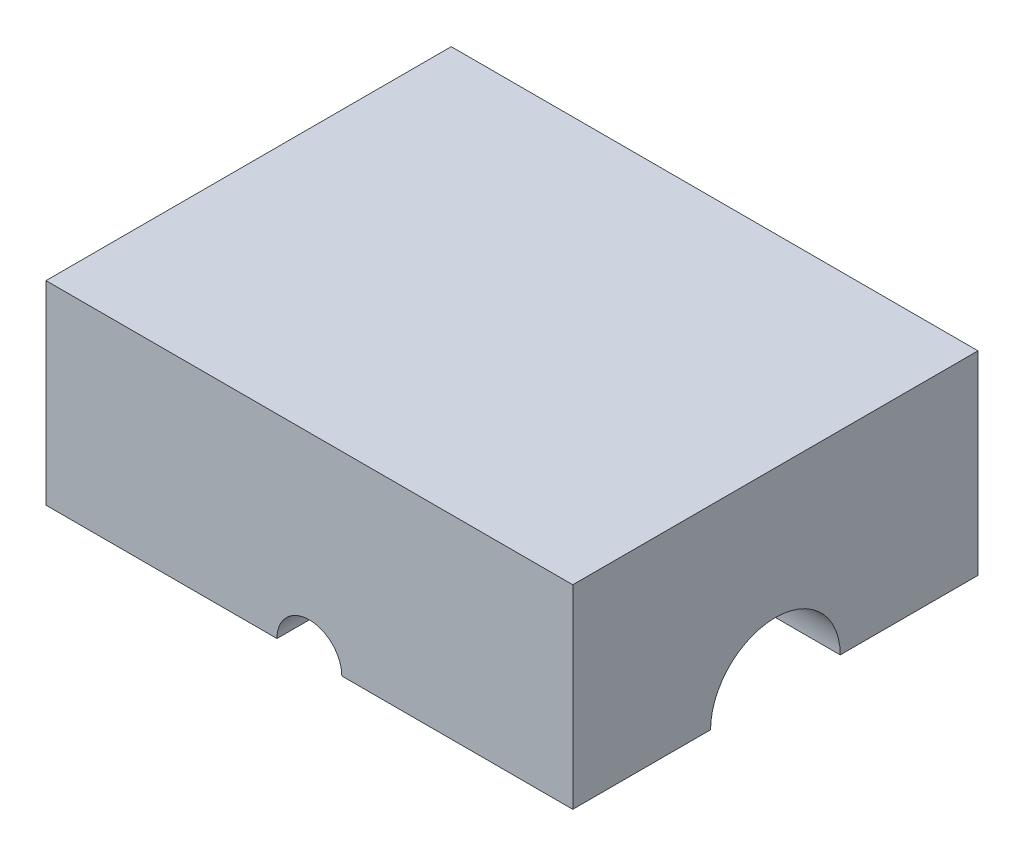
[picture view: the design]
ISO-10303-21;
HEADER;
FILE_DESCRIPTION(('STEP AP214'),'2;1');
FILE_NAME('part.step','',(''),(''),'','','');
FILE_SCHEMA(('AUTOMOTIVE_DESIGN { 1 0 10303 214 1 1 1 1 }'));
ENDSEC;
DATA;
#1=APPLICATION_CONTEXT('core data for automotive mechanical design processes');
#2=APPLICATION_PROTOCOL_DEFINITION('international standard','automotive_design',2000,#1);
#3=PRODUCT_CONTEXT('',#1,'mechanical');
#4=PRODUCT('Part','Part','',(#3));
#5=PRODUCT_RELATED_PRODUCT_CATEGORY('part','',(#4));
#6=PRODUCT_DEFINITION_FORMATION('','',#4);
#7=PRODUCT_DEFINITION_CONTEXT('part definition',#1,'design');
#8=PRODUCT_DEFINITION('design','',#6,#7);
#9=PRODUCT_DEFINITION_SHAPE('','',#8);
#10=(LENGTH_UNIT() NAMED_UNIT(*) SI_UNIT(.MILLI.,.METRE.));
#11=(NAMED_UNIT(*) PLANE_ANGLE_UNIT() SI_UNIT($,.RADIAN.));
#12=(NAMED_UNIT(*) SI_UNIT($,.STERADIAN.) SOLID_ANGLE_UNIT());
#13=UNCERTAINTY_MEASURE_WITH_UNIT(LENGTH_MEASURE(1.E-05),#10,'distance_accuracy_value','');
#14=(GEOMETRIC_REPRESENTATION_CONTEXT(3) GLOBAL_UNCERTAINTY_ASSIGNED_CONTEXT((#13)) GLOBAL_UNIT_ASSIGNED_CONTEXT((#10,
#11,#12)) REPRESENTATION_CONTEXT('',''));
#15=CARTESIAN_POINT('',(0.,0.,0.));
#16=DIRECTION('',(0.,0.,1.));
#17=DIRECTION('',(1.,0.,0.));
#18=AXIS2_PLACEMENT_3D('',#15,#16,#17);
#19=CARTESIAN_POINT('',(206.375,0.,-158.75));
#20=DIRECTION('',(0.,-1.,0.));
#21=DIRECTION('',(0.,0.,-1.));
#22=AXIS2_PLACEMENT_3D('',#19,#20,#21);
#23=PLANE('',#22);
#24=DIRECTION('',(1.,0.,0.));
#25=VECTOR('',#24,1.);
#26=CARTESIAN_POINT('',(-206.375,0.,-50.8));
#27=LINE('',#26,#25);
#28=CARTESIAN_POINT('',(101.6,0.,-50.8));
#29=VERTEX_POINT('',#28);
#30=CARTESIAN_POINT('',(206.375,0.,-50.8));
#31=VERTEX_POINT('',#30);
#32=EDGE_CURVE('E291',#29,#31,#27,.T.);
#33=ORIENTED_EDGE('',*,*,#32,.F.);
#34=CARTESIAN_POINT('',(101.6,0.,-76.2));
#35=DIRECTION('',(0.,-1.,0.));
#36=DIRECTION('',(0.,0.,-1.));
#37=AXIS2_PLACEMENT_3D('',#34,#35,#36);
#38=CIRCLE('',#37,25.4);
#39=CARTESIAN_POINT('',(76.2,0.,-76.2));
#40=VERTEX_POINT('',#39);
#41=EDGE_CURVE('E283',#29,#40,#38,.T.);
#42=ORIENTED_EDGE('',*,*,#41,.T.);
#43=DIRECTION('',(0.,0.,1.));
#44=VECTOR('',#43,1.);
#45=CARTESIAN_POINT('',(76.2,0.,212.191735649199));
#46=LINE('',#45,#44);
#47=CARTESIAN_POINT('',(76.2,0.,-95.2500000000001));
#48=VERTEX_POINT('',#47);
#49=EDGE_CURVE('E208',#48,#40,#46,.T.);
#50=ORIENTED_EDGE('',*,*,#49,.F.);
#51=DIRECTION('',(1.,0.,0.));
#52=VECTOR('',#51,1.);
#53=CARTESIAN_POINT('',(206.375,0.,-95.2500000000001));
#54=LINE('',#53,#52);
#55=CARTESIAN_POINT('',(25.4,0.,-95.2500000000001));
#56=VERTEX_POINT('',#55);
#57=EDGE_CURVE('E197',#56,#48,#54,.T.);
#58=ORIENTED_EDGE('',*,*,#57,.F.);
#59=DIRECTION('',(0.,0.,1.));
#60=VECTOR('',#59,1.);
#61=CARTESIAN_POINT('',(25.4,0.,212.191735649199));
#62=LINE('',#61,#60);
#63=CARTESIAN_POINT('',(25.4,0.,-158.75));
#64=VERTEX_POINT('',#63);
#65=EDGE_CURVE('E206',#64,#56,#62,.T.);
#66=ORIENTED_EDGE('',*,*,#65,.F.);
#67=DIRECTION('',(-1.,0.,0.));
#68=VECTOR('',#67,1.);
#69=CARTESIAN_POINT('',(-206.375,0.,-158.75));
#70=LINE('',#69,#68);
#71=CARTESIAN_POINT('',(206.375,0.,-158.75));
#72=VERTEX_POINT('',#71);
#73=EDGE_CURVE('E174',#72,#64,#70,.T.);
#74=ORIENTED_EDGE('',*,*,#73,.F.);
#75=DIRECTION('',(0.,0.,-1.));
#76=VECTOR('',#75,1.);
#77=CARTESIAN_POINT('',(206.375,0.,158.75));
#78=LINE('',#77,#76);
#79=EDGE_CURVE('E326',#31,#72,#78,.T.);
#80=ORIENTED_EDGE('',*,*,#79,.F.);
#81=EDGE_LOOP('',(#33,#42,#50,#58,#66,#74,#80));
#82=FACE_BOUND('',#81,.T.);
#83=ADVANCED_FACE('F33',(#82),#23,.T.);
#84=DIRECTION('',(0.,0.,1.));
#85=VECTOR('',#84,1.);
#86=CARTESIAN_POINT('',(-76.2,0.,212.191735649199));
#87=LINE('',#86,#85);
#88=CARTESIAN_POINT('',(-76.2,0.,-76.2));
#89=VERTEX_POINT('',#88);
#90=CARTESIAN_POINT('',(-76.2,0.,-95.2500000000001));
#91=VERTEX_POINT('',#90);
#92=EDGE_CURVE('E196',#89,#91,#87,.F.);
#93=ORIENTED_EDGE('',*,*,#92,.F.);
#94=CARTESIAN_POINT('',(-101.6,0.,-76.2));
#95=DIRECTION('',(0.,-1.,0.));
#96=DIRECTION('',(0.,0.,-1.));
#97=AXIS2_PLACEMENT_3D('',#94,#95,#96);
#98=CIRCLE('',#97,25.4);
#99=CARTESIAN_POINT('',(-101.6,0.,-50.8));
#100=VERTEX_POINT('',#99);
#101=EDGE_CURVE('E60',#89,#100,#98,.T.);
#102=ORIENTED_EDGE('',*,*,#101,.T.);
#103=DIRECTION('',(1.,0.,0.));
#104=VECTOR('',#103,1.);
#105=CARTESIAN_POINT('',(-206.375,0.,-50.8));
#106=LINE('',#105,#104);
#107=CARTESIAN_POINT('',(-206.375,0.,-50.8));
#108=VERTEX_POINT('',#107);
#109=EDGE_CURVE('E150',#108,#100,#106,.T.);
#110=ORIENTED_EDGE('',*,*,#109,.F.);
#111=DIRECTION('',(0.,0.,1.));
#112=VECTOR('',#111,1.);
#113=CARTESIAN_POINT('',(-206.375,0.,158.75));
#114=LINE('',#113,#112);
#115=CARTESIAN_POINT('',(-206.375,0.,-158.75));
#116=VERTEX_POINT('',#115);
#117=EDGE_CURVE('E161',#116,#108,#114,.T.);
#118=ORIENTED_EDGE('',*,*,#117,.F.);
#119=CARTESIAN_POINT('',(-25.4,0.,-158.75));
#120=VERTEX_POINT('',#119);
#121=EDGE_CURVE('E334',#120,#116,#70,.T.);
#122=ORIENTED_EDGE('',*,*,#121,.F.);
#123=DIRECTION('',(0.,0.,1.));
#124=VECTOR('',#123,1.);
#125=CARTESIAN_POINT('',(-25.4,0.,212.191735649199));
#126=LINE('',#125,#124);
#127=CARTESIAN_POINT('',(-25.4,0.,-95.25));
#128=VERTEX_POINT('',#127);
#129=EDGE_CURVE('E191',#128,#120,#126,.F.);
#130=ORIENTED_EDGE('',*,*,#129,.F.);
#131=EDGE_CURVE('E193',#91,#128,#54,.T.);
#132=ORIENTED_EDGE('',*,*,#131,.F.);
#133=EDGE_LOOP('',(#93,#102,#110,#118,#122,#130,#132));
#134=FACE_BOUND('',#133,.T.);
#135=ADVANCED_FACE('F159',(#134),#23,.T.);
#136=CARTESIAN_POINT('',(76.2,0.,76.2));
#137=VERTEX_POINT('',#136);
#138=CARTESIAN_POINT('',(76.2,0.,95.25));
#139=VERTEX_POINT('',#138);
#140=EDGE_CURVE('E211',#137,#139,#46,.T.);
#141=ORIENTED_EDGE('',*,*,#140,.F.);
#142=CARTESIAN_POINT('',(101.6,0.,76.2));
#143=DIRECTION('',(0.,-1.,0.));
#144=DIRECTION('',(0.,0.,-1.));
#145=AXIS2_PLACEMENT_3D('',#142,#143,#144);
#146=CIRCLE('',#145,25.4);
#147=CARTESIAN_POINT('',(101.6,0.,50.8));
#148=VERTEX_POINT('',#147);
#149=EDGE_CURVE('E284',#137,#148,#146,.T.);
#150=ORIENTED_EDGE('',*,*,#149,.T.);
#151=DIRECTION('',(1.,0.,0.));
#152=VECTOR('',#151,1.);
#153=CARTESIAN_POINT('',(-206.375,0.,50.8));
#154=LINE('',#153,#152);
#155=CARTESIAN_POINT('',(206.375,0.,50.8));
#156=VERTEX_POINT('',#155);
#157=EDGE_CURVE('E155',#156,#148,#154,.F.);
#158=ORIENTED_EDGE('',*,*,#157,.F.);
#159=CARTESIAN_POINT('',(206.375,0.,158.75));
#160=VERTEX_POINT('',#159);
#161=EDGE_CURVE('E333',#160,#156,#78,.T.);
#162=ORIENTED_EDGE('',*,*,#161,.F.);
#163=DIRECTION('',(1.,0.,0.));
#164=VECTOR('',#163,1.);
#165=CARTESIAN_POINT('',(-206.375,0.,158.75));
#166=LINE('',#165,#164);
#167=CARTESIAN_POINT('',(25.4,0.,158.75));
#168=VERTEX_POINT('',#167);
#169=EDGE_CURVE('E169',#168,#160,#166,.T.);
#170=ORIENTED_EDGE('',*,*,#169,.F.);
#171=DIRECTION('',(0.,0.,1.));
#172=VECTOR('',#171,1.);
#173=CARTESIAN_POINT('',(25.4,0.,212.191735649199));
#174=LINE('',#173,#172);
#175=CARTESIAN_POINT('',(25.4,0.,95.25));
#176=VERTEX_POINT('',#175);
#177=EDGE_CURVE('E212',#176,#168,#174,.T.);
#178=ORIENTED_EDGE('',*,*,#177,.F.);
#179=DIRECTION('',(-1.,0.,0.));
#180=VECTOR('',#179,1.);
#181=CARTESIAN_POINT('',(206.375,0.,95.25));
#182=LINE('',#181,#180);
#183=EDGE_CURVE('E204',#139,#176,#182,.T.);
#184=ORIENTED_EDGE('',*,*,#183,.F.);
#185=EDGE_LOOP('',(#141,#150,#158,#162,#170,#178,#184));
#186=FACE_BOUND('',#185,.T.);
#187=ADVANCED_FACE('F303',(#186),#23,.T.);
#188=CARTESIAN_POINT('',(206.375,152.4,158.75));
#189=DIRECTION('',(-1.,0.,0.));
#190=DIRECTION('',(0.,0.,1.));
#191=AXIS2_PLACEMENT_3D('',#188,#189,#190);
#192=PLANE('',#191);
#193=ORIENTED_EDGE('',*,*,#161,.T.);
#194=CARTESIAN_POINT('',(206.375,0.,0.));
#195=DIRECTION('',(1.,0.,0.));
#196=DIRECTION('',(0.,0.,-1.));
#197=AXIS2_PLACEMENT_3D('',#194,#195,#196);
#198=CIRCLE('',#197,50.8);
#199=EDGE_CURVE('E156',#31,#156,#198,.T.);
#200=ORIENTED_EDGE('',*,*,#199,.F.);
#201=ORIENTED_EDGE('',*,*,#79,.T.);
#202=DIRECTION('',(0.,-1.,0.));
#203=VECTOR('',#202,1.);
#204=CARTESIAN_POINT('',(206.375,152.4,-158.75));
#205=LINE('',#204,#203);
#206=CARTESIAN_POINT('',(206.375,152.4,-158.75));
#207=VERTEX_POINT('',#206);
#208=EDGE_CURVE('E188',#207,#72,#205,.T.);
#209=ORIENTED_EDGE('',*,*,#208,.F.);
#210=DIRECTION('',(0.,0.,-1.));
#211=VECTOR('',#210,1.);
#212=CARTESIAN_POINT('',(206.375,152.4,158.75));
#213=LINE('',#212,#211);
#214=CARTESIAN_POINT('',(206.375,152.4,158.75));
#215=VERTEX_POINT('',#214);
#216=EDGE_CURVE('E179',#215,#207,#213,.T.);
#217=ORIENTED_EDGE('',*,*,#216,.F.);
#218=DIRECTION('',(0.,-1.,0.));
#219=VECTOR('',#218,1.);
#220=CARTESIAN_POINT('',(206.375,152.4,158.75));
#221=LINE('',#220,#219);
#222=EDGE_CURVE('E180',#215,#160,#221,.T.);
#223=ORIENTED_EDGE('',*,*,#222,.T.);
#224=EDGE_LOOP('',(#193,#200,#201,#209,#217,#223));
#225=FACE_BOUND('',#224,.T.);
#226=ADVANCED_FACE('F235',(#225),#192,.F.);
#227=CARTESIAN_POINT('',(-206.375,152.4,-158.75));
#228=DIRECTION('',(0.,0.,1.));
#229=DIRECTION('',(1.,0.,0.));
#230=AXIS2_PLACEMENT_3D('',#227,#228,#229);
#231=PLANE('',#230);
#232=ORIENTED_EDGE('',*,*,#73,.T.);
#233=CARTESIAN_POINT('',(0.,0.,-158.75));
#234=DIRECTION('',(0.,0.,1.));
#235=DIRECTION('',(1.,0.,0.));
#236=AXIS2_PLACEMENT_3D('',#233,#234,#235);
#237=CIRCLE('',#236,25.4);
#238=EDGE_CURVE('E162',#64,#120,#237,.T.);
#239=ORIENTED_EDGE('',*,*,#238,.T.);
#240=ORIENTED_EDGE('',*,*,#121,.T.);
#241=DIRECTION('',(0.,-1.,0.));
#242=VECTOR('',#241,1.);
#243=CARTESIAN_POINT('',(-206.375,152.4,-158.75));
#244=LINE('',#243,#242);
#245=CARTESIAN_POINT('',(-206.375,152.4,-158.75));
#246=VERTEX_POINT('',#245);
#247=EDGE_CURVE('E168',#246,#116,#244,.T.);
#248=ORIENTED_EDGE('',*,*,#247,.F.);
#249=DIRECTION('',(-1.,0.,0.));
#250=VECTOR('',#249,1.);
#251=CARTESIAN_POINT('',(-206.375,152.4,-158.75));
#252=LINE('',#251,#250);
#253=EDGE_CURVE('E329',#207,#246,#252,.T.);
#254=ORIENTED_EDGE('',*,*,#253,.F.);
#255=ORIENTED_EDGE('',*,*,#208,.T.);
#256=EDGE_LOOP('',(#232,#239,#240,#248,#254,#255));
#257=FACE_BOUND('',#256,.T.);
#258=ADVANCED_FACE('F342',(#257),#231,.F.);
#259=CARTESIAN_POINT('',(-206.375,152.4,158.75));
#260=DIRECTION('',(1.,0.,0.));
#261=DIRECTION('',(0.,0.,-1.));
#262=AXIS2_PLACEMENT_3D('',#259,#260,#261);
#263=PLANE('',#262);
#264=ORIENTED_EDGE('',*,*,#117,.T.);
#265=CARTESIAN_POINT('',(-206.375,0.,0.));
#266=DIRECTION('',(1.,0.,0.));
#267=DIRECTION('',(0.,0.,-1.));
#268=AXIS2_PLACEMENT_3D('',#265,#266,#267);
#269=CIRCLE('',#268,50.8);
#270=CARTESIAN_POINT('',(-206.375,0.,50.8));
#271=VERTEX_POINT('',#270);
#272=EDGE_CURVE('E148',#108,#271,#269,.T.);
#273=ORIENTED_EDGE('',*,*,#272,.T.);
#274=CARTESIAN_POINT('',(-206.375,0.,158.75));
#275=VERTEX_POINT('',#274);
#276=EDGE_CURVE('E170',#271,#275,#114,.T.);
#277=ORIENTED_EDGE('',*,*,#276,.T.);
#278=DIRECTION('',(0.,-1.,0.));
#279=VECTOR('',#278,1.);
#280=CARTESIAN_POINT('',(-206.375,152.4,158.75));
#281=LINE('',#280,#279);
#282=CARTESIAN_POINT('',(-206.375,152.4,158.75));
#283=VERTEX_POINT('',#282);
#284=EDGE_CURVE('E183',#283,#275,#281,.T.);
#285=ORIENTED_EDGE('',*,*,#284,.F.);
#286=DIRECTION('',(0.,0.,1.));
#287=VECTOR('',#286,1.);
#288=CARTESIAN_POINT('',(-206.375,152.4,158.75));
#289=LINE('',#288,#287);
#290=EDGE_CURVE('E331',#246,#283,#289,.T.);
#291=ORIENTED_EDGE('',*,*,#290,.F.);
#292=ORIENTED_EDGE('',*,*,#247,.T.);
#293=EDGE_LOOP('',(#264,#273,#277,#285,#291,#292));
#294=FACE_BOUND('',#293,.T.);
#295=ADVANCED_FACE('F165',(#294),#263,.F.);
#296=CARTESIAN_POINT('',(-206.375,152.4,158.75));
#297=DIRECTION('',(0.,0.,-1.));
#298=DIRECTION('',(-1.,0.,0.));
#299=AXIS2_PLACEMENT_3D('',#296,#297,#298);
#300=PLANE('',#299);
#301=CARTESIAN_POINT('',(-25.4,0.,158.75));
#302=VERTEX_POINT('',#301);
#303=EDGE_CURVE('E172',#275,#302,#166,.T.);
#304=ORIENTED_EDGE('',*,*,#303,.T.);
#305=CARTESIAN_POINT('',(0.,0.,158.75));
#306=DIRECTION('',(0.,0.,1.));
#307=DIRECTION('',(1.,0.,0.));
#308=AXIS2_PLACEMENT_3D('',#305,#306,#307);
#309=CIRCLE('',#308,25.4);
#310=EDGE_CURVE('E324',#168,#302,#309,.T.);
#311=ORIENTED_EDGE('',*,*,#310,.F.);
#312=ORIENTED_EDGE('',*,*,#169,.T.);
#313=ORIENTED_EDGE('',*,*,#222,.F.);
#314=DIRECTION('',(1.,0.,0.));
#315=VECTOR('',#314,1.);
#316=CARTESIAN_POINT('',(-206.375,152.4,158.75));
#317=LINE('',#316,#315);
#318=EDGE_CURVE('E184',#283,#215,#317,.T.);
#319=ORIENTED_EDGE('',*,*,#318,.F.);
#320=ORIENTED_EDGE('',*,*,#284,.T.);
#321=EDGE_LOOP('',(#304,#311,#312,#313,#319,#320));
#322=FACE_BOUND('',#321,.T.);
#323=ADVANCED_FACE('F351',(#322),#300,.F.);
#324=CARTESIAN_POINT('',(206.375,152.4,-158.75));
#325=DIRECTION('',(0.,-1.,0.));
#326=DIRECTION('',(0.,0.,-1.));
#327=AXIS2_PLACEMENT_3D('',#324,#325,#326);
#328=PLANE('',#327);
#329=ORIENTED_EDGE('',*,*,#216,.T.);
#330=ORIENTED_EDGE('',*,*,#253,.T.);
#331=ORIENTED_EDGE('',*,*,#290,.T.);
#332=ORIENTED_EDGE('',*,*,#318,.T.);
#333=EDGE_LOOP('',(#329,#330,#331,#332));
#334=FACE_BOUND('',#333,.T.);
#335=ADVANCED_FACE('F344',(#334),#328,.F.);
#336=DIRECTION('',(1.,0.,0.));
#337=VECTOR('',#336,1.);
#338=CARTESIAN_POINT('',(-206.375,0.,50.8));
#339=LINE('',#338,#337);
#340=CARTESIAN_POINT('',(-101.6,0.,50.8));
#341=VERTEX_POINT('',#340);
#342=EDGE_CURVE('E151',#341,#271,#339,.F.);
#343=ORIENTED_EDGE('',*,*,#342,.F.);
#344=CARTESIAN_POINT('',(-101.6,0.,76.2));
#345=DIRECTION('',(0.,-1.,0.));
#346=DIRECTION('',(0.,0.,-1.));
#347=AXIS2_PLACEMENT_3D('',#344,#345,#346);
#348=CIRCLE('',#347,25.4);
#349=CARTESIAN_POINT('',(-76.2,0.,76.2));
#350=VERTEX_POINT('',#349);
#351=EDGE_CURVE('E11',#341,#350,#348,.T.);
#352=ORIENTED_EDGE('',*,*,#351,.T.);
#353=CARTESIAN_POINT('',(-76.2,0.,95.25));
#354=VERTEX_POINT('',#353);
#355=EDGE_CURVE('E198',#354,#350,#87,.F.);
#356=ORIENTED_EDGE('',*,*,#355,.F.);
#357=CARTESIAN_POINT('',(-25.4,0.,95.25));
#358=VERTEX_POINT('',#357);
#359=EDGE_CURVE('E201',#358,#354,#182,.T.);
#360=ORIENTED_EDGE('',*,*,#359,.F.);
#361=DIRECTION('',(0.,0.,1.));
#362=VECTOR('',#361,1.);
#363=CARTESIAN_POINT('',(-25.4,0.,212.191735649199));
#364=LINE('',#363,#362);
#365=EDGE_CURVE('E203',#302,#358,#364,.F.);
#366=ORIENTED_EDGE('',*,*,#365,.F.);
#367=ORIENTED_EDGE('',*,*,#303,.F.);
#368=ORIENTED_EDGE('',*,*,#276,.F.);
#369=EDGE_LOOP('',(#343,#352,#356,#360,#366,#367,#368));
#370=FACE_BOUND('',#369,.T.);
#371=ADVANCED_FACE('F359',(#370),#23,.T.);
#372=CARTESIAN_POINT('',(0.,0.,212.191735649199));
#373=DIRECTION('',(0.,0.,1.));
#374=DIRECTION('',(1.,0.,0.));
#375=AXIS2_PLACEMENT_3D('',#372,#373,#374);
#376=CYLINDRICAL_SURFACE('',#375,25.4);
#377=ORIENTED_EDGE('',*,*,#177,.T.);
#378=ORIENTED_EDGE('',*,*,#310,.T.);
#379=ORIENTED_EDGE('',*,*,#365,.T.);
#380=CARTESIAN_POINT('',(0.,0.,95.25));
#381=DIRECTION('',(0.,0.,1.));
#382=DIRECTION('',(1.,0.,0.));
#383=AXIS2_PLACEMENT_3D('',#380,#381,#382);
#384=CIRCLE('',#383,25.4);
#385=EDGE_CURVE('E321',#176,#358,#384,.T.);
#386=ORIENTED_EDGE('',*,*,#385,.F.);
#387=EDGE_LOOP('',(#377,#378,#379,#386));
#388=FACE_BOUND('',#387,.T.);
#389=ADVANCED_FACE('F355',(#388),#376,.F.);
#390=CARTESIAN_POINT('',(25.4,0.,95.25));
#391=DIRECTION('',(0.,0.,1.));
#392=DIRECTION('',(1.,0.,0.));
#393=AXIS2_PLACEMENT_3D('',#390,#391,#392);
#394=PLANE('',#393);
#395=ORIENTED_EDGE('',*,*,#183,.T.);
#396=ORIENTED_EDGE('',*,*,#385,.T.);
#397=ORIENTED_EDGE('',*,*,#359,.T.);
#398=CARTESIAN_POINT('',(0.,0.,95.25));
#399=DIRECTION('',(0.,0.,1.));
#400=DIRECTION('',(1.,0.,0.));
#401=AXIS2_PLACEMENT_3D('',#398,#399,#400);
#402=CIRCLE('',#401,76.2);
#403=EDGE_CURVE('E318',#139,#354,#402,.T.);
#404=ORIENTED_EDGE('',*,*,#403,.F.);
#405=EDGE_LOOP('',(#395,#396,#397,#404));
#406=FACE_BOUND('',#405,.T.);
#407=ADVANCED_FACE('F363',(#406),#394,.F.);
#408=CARTESIAN_POINT('',(0.,0.,212.191735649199));
#409=DIRECTION('',(0.,0.,1.));
#410=DIRECTION('',(1.,0.,0.));
#411=AXIS2_PLACEMENT_3D('',#408,#409,#410);
#412=CYLINDRICAL_SURFACE('',#411,76.2);
#413=ORIENTED_EDGE('',*,*,#49,.T.);
#414=CARTESIAN_POINT('',(93.6307408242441,-26.2961287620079,-43.464394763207));
#415=CARTESIAN_POINT('',(74.1399881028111,-20.285317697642,-47.1009589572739));
#416=CARTESIAN_POINT('',(70.2230556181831,-29.5831448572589,-65.1965921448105));
#417=CARTESIAN_POINT('',(93.9618757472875,-25.7721086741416,-43.7814237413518));
#418=CARTESIAN_POINT('',(74.2726745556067,-19.7514888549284,-47.3246044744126));
#419=CARTESIAN_POINT('',(70.4714068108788,-28.9936222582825,-65.6721356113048));
#420=CARTESIAN_POINT('',(94.2858711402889,-25.2409363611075,-44.0898431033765));
#421=CARTESIAN_POINT('',(74.3972791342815,-19.2212058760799,-47.5349200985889));
#422=CARTESIAN_POINT('',(70.7144033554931,-28.3960534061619,-66.1347646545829));
#423=CARTESIAN_POINT('',(94.9182882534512,-24.1645337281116,-44.6888678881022));
#424=CARTESIAN_POINT('',(74.6316958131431,-18.1655703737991,-47.9315837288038));
#425=CARTESIAN_POINT('',(71.1887161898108,-27.1851004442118,-67.0333018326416));
#426=CARTESIAN_POINT('',(95.2267083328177,-23.6193019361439,-44.9794714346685));
#427=CARTESIAN_POINT('',(74.7413855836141,-17.6403546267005,-48.1177318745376));
#428=CARTESIAN_POINT('',(71.4200312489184,-26.5717146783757,-67.46920715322));
#429=CARTESIAN_POINT('',(96.1269434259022,-21.9623505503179,-45.8239275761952));
#430=CARTESIAN_POINT('',(75.0497239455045,-16.0692325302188,-48.6433074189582));
#431=CARTESIAN_POINT('',(72.0952075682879,-24.7076443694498,-68.7358913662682));
#432=CARTESIAN_POINT('',(96.6933075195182,-20.8300441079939,-46.350019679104));
#433=CARTESIAN_POINT('',(75.2247819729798,-15.0396446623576,-48.9450593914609));
#434=CARTESIAN_POINT('',(72.5199806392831,-23.4337996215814,-69.525029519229));
#435=CARTESIAN_POINT('',(97.7492264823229,-18.5108649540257,-47.3241651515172));
#436=CARTESIAN_POINT('',(75.522644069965,-13.0160027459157,-49.4667083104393));
#437=CARTESIAN_POINT('',(73.3119198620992,-20.8247230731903,-70.9862477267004));
#438=CARTESIAN_POINT('',(98.2384451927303,-17.3237810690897,-47.7718778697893));
#439=CARTESIAN_POINT('',(75.6443632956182,-12.0240755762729,-49.6848638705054));
#440=CARTESIAN_POINT('',(73.6788338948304,-19.4892537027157,-71.6578168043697));
#441=CARTESIAN_POINT('',(99.1267512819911,-14.9060823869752,-48.5805787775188));
#442=CARTESIAN_POINT('',(75.8431772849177,-10.088454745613,-50.0503528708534));
#443=CARTESIAN_POINT('',(74.345063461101,-16.7693426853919,-72.8708681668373));
#444=CARTESIAN_POINT('',(99.5258635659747,-13.6754797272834,-48.9415909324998));
#445=CARTESIAN_POINT('',(75.9196275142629,-9.1470376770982,-50.1966175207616));
#446=CARTESIAN_POINT('',(74.6443976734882,-15.3849146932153,-73.412386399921));
#447=CARTESIAN_POINT('',(100.226882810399,-11.1714331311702,-49.5733367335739));
#448=CARTESIAN_POINT('',(76.0393037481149,-7.30766902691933,-50.4339673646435));
#449=CARTESIAN_POINT('',(75.1701621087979,-12.5678622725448,-74.3600050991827));
#450=CARTESIAN_POINT('',(100.528221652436,-9.89778467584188,-49.8435430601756));
#451=CARTESIAN_POINT('',(76.0819012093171,-6.41258077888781,-50.5239618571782));
#452=CARTESIAN_POINT('',(75.396166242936,-11.1350077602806,-74.7653145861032));
#453=CARTESIAN_POINT('',(101.023001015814,-7.3242250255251,-50.2861847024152));
#454=CARTESIAN_POINT('',(76.1446504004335,-4.66354973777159,-50.6623263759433));
#455=CARTESIAN_POINT('',(75.7672507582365,-8.23975315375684,-75.4292770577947));
#456=CARTESIAN_POINT('',(101.216432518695,-6.02431164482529,-50.4586118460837));
#457=CARTESIAN_POINT('',(76.1645743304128,-3.81220123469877,-50.710244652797));
#458=CARTESIAN_POINT('',(75.9123243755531,-6.77735060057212,-75.6879177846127));
#459=CARTESIAN_POINT('',(101.489830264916,-3.41346290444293,-50.7020940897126));
#460=CARTESIAN_POINT('',(76.191020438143,-2.13652781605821,-50.7758098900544));
#461=CARTESIAN_POINT('',(76.1173726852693,-3.84014576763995,-76.0531411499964));
#462=CARTESIAN_POINT('',(101.57011671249,-2.10256925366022,-50.7734352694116));
#463=CARTESIAN_POINT('',(76.1974947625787,-1.31464606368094,-50.7933403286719));
#464=CARTESIAN_POINT('',(76.1775875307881,-2.36539041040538,-76.1601529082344));
#465=CARTESIAN_POINT('',(101.616044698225,0.521597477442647,-50.8142634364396));
#466=CARTESIAN_POINT('',(76.2013505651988,0.32678202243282,-50.8035840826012));
#467=CARTESIAN_POINT('',(76.2120335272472,0.586797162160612,-76.2213951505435));
#468=CARTESIAN_POINT('',(101.581700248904,1.83487024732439,-50.7837628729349));
#469=CARTESIAN_POINT('',(76.1987218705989,1.14385522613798,-50.7962700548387));
#470=CARTESIAN_POINT('',(76.1862751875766,2.06422902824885,-76.1756443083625));
#471=CARTESIAN_POINT('',(101.409846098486,4.3014438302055,-50.6308713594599));
#472=CARTESIAN_POINT('',(76.1833360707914,2.70420347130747,-50.7566798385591));
#473=CARTESIAN_POINT('',(76.0573845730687,4.83912430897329,-75.9463070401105));
#474=CARTESIAN_POINT('',(101.284611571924,5.45582824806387,-50.5194128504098));
#475=CARTESIAN_POINT('',(76.1718127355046,3.44317417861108,-50.7274576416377));
#476=CARTESIAN_POINT('',(75.9634586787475,6.13780677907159,-75.7791192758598));
#477=CARTESIAN_POINT('',(100.94776140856,7.74867130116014,-50.2188678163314));
#478=CARTESIAN_POINT('',(76.1350188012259,4.95090038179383,-50.64111868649));
#479=CARTESIAN_POINT('',(75.7108210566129,8.71725521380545,-75.3283017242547));
#480=CARTESIAN_POINT('',(100.736153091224,8.88713127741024,-50.0297878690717));
#481=CARTESIAN_POINT('',(76.1098487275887,5.71788808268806,-50.5842185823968));
#482=CARTESIAN_POINT('',(75.5521148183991,9.99802268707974,-75.0446818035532));
#483=CARTESIAN_POINT('',(100.230612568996,11.141726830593,-49.57646115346));
#484=CARTESIAN_POINT('',(76.0383498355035,7.29146514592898,-50.4329882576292));
#485=CARTESIAN_POINT('',(75.1729594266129,12.5344426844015,-74.3646917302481));
#486=CARTESIAN_POINT('',(99.9366065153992,12.257841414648,-49.312146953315));
#487=CARTESIAN_POINT('',(75.9922056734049,8.09631019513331,-50.3390087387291));
#488=CARTESIAN_POINT('',(74.9524548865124,13.7900715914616,-73.968220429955));
#489=CARTESIAN_POINT('',(99.27199204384,14.4602278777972,-48.7118540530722));
#490=CARTESIAN_POINT('',(75.8704172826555,9.74852173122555,-50.1026706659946));
#491=CARTESIAN_POINT('',(74.4539940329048,16.2677563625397,-73.0677810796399));
#492=CARTESIAN_POINT('',(98.9013800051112,15.5464983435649,-48.3758719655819));
#493=CARTESIAN_POINT('',(75.7951116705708,10.5941607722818,-49.9608981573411));
#494=CARTESIAN_POINT('',(74.1760350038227,17.4898106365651,-72.5638079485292));
#495=CARTESIAN_POINT('',(98.0804842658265,17.7093230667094,-47.6273107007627));
#496=CARTESIAN_POINT('',(75.604971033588,12.3465589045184,-49.6142094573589));
#497=CARTESIAN_POINT('',(73.5603631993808,19.9229884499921,-71.4409660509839));
#498=CARTESIAN_POINT('',(97.6285042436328,18.7850207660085,-47.2130889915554));
#499=CARTESIAN_POINT('',(75.4897217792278,13.2528285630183,-49.4086648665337));
#500=CARTESIAN_POINT('',(73.2213781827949,21.1331483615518,-70.8196334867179));
#501=CARTESIAN_POINT('',(96.6590675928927,20.8946937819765,-46.3180836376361));
#502=CARTESIAN_POINT('',(75.2135119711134,15.1009904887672,-48.9257680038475));
#503=CARTESIAN_POINT('',(72.4943006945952,23.5065305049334,-69.4771254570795));
#504=CARTESIAN_POINT('',(96.14161071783,21.9286689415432,-45.8372997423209));
#505=CARTESIAN_POINT('',(75.0531991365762,16.0414648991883,-48.6494606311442));
#506=CARTESIAN_POINT('',(72.1062080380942,24.6697525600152,-68.7559496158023));
#507=CARTESIAN_POINT('',(95.0496654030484,23.9510575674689,-44.8137382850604));
#508=CARTESIAN_POINT('',(74.682837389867,17.9474497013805,-48.0177328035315));
#509=CARTESIAN_POINT('',(71.2872490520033,26.9449397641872,-67.2206074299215));
#510=CARTESIAN_POINT('',(94.4751918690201,24.9394828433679,-44.2709769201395));
#511=CARTESIAN_POINT('',(74.473526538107,18.9118893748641,-47.6635036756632));
#512=CARTESIAN_POINT('',(70.8563939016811,28.0569181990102,-66.4064653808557));
#513=CARTESIAN_POINT('',(93.2774553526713,26.8686394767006,-43.1274124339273));
#514=CARTESIAN_POINT('',(74.0036948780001,20.8541720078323,-46.8710123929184));
#515=CARTESIAN_POINT('',(69.9580915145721,30.2272194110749,-64.6911186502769));
#516=CARTESIAN_POINT('',(92.6541860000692,27.8093645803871,-42.5266017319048));
#517=CARTESIAN_POINT('',(73.743905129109,21.8313481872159,-46.4339554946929));
#518=CARTESIAN_POINT('',(69.4906395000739,31.2855351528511,-63.7899025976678));
#519=CARTESIAN_POINT('',(91.6371752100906,29.2572139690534,-41.533982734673));
#520=CARTESIAN_POINT('',(73.2925742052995,23.3805888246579,-45.6728469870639));
#521=CARTESIAN_POINT('',(68.7278814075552,32.9143657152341,-62.3009741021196));
#522=CARTESIAN_POINT('',(91.2566655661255,29.7808839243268,-41.1600634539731));
#523=CARTESIAN_POINT('',(73.1188977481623,23.9484677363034,-45.3796196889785));
#524=CARTESIAN_POINT('',(68.4424991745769,33.5034944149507,-61.7400951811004));
#525=CARTESIAN_POINT('',(90.4838775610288,30.8110663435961,-40.3946762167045));
#526=CARTESIAN_POINT('',(72.7554497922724,25.0818573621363,-44.7641395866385));
#527=CARTESIAN_POINT('',(67.8629081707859,34.6624496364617,-60.5920143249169));
#528=CARTESIAN_POINT('',(90.0916015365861,31.3175821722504,-40.0032117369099));
#529=CARTESIAN_POINT('',(72.5658056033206,25.6473549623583,-44.4421152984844));
#530=CARTESIAN_POINT('',(67.5687011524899,35.2322799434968,-60.0048176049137));
#531=CARTESIAN_POINT('',(88.8994162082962,32.81135122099,-38.8031833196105));
#532=CARTESIAN_POINT('',(71.9757956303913,27.3312759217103,-43.4357994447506));
#533=CARTESIAN_POINT('',(66.6745621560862,36.9127701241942,-58.2047749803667));
#534=CARTESIAN_POINT('',(88.0841631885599,33.7728068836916,-37.9689975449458));
#535=CARTESIAN_POINT('',(71.5508246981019,28.44923397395,-42.7053683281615));
#536=CARTESIAN_POINT('',(66.0631223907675,37.9944077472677,-56.9534963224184));
#537=CARTESIAN_POINT('',(86.4253599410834,35.6267331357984,-36.2352061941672));
#538=CARTESIAN_POINT('',(70.6468172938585,30.651467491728,-41.1274961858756));
#539=CARTESIAN_POINT('',(64.8190199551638,40.0800747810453,-54.3528092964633));
#540=CARTESIAN_POINT('',(85.5817602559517,36.5190731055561,-35.3354826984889));
#541=CARTESIAN_POINT('',(70.1682942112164,31.7364544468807,-40.2812198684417));
#542=CARTESIAN_POINT('',(64.1863201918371,41.0839572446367,-53.003224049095));
#543=CARTESIAN_POINT('',(83.8818174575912,38.2318788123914,-33.4748013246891));
#544=CARTESIAN_POINT('',(69.1693028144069,33.8554007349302,-38.4756188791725));
#545=CARTESIAN_POINT('',(62.911363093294,43.0108636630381,-50.2122019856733));
#546=CARTESIAN_POINT('',(83.0254737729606,39.0523413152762,-32.5138406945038));
#547=CARTESIAN_POINT('',(68.6491497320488,34.8905138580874,-37.5173486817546));
#548=CARTESIAN_POINT('',(62.2691053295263,43.9338839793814,-48.7707610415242));
#549=CARTESIAN_POINT('',(81.6603649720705,40.3038367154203,-30.9323280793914));
#550=CARTESIAN_POINT('',(67.7942821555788,36.4954618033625,-35.896111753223));
#551=CARTESIAN_POINT('',(61.2452737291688,45.3418163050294,-46.3984921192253));
#552=CARTESIAN_POINT('',(81.1506351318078,40.7585342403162,-30.3306999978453));
#553=CARTESIAN_POINT('',(67.4706093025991,37.0826786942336,-35.2724288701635));
#554=CARTESIAN_POINT('',(60.8629763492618,45.8533510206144,-45.4960499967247));
#555=CARTESIAN_POINT('',(80.1357162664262,41.641446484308,-29.1066887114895));
#556=CARTESIAN_POINT('',(66.8167387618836,38.2315319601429,-33.9871048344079));
#557=CARTESIAN_POINT('',(60.1017871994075,46.8466272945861,-43.6600330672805));
#558=CARTESIAN_POINT('',(79.630526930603,42.0696630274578,-28.484306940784));
#559=CARTESIAN_POINT('',(66.4864994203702,38.7935044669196,-33.3255601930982));
#560=CARTESIAN_POINT('',(59.722895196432,47.3283709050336,-42.7264604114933));
#561=CARTESIAN_POINT('',(78.6282379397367,42.8993596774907,-27.2187017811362));
#562=CARTESIAN_POINT('',(65.8229457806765,39.8895557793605,-31.9649705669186));
#563=CARTESIAN_POINT('',(58.9711784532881,48.2617796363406,-40.8280526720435));
#564=CARTESIAN_POINT('',(78.1311418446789,43.300828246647,-26.5754695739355));
#565=CARTESIAN_POINT('',(65.4895475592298,40.4239793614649,-31.2659485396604));
#566=CARTESIAN_POINT('',(58.5983563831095,48.713431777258,-39.8632043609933));
#567=CARTESIAN_POINT('',(77.1494115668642,44.0762339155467,-25.268614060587));
#568=CARTESIAN_POINT('',(64.8237939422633,41.4621088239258,-29.8315232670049));
#569=CARTESIAN_POINT('',(57.8620586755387,49.5857631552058,-37.9029210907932));
#570=CARTESIAN_POINT('',(76.6647760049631,44.4501740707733,-24.6049930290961));
#571=CARTESIAN_POINT('',(64.4913196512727,41.966186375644,-29.0961111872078));
#572=CARTESIAN_POINT('',(57.4985820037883,50.006445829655,-36.9074895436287));
#573=CARTESIAN_POINT('',(75.712963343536,45.1694283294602,-23.2582169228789));
#574=CARTESIAN_POINT('',(63.8320550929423,42.9405651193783,-27.5905497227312));
#575=CARTESIAN_POINT('',(56.7847225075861,50.8156068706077,-34.8873253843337));
#576=CARTESIAN_POINT('',(75.245764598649,45.5147786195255,-22.5750880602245));
#577=CARTESIAN_POINT('',(63.505107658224,43.4112800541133,-26.8203826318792));
#578=CARTESIAN_POINT('',(56.4343234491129,51.2041259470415,-33.8626320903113));
#579=CARTESIAN_POINT('',(74.3331075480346,46.1764932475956,-21.1887173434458));
#580=CARTESIAN_POINT('',(62.8611537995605,44.3170251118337,-25.2455069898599));
#581=CARTESIAN_POINT('',(55.749830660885,51.9485549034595,-31.7830760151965));
#582=CARTESIAN_POINT('',(73.8876500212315,46.4928565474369,-20.4854747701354));
#583=CARTESIAN_POINT('',(62.5439633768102,44.7524314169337,-24.4406667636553));
#584=CARTESIAN_POINT('',(55.4157375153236,52.3044636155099,-30.7282121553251));
#585=CARTESIAN_POINT('',(72.592184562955,47.3966405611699,-18.3464575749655));
#586=CARTESIAN_POINT('',(61.6172755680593,45.9976088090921,-21.9825015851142));
#587=CARTESIAN_POINT('',(54.444138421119,53.3212206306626,-27.5196863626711));
#588=CARTESIAN_POINT('',(71.7821872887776,47.9394220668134,-16.8801515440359));
#589=CARTESIAN_POINT('',(61.0261728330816,46.7556599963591,-20.2707136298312));
#590=CARTESIAN_POINT('',(53.8366404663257,53.9318498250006,-25.3202273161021));
#591=CARTESIAN_POINT('',(70.5492383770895,48.7435833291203,-14.3481095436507));
#592=CARTESIAN_POINT('',(60.1176428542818,47.884016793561,-17.283500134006));
#593=CARTESIAN_POINT('',(52.9119287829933,54.8365312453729,-21.5221643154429));
#594=CARTESIAN_POINT('',(70.0848532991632,49.0396910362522,-13.3021702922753));
#595=CARTESIAN_POINT('',(59.7727690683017,48.3012922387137,-16.0426043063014));
#596=CARTESIAN_POINT('',(52.5636399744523,55.1696524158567,-19.953255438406));
#597=CARTESIAN_POINT('',(69.2452312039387,49.5669743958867,-11.1781387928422));
#598=CARTESIAN_POINT('',(59.1465265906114,49.0457030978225,-13.5106222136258));
#599=CARTESIAN_POINT('',(51.9339234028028,55.7628461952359,-16.7672081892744));
#600=CARTESIAN_POINT('',(68.8699783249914,49.7981616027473,-10.1000523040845));
#601=CARTESIAN_POINT('',(58.8645403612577,49.373639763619,-12.2184467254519));
#602=CARTESIAN_POINT('',(51.6524837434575,56.0229318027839,-15.1500784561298));
#603=CARTESIAN_POINT('',(68.3864243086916,50.0928207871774,-8.46495428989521));
#604=CARTESIAN_POINT('',(58.4999356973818,49.7923188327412,-10.2506810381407));
#605=CARTESIAN_POINT('',(51.2898182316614,56.3544233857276,-12.6974314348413));
#606=CARTESIAN_POINT('',(68.2385946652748,50.1822749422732,-7.91761554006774));
#607=CARTESIAN_POINT('',(58.3882813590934,49.9195106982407,-9.59123752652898));
#608=CARTESIAN_POINT('',(51.1789459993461,56.455059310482,-11.8764233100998));
#609=CARTESIAN_POINT('',(67.9707993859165,50.3435447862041,-6.81736216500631));
#610=CARTESIAN_POINT('',(58.185764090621,50.1489439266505,-8.26384137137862));
#611=CARTESIAN_POINT('',(50.9780995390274,56.6364878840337,-10.2260432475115));
#612=CARTESIAN_POINT('',(67.85083003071,50.4153628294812,-6.2644482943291));
#613=CARTESIAN_POINT('',(58.094840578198,50.2512560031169,-7.59570735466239));
#614=CARTESIAN_POINT('',(50.8881225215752,56.7172831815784,-9.39667244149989));
#615=CARTESIAN_POINT('',(67.640279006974,50.540951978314,-5.15406739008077));
#616=CARTESIAN_POINT('',(57.9351325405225,50.4302278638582,-6.25258763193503));
#617=CARTESIAN_POINT('',(50.7302092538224,56.85857097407,-7.73110108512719));
#618=CARTESIAN_POINT('',(67.5496990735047,50.594722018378,-4.59660008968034));
#619=CARTESIAN_POINT('',(57.8663017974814,50.5069402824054,-5.57740600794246));
#620=CARTESIAN_POINT('',(50.662274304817,56.919062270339,-6.89490013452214));
#621=CARTESIAN_POINT('',(67.3991470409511,50.6838792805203,-3.47835619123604));
#622=CARTESIAN_POINT('',(57.7518490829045,50.6341516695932,-4.22214475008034));
#623=CARTESIAN_POINT('',(50.5493602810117,57.0193641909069,-5.21753428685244));
#624=CARTESIAN_POINT('',(67.3391749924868,50.7192664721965,-2.91757958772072));
#625=CARTESIAN_POINT('',(57.7061920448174,50.6846899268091,-3.54185958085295));
#626=CARTESIAN_POINT('',(50.5043812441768,57.0591747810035,-4.37636938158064));
#627=CARTESIAN_POINT('',(67.2502744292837,50.7716638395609,-1.78891495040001));
#628=CARTESIAN_POINT('',(57.6385093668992,50.7595119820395,-2.17223435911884));
#629=CARTESIAN_POINT('',(50.4377058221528,57.1181218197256,-2.68337242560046));
#630=CARTESIAN_POINT('',(67.2216349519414,50.7885029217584,-1.22100879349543));
#631=CARTESIAN_POINT('',(57.6166820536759,50.7835753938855,-1.48264818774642));
#632=CARTESIAN_POINT('',(50.4162262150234,57.1370657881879,-1.8315131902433));
#633=CARTESIAN_POINT('',(67.196799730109,50.803107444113,-0.0846340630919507));
#634=CARTESIAN_POINT('',(57.5977610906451,50.804438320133,-0.10283387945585));
#635=CARTESIAN_POINT('',(50.3975997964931,57.1534958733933,-0.126951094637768));
#636=CARTESIAN_POINT('',(67.2006040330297,50.8008728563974,0.483834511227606));
#637=CARTESIAN_POINT('',(57.6006613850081,50.8012445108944,0.587616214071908));
#638=CARTESIAN_POINT('',(50.4004530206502,57.1509819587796,0.725751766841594));
#639=CARTESIAN_POINT('',(67.2406008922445,50.7773453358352,1.61987385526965));
#640=CARTESIAN_POINT('',(57.6311305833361,50.7676365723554,1.96691322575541));
#641=CARTESIAN_POINT('',(50.4304506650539,57.1245134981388,2.42981078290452));
#642=CARTESIAN_POINT('',(67.2767938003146,50.7560521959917,2.1874446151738));
#643=CARTESIAN_POINT('',(57.6587095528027,50.7372113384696,2.65598161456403));
#644=CARTESIAN_POINT('',(50.4575953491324,57.1005587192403,3.28116692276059));
#645=CARTESIAN_POINT('',(67.3810432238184,50.6945530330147,3.3202498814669));
#646=CARTESIAN_POINT('',(57.7380561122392,50.6494053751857,4.03030520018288));
#647=CARTESIAN_POINT('',(50.5357824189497,57.0313721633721,4.98037482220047));
#648=CARTESIAN_POINT('',(67.4490997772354,50.6543469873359,3.88548438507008));
#649=CARTESIAN_POINT('',(57.7898489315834,50.5919966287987,4.71577744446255));
#650=CARTESIAN_POINT('',(50.5868248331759,56.986140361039,5.82822657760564));
#651=CARTESIAN_POINT('',(67.6162506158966,50.5552070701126,5.01317665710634));
#652=CARTESIAN_POINT('',(57.9168599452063,50.4505789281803,6.08192420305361));
#653=CARTESIAN_POINT('',(50.7121879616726,56.87460795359,7.519764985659));
#654=CARTESIAN_POINT('',(67.7153947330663,50.4962431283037,5.57562848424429));
#655=CARTESIAN_POINT('',(57.9921552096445,50.3664828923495,6.76279810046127));
#656=CARTESIAN_POINT('',(50.7865460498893,56.8082735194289,8.3634427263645));
#657=CARTESIAN_POINT('',(67.9433542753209,50.3599665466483,6.69567829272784));
#658=CARTESIAN_POINT('',(58.1649472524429,50.1723564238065,8.11679402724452));
#659=CARTESIAN_POINT('',(50.957515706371,56.6549623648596,10.0435174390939));
#660=CARTESIAN_POINT('',(68.0721736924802,50.2826514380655,7.25327561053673));
#661=CARTESIAN_POINT('',(58.2624990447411,50.0622629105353,8.79011366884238));
#662=CARTESIAN_POINT('',(51.0541302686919,56.5679828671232,10.8799134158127));
#663=CARTESIAN_POINT('',(68.3578199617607,50.1101257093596,8.36243111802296));
#664=CARTESIAN_POINT('',(58.4783142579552,49.8169419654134,10.1271549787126));
#665=CARTESIAN_POINT('',(51.268364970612,56.3738914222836,12.5436466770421));
#666=CARTESIAN_POINT('',(68.5146447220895,50.0149164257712,8.91398975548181));
#667=CARTESIAN_POINT('',(58.5966384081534,49.6816433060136,10.7910625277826));
#668=CARTESIAN_POINT('',(51.3859835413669,56.2667809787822,13.3709846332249));
#669=CARTESIAN_POINT('',(68.8544337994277,49.8070946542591,10.0102302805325));
#670=CARTESIAN_POINT('',(58.852320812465,49.3867995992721,12.1078917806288));
#671=CARTESIAN_POINT('',(51.6408253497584,56.0329814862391,15.0153454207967));
#672=CARTESIAN_POINT('',(69.0374013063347,49.6944800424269,10.5549113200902));
#673=CARTESIAN_POINT('',(58.9897513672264,49.2271668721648,12.7609815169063));
#674=CARTESIAN_POINT('',(51.778050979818,55.9062900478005,15.8323669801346));
#675=CARTESIAN_POINT('',(69.6176333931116,49.3343356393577,12.163913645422));
#676=CARTESIAN_POINT('',(59.4246729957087,48.7170833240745,14.6874787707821));
#677=CARTESIAN_POINT('',(52.2132250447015,55.5011275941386,18.2458704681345));
#678=CARTESIAN_POINT('',(70.0499541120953,49.0622881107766,13.2172870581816));
#679=CARTESIAN_POINT('',(59.7472103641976,48.3327313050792,15.9421992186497));
#680=CARTESIAN_POINT('',(52.5374655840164,55.1950741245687,19.8259305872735));
#681=CARTESIAN_POINT('',(70.992423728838,48.4564568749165,15.2898063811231));
#682=CARTESIAN_POINT('',(60.4444696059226,47.4812795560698,18.3953826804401));
#683=CARTESIAN_POINT('',(53.2443177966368,54.5135139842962,22.9347095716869));
#684=CARTESIAN_POINT('',(71.5025698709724,48.1226753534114,16.3089535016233));
#685=CARTESIAN_POINT('',(60.8197993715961,47.0133410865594,19.5947687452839));
#686=CARTESIAN_POINT('',(53.6269274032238,54.1380097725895,24.4634302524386));
#687=CARTESIAN_POINT('',(72.5853559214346,47.3967459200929,18.3118518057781));
#688=CARTESIAN_POINT('',(61.6085535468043,46.0018638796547,21.9338459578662));
#689=CARTESIAN_POINT('',(54.4390169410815,53.3213391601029,27.4677777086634));
#690=CARTESIAN_POINT('',(73.1580411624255,47.0045555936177,19.2955766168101));
#691=CARTESIAN_POINT('',(62.022587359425,45.4573607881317,23.0741638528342));
#692=CARTESIAN_POINT('',(54.8685308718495,52.8801250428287,28.9433649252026));
#693=CARTESIAN_POINT('',(74.3511834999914,46.1649879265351,21.2259751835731));
#694=CARTESIAN_POINT('',(62.8751851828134,44.300018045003,25.2912912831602));
#695=CARTESIAN_POINT('',(55.7633876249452,51.9356114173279,31.8389627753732));
#696=CARTESIAN_POINT('',(74.9716474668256,45.7176026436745,22.1726435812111));
#697=CARTESIAN_POINT('',(63.314267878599,43.6862231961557,26.3685372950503));
#698=CARTESIAN_POINT('',(56.2287355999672,51.4323029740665,33.258965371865));
#699=CARTESIAN_POINT('',(76.0855066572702,44.8903060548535,23.792960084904));
#700=CARTESIAN_POINT('',(64.0911082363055,42.561657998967,28.1904893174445));
#701=CARTESIAN_POINT('',(57.064129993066,50.5015943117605,35.6894401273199));
#702=CARTESIAN_POINT('',(76.5712251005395,44.522053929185,24.4749658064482));
#703=CARTESIAN_POINT('',(64.4271017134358,42.0629423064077,28.9517108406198));
#704=CARTESIAN_POINT('',(57.4284188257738,50.0873106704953,36.7124487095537));
#705=CARTESIAN_POINT('',(77.5572598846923,43.7569233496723,25.8179976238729));
#706=CARTESIAN_POINT('',(65.1015775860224,41.0336218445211,30.4369078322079));
#707=CARTESIAN_POINT('',(58.16794491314,49.2265387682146,38.726996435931));
#708=CARTESIAN_POINT('',(78.0575774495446,43.3600424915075,26.4790219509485));
#709=CARTESIAN_POINT('',(65.4401992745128,40.5026249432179,31.1609169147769));
#710=CARTESIAN_POINT('',(58.5431830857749,48.7800478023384,39.7185329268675));
#711=CARTESIAN_POINT('',(79.0684622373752,42.538211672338,27.7800780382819));
#712=CARTESIAN_POINT('',(66.1157939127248,39.4112437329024,32.5710774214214));
#713=CARTESIAN_POINT('',(59.3013466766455,47.8554881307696,41.6701170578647));
#714=CARTESIAN_POINT('',(79.5790321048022,42.1132544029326,28.4201042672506));
#715=CARTESIAN_POINT('',(66.4528663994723,38.8504746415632,33.2571960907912));
#716=CARTESIAN_POINT('',(59.6842740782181,47.3774112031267,42.6301564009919));
#717=CARTESIAN_POINT('',(80.6062456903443,41.2358555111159,29.6788275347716));
#718=CARTESIAN_POINT('',(67.1214901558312,37.7022795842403,34.590724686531));
#719=CARTESIAN_POINT('',(60.4546842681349,46.3903374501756,44.5182413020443));
#720=CARTESIAN_POINT('',(81.1228900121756,40.7834111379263,30.2975224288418));
#721=CARTESIAN_POINT('',(67.453100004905,37.1144923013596,35.2380516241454));
#722=CARTESIAN_POINT('',(60.842167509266,45.8813375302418,45.4462836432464));
#723=CARTESIAN_POINT('',(82.6776564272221,39.3841324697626,32.1229499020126));
#724=CARTESIAN_POINT('',(68.4388047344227,35.3067644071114,37.1296038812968));
#725=CARTESIAN_POINT('',(62.0082423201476,44.3071490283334,48.1844248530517));
#726=CARTESIAN_POINT('',(83.7193271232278,38.3963833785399,33.2973953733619));
#727=CARTESIAN_POINT('',(69.0756840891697,34.0552285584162,38.3067610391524));
#728=CARTESIAN_POINT('',(62.789495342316,43.1959313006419,49.946093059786));
#729=CARTESIAN_POINT('',(85.7835493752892,36.3149570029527,35.5558951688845));
#730=CARTESIAN_POINT('',(70.2881365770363,31.480957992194,40.4974631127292));
#731=CARTESIAN_POINT('',(64.3376620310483,40.8543266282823,53.3338427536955));
#732=CARTESIAN_POINT('',(86.8061035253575,35.2212942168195,36.6399618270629));
#733=CARTESIAN_POINT('',(70.8631431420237,30.1561638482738,41.5091282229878));
#734=CARTESIAN_POINT('',(65.1045776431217,39.6239559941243,54.9599427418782));
#735=CARTESIAN_POINT('',(88.8144193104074,32.921275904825,38.7201753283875));
#736=CARTESIAN_POINT('',(71.9371528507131,27.4511854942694,43.3722632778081));
#737=CARTESIAN_POINT('',(66.6108144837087,37.0364353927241,58.0802629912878));
#738=CARTESIAN_POINT('',(89.7998450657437,31.7141322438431,39.7155969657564));
#739=CARTESIAN_POINT('',(72.4342198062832,26.0696665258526,44.2196610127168));
#740=CARTESIAN_POINT('',(67.3498838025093,35.6783987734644,59.5733954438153));
#741=CARTESIAN_POINT('',(91.7007881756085,29.1965861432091,41.6013409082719));
#742=CARTESIAN_POINT('',(73.3335541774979,23.2915601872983,45.7435729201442));
#743=CARTESIAN_POINT('',(68.7755911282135,32.8461594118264,62.4020113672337));
#744=CARTESIAN_POINT('',(92.616296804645,27.8861708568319,42.4916501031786));
#745=CARTESIAN_POINT('',(73.733990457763,21.8950890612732,46.4167998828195));
#746=CARTESIAN_POINT('',(69.4622225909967,31.3719422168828,63.7374751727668));
#747=CARTESIAN_POINT('',(93.9170122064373,25.8489536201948,43.7390472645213));
#748=CARTESIAN_POINT('',(74.256576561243,19.8254598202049,47.2973966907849));
#749=CARTESIAN_POINT('',(70.4377591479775,29.0800728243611,65.6085709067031));
#750=CARTESIAN_POINT('',(94.3381124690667,25.1586659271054,44.1398159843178));
#751=CARTESIAN_POINT('',(74.4183806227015,19.1362443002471,47.570441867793));
#752=CARTESIAN_POINT('',(70.753584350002,28.3034991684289,66.2097239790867));
#753=CARTESIAN_POINT('',(95.153614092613,23.7545250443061,44.9110669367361));
#754=CARTESIAN_POINT('',(74.7170564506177,17.766711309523,48.0762841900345));
#755=CARTESIAN_POINT('',(71.3652105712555,26.7238406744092,67.3666004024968));
#756=CARTESIAN_POINT('',(95.5480171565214,23.0406733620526,45.2815511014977));
#757=CARTESIAN_POINT('',(74.8536653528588,17.086702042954,48.3086529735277));
#758=CARTESIAN_POINT('',(71.6610128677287,25.9207575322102,67.9223266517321));
#759=CARTESIAN_POINT('',(96.3068809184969,21.5908455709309,45.9905011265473));
#760=CARTESIAN_POINT('',(75.1026424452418,15.739930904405,48.7349680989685));
#761=CARTESIAN_POINT('',(72.2301606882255,24.2897012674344,68.985751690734));
#762=CARTESIAN_POINT('',(96.6713572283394,20.8548812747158,46.328983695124));
#763=CARTESIAN_POINT('',(75.2147681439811,15.0735674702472,48.9285231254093));
#764=CARTESIAN_POINT('',(72.5035179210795,23.4617414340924,69.4934755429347));
#765=CARTESIAN_POINT('',(97.3677224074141,19.3616193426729,46.9726405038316));
#766=CARTESIAN_POINT('',(75.4163766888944,13.7569522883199,49.280042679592));
#767=CARTESIAN_POINT('',(73.0257918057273,21.7818217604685,70.4589607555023));
#768=CARTESIAN_POINT('',(97.6996034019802,18.6043166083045,47.2778066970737));
#769=CARTESIAN_POINT('',(75.5056188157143,13.1072034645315,49.4376190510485));
#770=CARTESIAN_POINT('',(73.2747025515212,20.9298561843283,70.9167100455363));
#771=CARTESIAN_POINT('',(98.4578220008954,16.7525764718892,47.9722052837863));
#772=CARTESIAN_POINT('',(75.6964497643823,11.5593625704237,49.7793518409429));
#773=CARTESIAN_POINT('',(73.8433665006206,18.8466485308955,71.9583079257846));
#774=CARTESIAN_POINT('',(98.8664355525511,15.6482772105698,48.3439872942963));
#775=CARTESIAN_POINT('',(75.7869751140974,10.6744117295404,49.9460065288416));
#776=CARTESIAN_POINT('',(74.1498266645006,17.6043118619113,72.515980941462));
#777=CARTESIAN_POINT('',(99.6049593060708,13.4060429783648,49.0131207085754));
#778=CARTESIAN_POINT('',(75.934584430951,8.94596732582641,50.2254219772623));
#779=CARTESIAN_POINT('',(74.7037194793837,15.081798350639,73.519681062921));
#780=CARTESIAN_POINT('',(99.9348880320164,12.2681159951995,49.3104896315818));
#781=CARTESIAN_POINT('',(75.9912508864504,8.10429698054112,50.3374747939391));
#782=CARTESIAN_POINT('',(74.9511660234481,13.8016304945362,73.9657344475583));
#783=CARTESIAN_POINT('',(100.365749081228,10.5418201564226,49.6976642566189));
#784=CARTESIAN_POINT('',(76.0575481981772,6.87400791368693,50.4734687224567));
#785=CARTESIAN_POINT('',(75.274311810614,11.8595476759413,74.5464963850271));
#786=CARTESIAN_POINT('',(100.498656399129,9.9633930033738,49.8168728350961));
#787=CARTESIAN_POINT('',(76.0765347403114,6.46869685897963,50.5134716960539));
#788=CARTESIAN_POINT('',(75.3739922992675,11.2088171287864,74.7253092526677));
#789=CARTESIAN_POINT('',(100.742553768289,8.80082034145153,50.0353394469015));
#790=CARTESIAN_POINT('',(76.1093582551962,5.66724381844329,50.5842011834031));
#791=CARTESIAN_POINT('',(75.5569153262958,9.9009228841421,75.0530091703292));
#792=CARTESIAN_POINT('',(100.853547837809,8.2166759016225,50.1346011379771));
#793=CARTESIAN_POINT('',(76.1231715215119,5.27134083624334,50.6148819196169));
#794=CARTESIAN_POINT('',(75.6401608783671,9.24376038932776,75.2019017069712));
#795=CARTESIAN_POINT('',(101.053048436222,7.04353206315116,50.3128281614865));
#796=CARTESIAN_POINT('',(76.1466496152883,4.48745195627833,50.668251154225));
#797=CARTESIAN_POINT('',(75.7897863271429,7.92397357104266,75.4692422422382));
#798=CARTESIAN_POINT('',(101.141552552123,6.45453215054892,50.3917913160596));
#799=CARTESIAN_POINT('',(76.1562967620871,4.09970742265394,50.6909033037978));
#800=CARTESIAN_POINT('',(75.8561644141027,7.26134866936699,75.5876869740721));
#801=CARTESIAN_POINT('',(101.2955878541,5.27281829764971,50.5291146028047));
#802=CARTESIAN_POINT('',(76.1722838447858,3.33064262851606,50.7292777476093));
#803=CARTESIAN_POINT('',(75.9716908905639,5.93192058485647,75.7936719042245));
#804=CARTESIAN_POINT('',(101.361117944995,4.68010418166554,50.5874737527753));
#805=CARTESIAN_POINT('',(76.1786123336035,2.94956074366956,50.7449746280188));
#806=CARTESIAN_POINT('',(76.0208384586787,5.26511720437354,75.8812106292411));
#807=CARTESIAN_POINT('',(101.522884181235,2.89534647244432,50.7314755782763));
#808=CARTESIAN_POINT('',(76.1937665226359,1.81075978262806,50.783135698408));
#809=CARTESIAN_POINT('',(76.1421631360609,3.25726478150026,76.097213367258));
#810=CARTESIAN_POINT('',(101.583886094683,1.69908667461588,50.7856770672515));
#811=CARTESIAN_POINT('',(76.1986600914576,1.06209143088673,50.7964238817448));
#812=CARTESIAN_POINT('',(76.1879145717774,1.91147250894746,76.1785156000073));
#813=CARTESIAN_POINT('',(101.610527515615,-0.694590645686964,50.8093571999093));
#814=CARTESIAN_POINT('',(76.2008743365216,-0.434478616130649,50.8023351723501));
#815=CARTESIAN_POINT('',(76.2078956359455,-0.781414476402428,76.214035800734));
#816=CARTESIAN_POINT('',(101.576165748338,-1.89200818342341,50.7788347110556));
#817=CARTESIAN_POINT('',(76.1981894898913,-1.18050476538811,50.7949433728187));
#818=CARTESIAN_POINT('',(76.1821243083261,-2.12850920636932,76.1682520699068));
#819=CARTESIAN_POINT('',(101.412756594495,-4.28095859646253,50.6334647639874));
#820=CARTESIAN_POINT('',(76.1836291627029,-2.69089908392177,50.7573941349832));
#821=CARTESIAN_POINT('',(76.0595674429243,-4.81607842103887,75.9501971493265));
#822=CARTESIAN_POINT('',(101.283542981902,-5.47247743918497,50.5184692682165));
#823=CARTESIAN_POINT('',(76.1717751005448,-3.45340150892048,50.7272915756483));
#824=CARTESIAN_POINT('',(75.9626572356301,-6.15653711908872,75.7777039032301));
#825=CARTESIAN_POINT('',(100.933139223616,-7.83839427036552,50.2058112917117));
#826=CARTESIAN_POINT('',(76.1333464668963,-5.01040488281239,50.6372748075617));
#827=CARTESIAN_POINT('',(75.6998544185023,-8.81819355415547,75.3087169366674));
#828=CARTESIAN_POINT('',(100.711955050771,-9.01279336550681,50.008154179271));
#829=CARTESIAN_POINT('',(76.1068833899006,-5.80296187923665,50.577600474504));
#830=CARTESIAN_POINT('',(75.5339662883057,-10.139392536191,75.0122312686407));
#831=CARTESIAN_POINT('',(100.192541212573,-11.2918628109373,49.5422500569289));
#832=CARTESIAN_POINT('',(76.0324796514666,-7.3989329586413,50.4209497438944));
#833=CARTESIAN_POINT('',(75.1444059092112,-12.7033456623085,74.313375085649));
#834=CARTESIAN_POINT('',(99.8975861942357,-12.3974811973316,49.2769959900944));
#835=CARTESIAN_POINT('',(75.9856177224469,-8.19879919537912,50.3258997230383));
#836=CARTESIAN_POINT('',(74.9231896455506,-13.9471663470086,73.9154939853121));
#837=CARTESIAN_POINT('',(99.2325624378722,-14.5792487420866,48.676135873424));
#838=CARTESIAN_POINT('',(75.862565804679,-9.84041137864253,50.0877957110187));
#839=CARTESIAN_POINT('',(74.4244218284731,-16.4016548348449,73.0142038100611));
#840=CARTESIAN_POINT('',(98.8624821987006,-15.6553933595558,48.3405190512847));
#841=CARTESIAN_POINT('',(75.7867083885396,-10.6804818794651,49.9453161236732));
#842=CARTESIAN_POINT('',(74.1468616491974,-17.6123175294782,72.5107785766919));
#843=CARTESIAN_POINT('',(98.0547641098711,-17.7700668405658,47.6037284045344));
#844=CARTESIAN_POINT('',(75.5983252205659,-12.3981964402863,49.602373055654));
#845=CARTESIAN_POINT('',(73.5410730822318,-19.9913251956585,71.4055926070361));
#846=CARTESIAN_POINT('',(97.6173074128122,-18.8086876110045,47.2027302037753));
#847=CARTESIAN_POINT('',(75.4863709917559,-13.2741897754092,49.4028447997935));
#848=CARTESIAN_POINT('',(73.2129805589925,-21.1597735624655,70.8040953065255));
#849=CARTESIAN_POINT('',(96.9154985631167,-20.3369962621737,46.5548369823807));
#850=CARTESIAN_POINT('',(75.2860501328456,-14.6161424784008,49.0525676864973));
#851=CARTESIAN_POINT('',(72.6866239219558,-22.8791207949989,69.8322554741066));
#852=CARTESIAN_POINT('',(96.6740050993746,-20.8414087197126,46.3311836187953));
#853=CARTESIAN_POINT('',(75.2142664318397,-15.0660312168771,48.9279746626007));
#854=CARTESIAN_POINT('',(72.5055038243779,-23.4465848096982,69.496775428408));
#855=CARTESIAN_POINT('',(96.176700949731,-21.8400740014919,45.8688762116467));
#856=CARTESIAN_POINT('',(75.0596544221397,-15.9727381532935,48.6613404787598));
#857=CARTESIAN_POINT('',(72.1325257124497,-24.5700832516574,68.8033143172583));
#858=CARTESIAN_POINT('',(95.9208913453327,-22.3343275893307,45.630223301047));
#859=CARTESIAN_POINT('',(74.9769046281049,-16.4294148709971,48.5194259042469));
#860=CARTESIAN_POINT('',(71.9406685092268,-25.1261185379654,68.4453349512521));
#861=CARTESIAN_POINT('',(95.6583591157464,-22.8233635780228,45.3842932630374));
#862=CARTESIAN_POINT('',(74.8881430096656,-16.890385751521,48.3679358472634));
#863=CARTESIAN_POINT('',(71.7437693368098,-25.6762840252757,68.0764398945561));
#864=(BOUNDED_SURFACE() B_SPLINE_SURFACE(3,2,((#414,#415,#416),(#417,#418,#419),(#420,#421,
#422),(#423,#424,#425),(#426,#427,#428),(#429,#430,#431),(#432,#433,#434),(#435,#436,#437),
(#438,#439,#440),(#441,#442,#443),(#444,#445,#446),(#447,#448,#449),(#450,#451,#452),(#453,#454,
#455),(#456,#457,#458),(#459,#460,#461),(#462,#463,#464),(#465,#466,#467),(#468,#469,#470),
(#471,#472,#473),(#474,#475,#476),(#477,#478,#479),(#480,#481,#482),(#483,#484,#485),(#486,#487,
#488),(#489,#490,#491),(#492,#493,#494),(#495,#496,#497),(#498,#499,#500),(#501,#502,#503),
(#504,#505,#506),(#507,#508,#509),(#510,#511,#512),(#513,#514,#515),(#516,#517,#518),(#519,#520,
#521),(#522,#523,#524),(#525,#526,#527),(#528,#529,#530),(#531,#532,#533),(#534,#535,#536),
(#537,#538,#539),(#540,#541,#542),(#543,#544,#545),(#546,#547,#548),(#549,#550,#551),(#552,#553,
#554),(#555,#556,#557),(#558,#559,#560),(#561,#562,#563),(#564,#565,#566),(#567,#568,#569),
(#570,#571,#572),(#573,#574,#575),(#576,#577,#578),(#579,#580,#581),(#582,#583,#584),(#585,#586,
#587),(#588,#589,#590),(#591,#592,#593),(#594,#595,#596),(#597,#598,#599),(#600,#601,#602),
(#603,#604,#605),(#606,#607,#608),(#609,#610,#611),(#612,#613,#614),(#615,#616,#617),(#618,#619,
#620),(#621,#622,#623),(#624,#625,#626),(#627,#628,#629),(#630,#631,#632),(#633,#634,#635),
(#636,#637,#638),(#639,#640,#641),(#642,#643,#644),(#645,#646,#647),(#648,#649,#650),(#651,#652,
#653),(#654,#655,#656),(#657,#658,#659),(#660,#661,#662),(#663,#664,#665),(#666,#667,#668),
(#669,#670,#671),(#672,#673,#674),(#675,#676,#677),(#678,#679,#680),(#681,#682,#683),(#684,#685,
#686),(#687,#688,#689),(#690,#691,#692),(#693,#694,#695),(#696,#697,#698),(#699,#700,#701),
(#702,#703,#704),(#705,#706,#707),(#708,#709,#710),(#711,#712,#713),(#714,#715,#716),(#717,#718,
#719),(#720,#721,#722),(#723,#724,#725),(#726,#727,#728),(#729,#730,#731),(#732,#733,#734),
(#735,#736,#737),(#738,#739,#740),(#741,#742,#743),(#744,#745,#746),(#747,#748,#749),(#750,#751,
#752),(#753,#754,#755),(#756,#757,#758),(#759,#760,#761),(#762,#763,#764),(#765,#766,#767),
(#768,#769,#770),(#771,#772,#773),(#774,#775,#776),(#777,#778,#779),(#780,#781,#782),(#783,#784,
#785),(#786,#787,#788),(#789,#790,#791),(#792,#793,#794),(#795,#796,#797),(#798,#799,#800),
(#801,#802,#803),(#804,#805,#806),(#807,#808,#809),(#810,#811,#812),(#813,#814,#815),(#816,#817,
#818),(#819,#820,#821),(#822,#823,#824),(#825,#826,#827),(#828,#829,#830),(#831,#832,#833),
(#834,#835,#836),(#837,#838,#839),(#840,#841,#842),(#843,#844,#845),(#846,#847,#848),(#849,#850,
#851),(#852,#853,#854),(#855,#856,#857),(#858,#859,#860),(#861,#862,#863)),.UNSPECIFIED.,.F.,
.F.,.F.) B_SPLINE_SURFACE_WITH_KNOTS((4,2,2,2,2,2,2,2,2,2,2,2,2,2,2,2,2,2,2,2,2,2,2,2,2,2,2,2,2,
2,2,2,2,2,2,2,2,2,2,2,2,2,2,2,2,2,2,2,2,2,2,2,2,2,2,2,2,2,2,2,2,2,2,2,2,2,2,2,2,2,2,2,2,2,4),(3,
3),(0.,2.92928734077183,5.85888262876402,11.7218095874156,17.6096173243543,23.4957956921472,
29.41558780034,35.3358745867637,41.2393728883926,47.1421495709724,52.3683943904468,
57.5941964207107,62.8246971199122,68.0554450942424,73.4115344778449,78.7676440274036,
84.1223570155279,89.477770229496,92.5895909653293,95.7007977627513,101.923323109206,
108.157334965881,114.39162718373,118.112926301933,121.833968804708,125.556606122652,
129.278829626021,132.996267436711,136.713838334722,144.142116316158,149.223660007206,
154.304298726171,156.838351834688,159.372066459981,161.905930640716,164.439799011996,
166.99684976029,169.553904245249,172.110986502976,174.668071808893,177.229277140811,
179.790827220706,182.352186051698,184.913857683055,189.972260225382,195.030483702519,
200.092398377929,205.155042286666,208.933866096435,212.713007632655,216.493136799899,
220.273644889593,227.844127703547,235.413575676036,243.040145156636,250.667664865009,
254.473912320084,258.279916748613,262.083922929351,265.888845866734,271.267867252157,
276.645621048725,279.332314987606,282.018515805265,284.705004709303,287.391621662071,
292.775807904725,298.160066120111,303.553782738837,308.947149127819,314.133986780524,
319.321619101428,324.495539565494,327.081584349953,329.667434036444),(0.,1.),
.UNSPECIFIED.) GEOMETRIC_REPRESENTATION_ITEM() RATIONAL_B_SPLINE_SURFACE(((1.,0.774907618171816,
1.),(1.,0.772323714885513,1.),(1.,0.769768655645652,1.),(1.,0.764732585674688,1.),(1.,
0.76225158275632,1.),(1.,0.754941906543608,1.),(1.,0.750249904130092,1.),(1.,0.741360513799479,
1.),(1.,0.737165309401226,1.),(1.,0.729444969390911,1.),(1.,0.725919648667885,1.),(1.,
0.719663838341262,1.),(1.,0.716938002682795,1.),(1.,0.712432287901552,1.),(1.,0.710652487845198,
1.),(1.,0.708129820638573,1.),(1.,0.707384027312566,1.),(1.,0.706957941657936,1.),(1.,
0.707277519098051,1.),(1.,0.708868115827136,1.),(1.,0.710025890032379,1.),(1.,0.713117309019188,
1.),(1.,0.715050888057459,1.),(1.,0.719624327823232,1.),(1.,0.722264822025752,1.),(1.,
0.728160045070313,1.),(1.,0.731414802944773,1.),(1.,0.738520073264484,1.),(1.,0.74238299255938,
1.),(1.,0.75053095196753,1.),(1.,0.754815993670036,1.),(1.,0.76369513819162,1.),(1.,
0.768289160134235,1.),(1.,0.777683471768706,1.),(1.,0.782483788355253,1.),(1.,0.790159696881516,
1.),(1.,0.792999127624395,1.),(1.,0.798697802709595,1.),(1.,0.801557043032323,1.),(1.,
0.81014200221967,1.),(1.,0.815874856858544,1.),(1.,0.827253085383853,1.),(1.,0.832898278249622,
1.),(1.,0.843993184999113,1.),(1.,0.849442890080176,1.),(1.,0.857918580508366,1.),(1.,
0.861036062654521,1.),(1.,0.867153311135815,1.),(1.,0.870153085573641,1.),(1.,0.876019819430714,
1.),(1.,0.878886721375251,1.),(1.,0.884470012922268,1.),(1.,0.887186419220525,1.),(1.,
0.892449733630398,1.),(1.,0.894996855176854,1.),(1.,0.899908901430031,1.),(1.,0.902273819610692,
1.),(1.,0.909067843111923,1.),(1.,0.913201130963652,1.),(1.,0.919372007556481,1.),(1.,
0.921659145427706,1.),(1.,0.925748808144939,1.),(1.,0.927551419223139,1.),(1.,0.929855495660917,
1.),(1.,0.930556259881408,1.),(1.,0.931821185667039,1.),(1.,0.932385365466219,1.),(1.,
0.933372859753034,1.),(1.,0.933796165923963,1.),(1.,0.934498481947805,1.),(1.,0.934777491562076,
1.),(1.,0.935190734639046,1.),(1.,0.935323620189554,1.),(1.,0.935438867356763,1.),(1.,
0.9354212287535,1.),(1.,0.935235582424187,1.),(1.,0.935067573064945,1.),(1.,0.934582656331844,
1.),(1.,0.934265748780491,1.),(1.,0.933485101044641,1.),(1.,0.933021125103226,1.),(1.,
0.931950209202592,1.),(1.,0.931343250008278,1.),(1.,0.929991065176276,1.),(1.,0.929245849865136,
1.),(1.,0.927622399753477,1.),(1.,0.926744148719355,1.),(1.,0.923941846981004,1.),(1.,
0.921832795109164,1.),(1.,0.917164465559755,1.),(1.,0.914605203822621,1.),(1.,0.909080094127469,
1.),(1.,0.906113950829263,1.),(1.,0.899819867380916,1.),(1.,0.896491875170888,1.),(1.,
0.890401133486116,1.),(1.,0.887709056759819,1.),(1.,0.882163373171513,1.),(1.,0.879309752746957,
1.),(1.,0.873457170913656,1.),(1.,0.870458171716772,1.),(1.,0.864332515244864,1.),(1.,
0.861205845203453,1.),(1.,0.851651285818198,1.),(1.,0.845056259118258,1.),(1.,0.831578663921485,
1.),(1.,0.824696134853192,1.),(1.,0.810769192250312,1.),(1.,0.803723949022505,1.),(1.,
0.789739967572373,1.),(1.,0.782801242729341,1.),(1.,0.7726823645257,1.),(1.,0.769360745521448,
1.),(1.,0.762847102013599,1.),(1.,0.759655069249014,1.),(1.,0.753440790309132,1.),(1.,
0.750418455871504,1.),(1.,0.744581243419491,1.),(1.,0.741766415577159,1.),(1.,0.735272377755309,
1.),(1.,0.731717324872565,1.),(1.,0.725219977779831,1.),(1.,0.722277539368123,1.),(1.,
0.718402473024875,1.),(1.,0.717200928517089,1.),(1.,0.714987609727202,1.),(1.,0.713975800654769,
1.),(1.,0.712151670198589,1.),(1.,0.711339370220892,1.),(1.,0.70992238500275,1.),(1.,
0.709317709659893,1.),(1.,0.707823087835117,1.),(1.,0.707256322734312,1.),(1.,0.707009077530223,
1.),(1.,0.707328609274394,1.),(1.,0.708841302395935,1.),(1.,0.710035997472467,1.),(1.,
0.713251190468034,1.),(1.,0.715271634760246,1.),(1.,0.719966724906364,1.),(1.,0.722613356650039,
1.),(1.,0.728507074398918,1.),(1.,0.731754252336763,1.),(1.,0.738739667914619,1.),(1.,
0.7424765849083,1.),(1.,0.748375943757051,1.),(1.,0.750391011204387,1.),(1.,0.754506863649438,
1.),(1.,0.756607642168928,1.),(1.,0.75874520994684,1.))) REPRESENTATION_ITEM('') SURFACE());
#865=CARTESIAN_POINT('',(70.2230556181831,-29.5831448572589,-65.1965921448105));
#866=CARTESIAN_POINT('',(70.4714068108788,-28.9936222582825,-65.6721356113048));
#867=CARTESIAN_POINT('',(70.7144033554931,-28.3960534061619,-66.1347646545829));
#868=CARTESIAN_POINT('',(71.1887161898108,-27.1851004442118,-67.0333018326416));
#869=CARTESIAN_POINT('',(71.4200312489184,-26.5717146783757,-67.46920715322));
#870=CARTESIAN_POINT('',(72.0952075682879,-24.7076443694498,-68.7358913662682));
#871=CARTESIAN_POINT('',(72.5199806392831,-23.4337996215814,-69.525029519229));
#872=CARTESIAN_POINT('',(73.3119198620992,-20.8247230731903,-70.9862477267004));
#873=CARTESIAN_POINT('',(73.6788338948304,-19.4892537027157,-71.6578168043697));
#874=CARTESIAN_POINT('',(74.345063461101,-16.7693426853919,-72.8708681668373));
#875=CARTESIAN_POINT('',(74.6443976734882,-15.3849146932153,-73.412386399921));
#876=CARTESIAN_POINT('',(75.1701621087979,-12.5678622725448,-74.3600050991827));
#877=CARTESIAN_POINT('',(75.396166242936,-11.1350077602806,-74.7653145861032));
#878=CARTESIAN_POINT('',(75.7672507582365,-8.23975315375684,-75.4292770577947));
#879=CARTESIAN_POINT('',(75.9123243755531,-6.77735060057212,-75.6879177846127));
#880=CARTESIAN_POINT('',(76.1173726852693,-3.84014576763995,-76.0531411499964));
#881=CARTESIAN_POINT('',(76.1775875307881,-2.36539041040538,-76.1601529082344));
#882=CARTESIAN_POINT('',(76.2120335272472,0.586797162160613,-76.2213951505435));
#883=CARTESIAN_POINT('',(76.1862751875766,2.06422902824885,-76.1756443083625));
#884=CARTESIAN_POINT('',(76.0573845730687,4.83912430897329,-75.9463070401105));
#885=CARTESIAN_POINT('',(75.9634586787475,6.13780677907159,-75.7791192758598));
#886=CARTESIAN_POINT('',(75.7108210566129,8.71725521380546,-75.3283017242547));
#887=CARTESIAN_POINT('',(75.5521148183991,9.99802268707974,-75.0446818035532));
#888=CARTESIAN_POINT('',(75.1729594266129,12.5344426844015,-74.3646917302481));
#889=CARTESIAN_POINT('',(74.9524548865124,13.7900715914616,-73.968220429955));
#890=CARTESIAN_POINT('',(74.4539940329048,16.2677563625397,-73.0677810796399));
#891=CARTESIAN_POINT('',(74.1760350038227,17.4898106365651,-72.5638079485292));
#892=CARTESIAN_POINT('',(73.5603631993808,19.9229884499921,-71.4409660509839));
#893=CARTESIAN_POINT('',(73.2213781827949,21.1331483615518,-70.8196334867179));
#894=CARTESIAN_POINT('',(72.4943006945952,23.5065305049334,-69.4771254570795));
#895=CARTESIAN_POINT('',(72.1062080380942,24.6697525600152,-68.7559496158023));
#896=CARTESIAN_POINT('',(71.2872490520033,26.9449397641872,-67.2206074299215));
#897=CARTESIAN_POINT('',(70.8563939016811,28.0569181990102,-66.4064653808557));
#898=CARTESIAN_POINT('',(69.9580915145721,30.2272194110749,-64.6911186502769));
#899=CARTESIAN_POINT('',(69.4906395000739,31.2855351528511,-63.7899025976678));
#900=CARTESIAN_POINT('',(68.7278814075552,32.9143657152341,-62.3009741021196));
#901=CARTESIAN_POINT('',(68.4424991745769,33.5034944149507,-61.7400951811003));
#902=CARTESIAN_POINT('',(67.8629081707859,34.6624496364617,-60.5920143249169));
#903=CARTESIAN_POINT('',(67.5687011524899,35.2322799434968,-60.0048176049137));
#904=CARTESIAN_POINT('',(66.6745621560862,36.9127701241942,-58.2047749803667));
#905=CARTESIAN_POINT('',(66.0631223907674,37.9944077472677,-56.9534963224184));
#906=CARTESIAN_POINT('',(64.8190199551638,40.0800747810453,-54.3528092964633));
#907=CARTESIAN_POINT('',(64.1863201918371,41.0839572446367,-53.003224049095));
#908=CARTESIAN_POINT('',(62.911363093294,43.0108636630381,-50.2122019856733));
#909=CARTESIAN_POINT('',(62.2691053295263,43.9338839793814,-48.7707610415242));
#910=CARTESIAN_POINT('',(61.2452737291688,45.3418163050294,-46.3984921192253));
#911=CARTESIAN_POINT('',(60.8629763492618,45.8533510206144,-45.4960499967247));
#912=CARTESIAN_POINT('',(60.1017871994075,46.8466272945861,-43.6600330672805));
#913=CARTESIAN_POINT('',(59.722895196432,47.3283709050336,-42.7264604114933));
#914=CARTESIAN_POINT('',(58.9711784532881,48.2617796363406,-40.8280526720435));
#915=CARTESIAN_POINT('',(58.5983563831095,48.713431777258,-39.8632043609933));
#916=CARTESIAN_POINT('',(57.8620586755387,49.5857631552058,-37.9029210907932));
#917=CARTESIAN_POINT('',(57.4985820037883,50.006445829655,-36.9074895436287));
#918=CARTESIAN_POINT('',(56.7847225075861,50.8156068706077,-34.8873253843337));
#919=CARTESIAN_POINT('',(56.4343234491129,51.2041259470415,-33.8626320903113));
#920=CARTESIAN_POINT('',(55.749830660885,51.9485549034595,-31.7830760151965));
#921=CARTESIAN_POINT('',(55.4157375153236,52.3044636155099,-30.7282121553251));
#922=CARTESIAN_POINT('',(54.444138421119,53.3212206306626,-27.5196863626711));
#923=CARTESIAN_POINT('',(53.8366404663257,53.9318498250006,-25.3202273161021));
#924=CARTESIAN_POINT('',(52.9119287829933,54.8365312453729,-21.5221643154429));
#925=CARTESIAN_POINT('',(52.5636399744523,55.1696524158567,-19.953255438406));
#926=CARTESIAN_POINT('',(51.9339234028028,55.7628461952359,-16.7672081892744));
#927=CARTESIAN_POINT('',(51.6524837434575,56.0229318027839,-15.1500784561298));
#928=CARTESIAN_POINT('',(51.2898182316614,56.3544233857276,-12.6974314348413));
#929=CARTESIAN_POINT('',(51.1789459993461,56.455059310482,-11.8764233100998));
#930=CARTESIAN_POINT('',(50.9780995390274,56.6364878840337,-10.2260432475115));
#931=CARTESIAN_POINT('',(50.8881225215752,56.7172831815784,-9.39667244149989));
#932=CARTESIAN_POINT('',(50.7302092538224,56.85857097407,-7.7311010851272));
#933=CARTESIAN_POINT('',(50.662274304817,56.919062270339,-6.89490013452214));
#934=CARTESIAN_POINT('',(50.5493602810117,57.0193641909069,-5.21753428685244));
#935=CARTESIAN_POINT('',(50.5043812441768,57.0591747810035,-4.37636938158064));
#936=CARTESIAN_POINT('',(50.4377058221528,57.1181218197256,-2.68337242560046));
#937=CARTESIAN_POINT('',(50.4162262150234,57.1370657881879,-1.8315131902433));
#938=CARTESIAN_POINT('',(50.3975997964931,57.1534958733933,-0.126951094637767));
#939=CARTESIAN_POINT('',(50.4004530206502,57.1509819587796,0.725751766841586));
#940=CARTESIAN_POINT('',(50.4304506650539,57.1245134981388,2.42981078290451));
#941=CARTESIAN_POINT('',(50.4575953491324,57.1005587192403,3.2811669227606));
#942=CARTESIAN_POINT('',(50.5357824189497,57.0313721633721,4.98037482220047));
#943=CARTESIAN_POINT('',(50.5868248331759,56.986140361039,5.82822657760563));
#944=CARTESIAN_POINT('',(50.7121879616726,56.87460795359,7.519764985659));
#945=CARTESIAN_POINT('',(50.7865460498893,56.8082735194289,8.3634427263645));
#946=CARTESIAN_POINT('',(50.957515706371,56.6549623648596,10.0435174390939));
#947=CARTESIAN_POINT('',(51.0541302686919,56.5679828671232,10.8799134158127));
#948=CARTESIAN_POINT('',(51.268364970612,56.3738914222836,12.5436466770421));
#949=CARTESIAN_POINT('',(51.3859835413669,56.2667809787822,13.3709846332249));
#950=CARTESIAN_POINT('',(51.6408253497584,56.0329814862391,15.0153454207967));
#951=CARTESIAN_POINT('',(51.778050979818,55.9062900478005,15.8323669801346));
#952=CARTESIAN_POINT('',(52.2132250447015,55.5011275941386,18.2458704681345));
#953=CARTESIAN_POINT('',(52.5374655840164,55.1950741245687,19.8259305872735));
#954=CARTESIAN_POINT('',(53.2443177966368,54.5135139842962,22.9347095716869));
#955=CARTESIAN_POINT('',(53.6269274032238,54.1380097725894,24.4634302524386));
#956=CARTESIAN_POINT('',(54.4390169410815,53.3213391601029,27.4677777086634));
#957=CARTESIAN_POINT('',(54.8685308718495,52.8801250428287,28.9433649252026));
#958=CARTESIAN_POINT('',(55.7633876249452,51.9356114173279,31.8389627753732));
#959=CARTESIAN_POINT('',(56.2287355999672,51.4323029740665,33.258965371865));
#960=CARTESIAN_POINT('',(57.064129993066,50.5015943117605,35.6894401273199));
#961=CARTESIAN_POINT('',(57.4284188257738,50.0873106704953,36.7124487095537));
#962=CARTESIAN_POINT('',(58.16794491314,49.2265387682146,38.726996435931));
#963=CARTESIAN_POINT('',(58.5431830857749,48.7800478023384,39.7185329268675));
#964=CARTESIAN_POINT('',(59.3013466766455,47.8554881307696,41.6701170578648));
#965=CARTESIAN_POINT('',(59.6842740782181,47.3774112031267,42.6301564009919));
#966=CARTESIAN_POINT('',(60.4546842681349,46.3903374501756,44.5182413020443));
#967=CARTESIAN_POINT('',(60.842167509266,45.8813375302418,45.4462836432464));
#968=CARTESIAN_POINT('',(62.0082423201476,44.3071490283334,48.1844248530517));
#969=CARTESIAN_POINT('',(62.789495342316,43.1959313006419,49.946093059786));
#970=CARTESIAN_POINT('',(64.3376620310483,40.8543266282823,53.3338427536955));
#971=CARTESIAN_POINT('',(65.1045776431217,39.6239559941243,54.9599427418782));
#972=CARTESIAN_POINT('',(66.6108144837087,37.0364353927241,58.0802629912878));
#973=CARTESIAN_POINT('',(67.3498838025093,35.6783987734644,59.5733954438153));
#974=CARTESIAN_POINT('',(68.7755911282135,32.8461594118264,62.4020113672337));
#975=CARTESIAN_POINT('',(69.4622225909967,31.3719422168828,63.7374751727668));
#976=CARTESIAN_POINT('',(70.4377591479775,29.0800728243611,65.6085709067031));
#977=CARTESIAN_POINT('',(70.753584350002,28.3034991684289,66.2097239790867));
#978=CARTESIAN_POINT('',(71.3652105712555,26.7238406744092,67.3666004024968));
#979=CARTESIAN_POINT('',(71.6610128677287,25.9207575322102,67.9223266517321));
#980=CARTESIAN_POINT('',(72.2301606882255,24.2897012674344,68.985751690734));
#981=CARTESIAN_POINT('',(72.5035179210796,23.4617414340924,69.4934755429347));
#982=CARTESIAN_POINT('',(73.0257918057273,21.7818217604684,70.4589607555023));
#983=CARTESIAN_POINT('',(73.2747025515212,20.9298561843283,70.9167100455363));
#984=CARTESIAN_POINT('',(73.8433665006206,18.8466485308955,71.9583079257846));
#985=CARTESIAN_POINT('',(74.1498266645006,17.6043118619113,72.515980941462));
#986=CARTESIAN_POINT('',(74.7037194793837,15.081798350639,73.519681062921));
#987=CARTESIAN_POINT('',(74.9511660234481,13.8016304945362,73.9657344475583));
#988=CARTESIAN_POINT('',(75.274311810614,11.8595476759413,74.5464963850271));
#989=CARTESIAN_POINT('',(75.3739922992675,11.2088171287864,74.7253092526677));
#990=CARTESIAN_POINT('',(75.5569153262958,9.90092288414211,75.0530091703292));
#991=CARTESIAN_POINT('',(75.6401608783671,9.24376038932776,75.2019017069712));
#992=CARTESIAN_POINT('',(75.7897863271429,7.92397357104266,75.4692422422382));
#993=CARTESIAN_POINT('',(75.8561644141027,7.26134866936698,75.5876869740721));
#994=CARTESIAN_POINT('',(75.9716908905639,5.93192058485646,75.7936719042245));
#995=CARTESIAN_POINT('',(76.0208384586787,5.26511720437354,75.8812106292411));
#996=CARTESIAN_POINT('',(76.1421631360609,3.25726478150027,76.097213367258));
#997=CARTESIAN_POINT('',(76.1879145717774,1.91147250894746,76.1785156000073));
#998=CARTESIAN_POINT('',(76.2078956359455,-0.781414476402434,76.214035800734));
#999=CARTESIAN_POINT('',(76.1821243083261,-2.12850920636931,76.1682520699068));
#1000=CARTESIAN_POINT('',(76.0595674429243,-4.81607842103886,75.9501971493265));
#1001=CARTESIAN_POINT('',(75.9626572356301,-6.15653711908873,75.7777039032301));
#1002=CARTESIAN_POINT('',(75.6998544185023,-8.81819355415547,75.3087169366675));
#1003=CARTESIAN_POINT('',(75.5339662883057,-10.139392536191,75.0122312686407));
#1004=CARTESIAN_POINT('',(75.1444059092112,-12.7033456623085,74.313375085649));
#1005=CARTESIAN_POINT('',(74.9231896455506,-13.9471663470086,73.9154939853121));
#1006=CARTESIAN_POINT('',(74.4244218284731,-16.4016548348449,73.0142038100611));
#1007=CARTESIAN_POINT('',(74.1468616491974,-17.6123175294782,72.5107785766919));
#1008=CARTESIAN_POINT('',(73.5410730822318,-19.9913251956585,71.4055926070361));
#1009=CARTESIAN_POINT('',(73.2129805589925,-21.1597735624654,70.8040953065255));
#1010=CARTESIAN_POINT('',(72.6866239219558,-22.8791207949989,69.8322554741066));
#1011=CARTESIAN_POINT('',(72.5055038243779,-23.4465848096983,69.4967754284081));
#1012=CARTESIAN_POINT('',(72.1325257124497,-24.5700832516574,68.8033143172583));
#1013=CARTESIAN_POINT('',(71.9406685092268,-25.1261185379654,68.4453349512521));
#1014=CARTESIAN_POINT('',(71.7437693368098,-25.6762840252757,68.0764398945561));
#1015=B_SPLINE_CURVE_WITH_KNOTS('',3,(#865,#866,#867,#868,#869,#870,#871,#872,#873,#874,#875,
#876,#877,#878,#879,#880,#881,#882,#883,#884,#885,#886,#887,#888,#889,#890,#891,#892,#893,#894,
#895,#896,#897,#898,#899,#900,#901,#902,#903,#904,#905,#906,#907,#908,#909,#910,#911,#912,#913,
#914,#915,#916,#917,#918,#919,#920,#921,#922,#923,#924,#925,#926,#927,#928,#929,#930,#931,#932,
#933,#934,#935,#936,#937,#938,#939,#940,#941,#942,#943,#944,#945,#946,#947,#948,#949,#950,#951,
#952,#953,#954,#955,#956,#957,#958,#959,#960,#961,#962,#963,#964,#965,#966,#967,#968,#969,#970,
#971,#972,#973,#974,#975,#976,#977,#978,#979,#980,#981,#982,#983,#984,#985,#986,#987,#988,#989,
#990,#991,#992,#993,#994,#995,#996,#997,#998,#999,#1000,#1001,#1002,#1003,#1004,#1005,#1006,
#1007,#1008,#1009,#1010,#1011,#1012,#1013,#1014),.UNSPECIFIED.,.F.,.F.,(4,2,2,2,2,2,2,2,2,2,2,2,
2,2,2,2,2,2,2,2,2,2,2,2,2,2,2,2,2,2,2,2,2,2,2,2,2,2,2,2,2,2,2,2,2,2,2,2,2,2,2,2,2,2,2,2,2,2,2,2,
2,2,2,2,2,2,2,2,2,2,2,2,2,2,4),(0.,2.92928734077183,5.85888262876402,11.7218095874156,
17.6096173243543,23.4957956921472,29.41558780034,35.3358745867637,41.2393728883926,
47.1421495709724,52.3683943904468,57.5941964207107,62.8246971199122,68.0554450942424,
73.4115344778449,78.7676440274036,84.1223570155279,89.477770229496,92.5895909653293,
95.7007977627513,101.923323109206,108.157334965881,114.39162718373,118.112926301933,
121.833968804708,125.556606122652,129.278829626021,132.996267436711,136.713838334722,
144.142116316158,149.223660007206,154.304298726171,156.838351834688,159.372066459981,
161.905930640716,164.439799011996,166.99684976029,169.553904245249,172.110986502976,
174.668071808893,177.229277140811,179.790827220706,182.352186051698,184.913857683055,
189.972260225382,195.030483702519,200.092398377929,205.155042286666,208.933866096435,
212.713007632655,216.493136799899,220.273644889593,227.844127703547,235.413575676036,
243.040145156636,250.667664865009,254.473912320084,258.279916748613,262.083922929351,
265.888845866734,271.267867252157,276.645621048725,279.332314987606,282.018515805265,
284.705004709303,287.391621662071,292.775807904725,298.160066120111,303.553782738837,
308.947149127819,314.133986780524,319.321619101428,324.495539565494,327.081584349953,
329.667434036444),.UNSPECIFIED.);
#1016=EDGE_CURVE('E222',#40,#137,#1015,.T.);
#1017=ORIENTED_EDGE('',*,*,#1016,.T.);
#1018=ORIENTED_EDGE('',*,*,#140,.T.);
#1019=ORIENTED_EDGE('',*,*,#403,.T.);
#1020=ORIENTED_EDGE('',*,*,#355,.T.);
#1021=CARTESIAN_POINT('',(-93.6307408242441,-26.2961287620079,43.464394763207));
#1022=CARTESIAN_POINT('',(-74.1399881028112,-20.285317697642,47.1009589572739));
#1023=CARTESIAN_POINT('',(-70.2230556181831,-29.5831448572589,65.1965921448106));
#1024=CARTESIAN_POINT('',(-93.9618757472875,-25.7721086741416,43.7814237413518));
#1025=CARTESIAN_POINT('',(-74.2726745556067,-19.7514888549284,47.3246044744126));
#1026=CARTESIAN_POINT('',(-70.4714068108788,-28.9936222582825,65.6721356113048));
#1027=CARTESIAN_POINT('',(-94.2858711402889,-25.2409363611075,44.0898431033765));
#1028=CARTESIAN_POINT('',(-74.3972791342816,-19.2212058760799,47.5349200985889));
#1029=CARTESIAN_POINT('',(-70.7144033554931,-28.3960534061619,66.134764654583));
#1030=CARTESIAN_POINT('',(-94.9182882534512,-24.1645337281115,44.6888678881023));
#1031=CARTESIAN_POINT('',(-74.6316958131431,-18.1655703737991,47.9315837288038));
#1032=CARTESIAN_POINT('',(-71.1887161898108,-27.1851004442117,67.0333018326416));
#1033=CARTESIAN_POINT('',(-95.2267083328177,-23.6193019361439,44.9794714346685));
#1034=CARTESIAN_POINT('',(-74.7413855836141,-17.6403546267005,48.1177318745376));
#1035=CARTESIAN_POINT('',(-71.4200312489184,-26.5717146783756,67.4692071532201));
#1036=CARTESIAN_POINT('',(-96.1269434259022,-21.9623505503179,45.8239275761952));
#1037=CARTESIAN_POINT('',(-75.0497239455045,-16.0692325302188,48.6433074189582));
#1038=CARTESIAN_POINT('',(-72.0952075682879,-24.7076443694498,68.7358913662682));
#1039=CARTESIAN_POINT('',(-96.6933075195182,-20.8300441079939,46.350019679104));
#1040=CARTESIAN_POINT('',(-75.2247819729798,-15.0396446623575,48.9450593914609));
#1041=CARTESIAN_POINT('',(-72.5199806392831,-23.4337996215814,69.5250295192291));
#1042=CARTESIAN_POINT('',(-97.7492264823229,-18.5108649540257,47.3241651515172));
#1043=CARTESIAN_POINT('',(-75.522644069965,-13.0160027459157,49.4667083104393));
#1044=CARTESIAN_POINT('',(-73.3119198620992,-20.8247230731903,70.9862477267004));
#1045=CARTESIAN_POINT('',(-98.2384451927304,-17.3237810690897,47.7718778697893));
#1046=CARTESIAN_POINT('',(-75.6443632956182,-12.0240755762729,49.6848638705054));
#1047=CARTESIAN_POINT('',(-73.6788338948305,-19.4892537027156,71.6578168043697));
#1048=CARTESIAN_POINT('',(-99.1267512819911,-14.9060823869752,48.5805787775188));
#1049=CARTESIAN_POINT('',(-75.8431772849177,-10.088454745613,50.0503528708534));
#1050=CARTESIAN_POINT('',(-74.345063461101,-16.7693426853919,72.8708681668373));
#1051=CARTESIAN_POINT('',(-99.5258635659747,-13.6754797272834,48.9415909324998));
#1052=CARTESIAN_POINT('',(-75.9196275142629,-9.14703767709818,50.1966175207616));
#1053=CARTESIAN_POINT('',(-74.6443976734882,-15.3849146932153,73.412386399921));
#1054=CARTESIAN_POINT('',(-100.226882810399,-11.1714331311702,49.5733367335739));
#1055=CARTESIAN_POINT('',(-76.0393037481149,-7.30766902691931,50.4339673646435));
#1056=CARTESIAN_POINT('',(-75.1701621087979,-12.5678622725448,74.3600050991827));
#1057=CARTESIAN_POINT('',(-100.528221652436,-9.89778467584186,49.8435430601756));
#1058=CARTESIAN_POINT('',(-76.0819012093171,-6.4125807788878,50.5239618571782));
#1059=CARTESIAN_POINT('',(-75.396166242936,-11.1350077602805,74.7653145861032));
#1060=CARTESIAN_POINT('',(-101.023001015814,-7.32422502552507,50.2861847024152));
#1061=CARTESIAN_POINT('',(-76.1446504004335,-4.66354973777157,50.6623263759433));
#1062=CARTESIAN_POINT('',(-75.7672507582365,-8.2397531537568,75.4292770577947));
#1063=CARTESIAN_POINT('',(-101.216432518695,-6.02431164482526,50.4586118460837));
#1064=CARTESIAN_POINT('',(-76.1645743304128,-3.81220123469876,50.710244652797));
#1065=CARTESIAN_POINT('',(-75.9123243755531,-6.77735060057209,75.6879177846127));
#1066=CARTESIAN_POINT('',(-101.489830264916,-3.41346290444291,50.7020940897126));
#1067=CARTESIAN_POINT('',(-76.191020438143,-2.13652781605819,50.7758098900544));
#1068=CARTESIAN_POINT('',(-76.1173726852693,-3.84014576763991,76.0531411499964));
#1069=CARTESIAN_POINT('',(-101.57011671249,-2.10256925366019,50.7734352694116));
#1070=CARTESIAN_POINT('',(-76.1974947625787,-1.31464606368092,50.7933403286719));
#1071=CARTESIAN_POINT('',(-76.1775875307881,-2.36539041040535,76.1601529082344));
#1072=CARTESIAN_POINT('',(-101.616044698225,0.52159747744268,50.8142634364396));
#1073=CARTESIAN_POINT('',(-76.2013505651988,0.326782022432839,50.8035840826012));
#1074=CARTESIAN_POINT('',(-76.2120335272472,0.586797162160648,76.2213951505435));
#1075=CARTESIAN_POINT('',(-101.581700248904,1.83487024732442,50.7837628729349));
#1076=CARTESIAN_POINT('',(-76.1987218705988,1.143855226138,50.7962700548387));
#1077=CARTESIAN_POINT('',(-76.1862751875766,2.06422902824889,76.1756443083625));
#1078=CARTESIAN_POINT('',(-101.409846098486,4.30144383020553,50.6308713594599));
#1079=CARTESIAN_POINT('',(-76.1833360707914,2.70420347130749,50.7566798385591));
#1080=CARTESIAN_POINT('',(-76.0573845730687,4.83912430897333,75.9463070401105));
#1081=CARTESIAN_POINT('',(-101.284611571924,5.4558282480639,50.5194128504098));
#1082=CARTESIAN_POINT('',(-76.1718127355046,3.44317417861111,50.7274576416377));
#1083=CARTESIAN_POINT('',(-75.9634586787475,6.13780677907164,75.7791192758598));
#1084=CARTESIAN_POINT('',(-100.94776140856,7.74867130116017,50.2188678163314));
#1085=CARTESIAN_POINT('',(-76.1350188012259,4.95090038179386,50.64111868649));
#1086=CARTESIAN_POINT('',(-75.7108210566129,8.7172552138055,75.3283017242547));
#1087=CARTESIAN_POINT('',(-100.736153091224,8.88713127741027,50.0297878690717));
#1088=CARTESIAN_POINT('',(-76.1098487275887,5.71788808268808,50.5842185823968));
#1089=CARTESIAN_POINT('',(-75.5521148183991,9.99802268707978,75.0446818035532));
#1090=CARTESIAN_POINT('',(-100.230612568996,11.1417268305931,49.57646115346));
#1091=CARTESIAN_POINT('',(-76.0383498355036,7.291465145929,50.4329882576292));
#1092=CARTESIAN_POINT('',(-75.1729594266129,12.5344426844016,74.3646917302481));
#1093=CARTESIAN_POINT('',(-99.9366065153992,12.257841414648,49.312146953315));
#1094=CARTESIAN_POINT('',(-75.9922056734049,8.09631019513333,50.3390087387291));
#1095=CARTESIAN_POINT('',(-74.9524548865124,13.7900715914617,73.968220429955));
#1096=CARTESIAN_POINT('',(-99.27199204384,14.4602278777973,48.7118540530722));
#1097=CARTESIAN_POINT('',(-75.8704172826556,9.74852173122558,50.1026706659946));
#1098=CARTESIAN_POINT('',(-74.4539940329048,16.2677563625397,73.0677810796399));
#1099=CARTESIAN_POINT('',(-98.9013800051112,15.5464983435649,48.3758719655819));
#1100=CARTESIAN_POINT('',(-75.7951116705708,10.5941607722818,49.9608981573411));
#1101=CARTESIAN_POINT('',(-74.1760350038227,17.4898106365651,72.5638079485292));
#1102=CARTESIAN_POINT('',(-98.0804842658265,17.7093230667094,47.6273107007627));
#1103=CARTESIAN_POINT('',(-75.604971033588,12.3465589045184,49.6142094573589));
#1104=CARTESIAN_POINT('',(-73.5603631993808,19.9229884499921,71.4409660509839));
#1105=CARTESIAN_POINT('',(-97.6285042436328,18.7850207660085,47.2130889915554));
#1106=CARTESIAN_POINT('',(-75.4897217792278,13.2528285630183,49.4086648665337));
#1107=CARTESIAN_POINT('',(-73.2213781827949,21.1331483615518,70.8196334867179));
#1108=CARTESIAN_POINT('',(-96.6590675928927,20.8946937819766,46.3180836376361));
#1109=CARTESIAN_POINT('',(-75.2135119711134,15.1009904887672,48.9257680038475));
#1110=CARTESIAN_POINT('',(-72.4943006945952,23.5065305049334,69.4771254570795));
#1111=CARTESIAN_POINT('',(-96.14161071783,21.9286689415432,45.8372997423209));
#1112=CARTESIAN_POINT('',(-75.0531991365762,16.0414648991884,48.6494606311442));
#1113=CARTESIAN_POINT('',(-72.1062080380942,24.6697525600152,68.7559496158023));
#1114=CARTESIAN_POINT('',(-95.0496654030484,23.9510575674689,44.8137382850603));
#1115=CARTESIAN_POINT('',(-74.682837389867,17.9474497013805,48.0177328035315));
#1116=CARTESIAN_POINT('',(-71.2872490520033,26.9449397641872,67.2206074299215));
#1117=CARTESIAN_POINT('',(-94.47519186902,24.9394828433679,44.2709769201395));
#1118=CARTESIAN_POINT('',(-74.473526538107,18.9118893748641,47.6635036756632));
#1119=CARTESIAN_POINT('',(-70.8563939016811,28.0569181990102,66.4064653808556));
#1120=CARTESIAN_POINT('',(-93.2774553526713,26.8686394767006,43.1274124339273));
#1121=CARTESIAN_POINT('',(-74.0036948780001,20.8541720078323,46.8710123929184));
#1122=CARTESIAN_POINT('',(-69.9580915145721,30.2272194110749,64.6911186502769));
#1123=CARTESIAN_POINT('',(-92.6541860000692,27.8093645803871,42.5266017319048));
#1124=CARTESIAN_POINT('',(-73.743905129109,21.831348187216,46.4339554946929));
#1125=CARTESIAN_POINT('',(-69.4906395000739,31.2855351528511,63.7899025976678));
#1126=CARTESIAN_POINT('',(-91.6371752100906,29.2572139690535,41.533982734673));
#1127=CARTESIAN_POINT('',(-73.2925742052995,23.3805888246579,45.6728469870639));
#1128=CARTESIAN_POINT('',(-68.7278814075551,32.9143657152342,62.3009741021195));
#1129=CARTESIAN_POINT('',(-91.2566655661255,29.7808839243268,41.160063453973));
#1130=CARTESIAN_POINT('',(-73.1188977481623,23.9484677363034,45.3796196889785));
#1131=CARTESIAN_POINT('',(-68.4424991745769,33.5034944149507,61.7400951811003));
#1132=CARTESIAN_POINT('',(-90.4838775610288,30.8110663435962,40.3946762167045));
#1133=CARTESIAN_POINT('',(-72.7554497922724,25.0818573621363,44.7641395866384));
#1134=CARTESIAN_POINT('',(-67.8629081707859,34.6624496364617,60.5920143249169));
#1135=CARTESIAN_POINT('',(-90.091601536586,31.3175821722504,40.0032117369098));
#1136=CARTESIAN_POINT('',(-72.5658056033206,25.6473549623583,44.4421152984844));
#1137=CARTESIAN_POINT('',(-67.5687011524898,35.2322799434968,60.0048176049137));
#1138=CARTESIAN_POINT('',(-88.8994162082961,32.8113512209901,38.8031833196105));
#1139=CARTESIAN_POINT('',(-71.9757956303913,27.3312759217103,43.4357994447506));
#1140=CARTESIAN_POINT('',(-66.6745621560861,36.9127701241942,58.2047749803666));
#1141=CARTESIAN_POINT('',(-88.0841631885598,33.7728068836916,37.9689975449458));
#1142=CARTESIAN_POINT('',(-71.5508246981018,28.44923397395,42.7053683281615));
#1143=CARTESIAN_POINT('',(-66.0631223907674,37.9944077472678,56.9534963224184));
#1144=CARTESIAN_POINT('',(-86.4253599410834,35.6267331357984,36.2352061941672));
#1145=CARTESIAN_POINT('',(-70.6468172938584,30.651467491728,41.1274961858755));
#1146=CARTESIAN_POINT('',(-64.8190199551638,40.0800747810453,54.3528092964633));
#1147=CARTESIAN_POINT('',(-85.5817602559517,36.5190731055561,35.3354826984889));
#1148=CARTESIAN_POINT('',(-70.1682942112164,31.7364544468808,40.2812198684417));
#1149=CARTESIAN_POINT('',(-64.1863201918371,41.0839572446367,53.003224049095));
#1150=CARTESIAN_POINT('',(-83.8818174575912,38.2318788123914,33.4748013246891));
#1151=CARTESIAN_POINT('',(-69.1693028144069,33.8554007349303,38.4756188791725));
#1152=CARTESIAN_POINT('',(-62.911363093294,43.0108636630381,50.2122019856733));
#1153=CARTESIAN_POINT('',(-83.0254737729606,39.0523413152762,32.5138406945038));
#1154=CARTESIAN_POINT('',(-68.6491497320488,34.8905138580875,37.5173486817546));
#1155=CARTESIAN_POINT('',(-62.2691053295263,43.9338839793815,48.7707610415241));
#1156=CARTESIAN_POINT('',(-81.6603649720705,40.3038367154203,30.9323280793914));
#1157=CARTESIAN_POINT('',(-67.7942821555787,36.4954618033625,35.8961117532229));
#1158=CARTESIAN_POINT('',(-61.2452737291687,45.3418163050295,46.3984921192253));
#1159=CARTESIAN_POINT('',(-81.1506351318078,40.7585342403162,30.3306999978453));
#1160=CARTESIAN_POINT('',(-67.4706093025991,37.0826786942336,35.2724288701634));
#1161=CARTESIAN_POINT('',(-60.8629763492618,45.8533510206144,45.4960499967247));
#1162=CARTESIAN_POINT('',(-80.1357162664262,41.641446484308,29.1066887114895));
#1163=CARTESIAN_POINT('',(-66.8167387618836,38.2315319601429,33.9871048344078));
#1164=CARTESIAN_POINT('',(-60.1017871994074,46.8466272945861,43.6600330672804));
#1165=CARTESIAN_POINT('',(-79.630526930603,42.0696630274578,28.484306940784));
#1166=CARTESIAN_POINT('',(-66.4864994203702,38.7935044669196,33.3255601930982));
#1167=CARTESIAN_POINT('',(-59.722895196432,47.3283709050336,42.7264604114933));
#1168=CARTESIAN_POINT('',(-78.6282379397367,42.8993596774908,27.2187017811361));
#1169=CARTESIAN_POINT('',(-65.8229457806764,39.8895557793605,31.9649705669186));
#1170=CARTESIAN_POINT('',(-58.9711784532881,48.2617796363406,40.8280526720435));
#1171=CARTESIAN_POINT('',(-78.1311418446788,43.3008282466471,26.5754695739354));
#1172=CARTESIAN_POINT('',(-65.4895475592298,40.4239793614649,31.2659485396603));
#1173=CARTESIAN_POINT('',(-58.5983563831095,48.713431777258,39.8632043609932));
#1174=CARTESIAN_POINT('',(-77.1494115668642,44.0762339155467,25.2686140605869));
#1175=CARTESIAN_POINT('',(-64.8237939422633,41.4621088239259,29.8315232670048));
#1176=CARTESIAN_POINT('',(-57.8620586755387,49.5857631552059,37.9029210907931));
#1177=CARTESIAN_POINT('',(-76.6647760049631,44.4501740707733,24.604993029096));
#1178=CARTESIAN_POINT('',(-64.4913196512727,41.966186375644,29.0961111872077));
#1179=CARTESIAN_POINT('',(-57.4985820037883,50.006445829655,36.9074895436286));
#1180=CARTESIAN_POINT('',(-75.7129633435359,45.1694283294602,23.2582169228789));
#1181=CARTESIAN_POINT('',(-63.8320550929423,42.9405651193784,27.5905497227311));
#1182=CARTESIAN_POINT('',(-56.7847225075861,50.8156068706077,34.8873253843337));
#1183=CARTESIAN_POINT('',(-75.245764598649,45.5147786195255,22.5750880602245));
#1184=CARTESIAN_POINT('',(-63.505107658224,43.4112800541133,26.8203826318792));
#1185=CARTESIAN_POINT('',(-56.4343234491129,51.2041259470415,33.8626320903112));
#1186=CARTESIAN_POINT('',(-74.3331075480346,46.1764932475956,21.1887173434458));
#1187=CARTESIAN_POINT('',(-62.8611537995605,44.3170251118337,25.2455069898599));
#1188=CARTESIAN_POINT('',(-55.749830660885,51.9485549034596,31.7830760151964));
#1189=CARTESIAN_POINT('',(-73.8876500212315,46.4928565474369,20.4854747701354));
#1190=CARTESIAN_POINT('',(-62.5439633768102,44.7524314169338,24.4406667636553));
#1191=CARTESIAN_POINT('',(-55.4157375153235,52.3044636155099,30.728212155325));
#1192=CARTESIAN_POINT('',(-72.5921845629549,47.3966405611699,18.3464575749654));
#1193=CARTESIAN_POINT('',(-61.6172755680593,45.9976088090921,21.9825015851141));
#1194=CARTESIAN_POINT('',(-54.444138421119,53.3212206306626,27.519686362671));
#1195=CARTESIAN_POINT('',(-71.7821872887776,47.9394220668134,16.8801515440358));
#1196=CARTESIAN_POINT('',(-61.0261728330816,46.7556599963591,20.2707136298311));
#1197=CARTESIAN_POINT('',(-53.8366404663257,53.9318498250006,25.320227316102));
#1198=CARTESIAN_POINT('',(-70.5492383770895,48.7435833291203,14.3481095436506));
#1199=CARTESIAN_POINT('',(-60.1176428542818,47.884016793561,17.283500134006));
#1200=CARTESIAN_POINT('',(-52.9119287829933,54.8365312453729,21.5221643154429));
#1201=CARTESIAN_POINT('',(-70.0848532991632,49.0396910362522,13.3021702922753));
#1202=CARTESIAN_POINT('',(-59.7727690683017,48.3012922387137,16.0426043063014));
#1203=CARTESIAN_POINT('',(-52.5636399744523,55.1696524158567,19.9532554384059));
#1204=CARTESIAN_POINT('',(-69.2452312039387,49.5669743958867,11.1781387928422));
#1205=CARTESIAN_POINT('',(-59.1465265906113,49.0457030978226,13.5106222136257));
#1206=CARTESIAN_POINT('',(-51.9339234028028,55.7628461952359,16.7672081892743));
#1207=CARTESIAN_POINT('',(-68.8699783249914,49.7981616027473,10.1000523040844));
#1208=CARTESIAN_POINT('',(-58.8645403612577,49.3736397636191,12.2184467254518));
#1209=CARTESIAN_POINT('',(-51.6524837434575,56.0229318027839,15.1500784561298));
#1210=CARTESIAN_POINT('',(-68.3864243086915,50.0928207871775,8.46495428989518));
#1211=CARTESIAN_POINT('',(-58.4999356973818,49.7923188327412,10.2506810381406));
#1212=CARTESIAN_POINT('',(-51.2898182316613,56.3544233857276,12.6974314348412));
#1213=CARTESIAN_POINT('',(-68.2385946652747,50.1822749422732,7.9176155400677));
#1214=CARTESIAN_POINT('',(-58.3882813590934,49.9195106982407,9.59123752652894));
#1215=CARTESIAN_POINT('',(-51.1789459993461,56.455059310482,11.8764233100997));
#1216=CARTESIAN_POINT('',(-67.9707993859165,50.3435447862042,6.81736216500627));
#1217=CARTESIAN_POINT('',(-58.185764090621,50.1489439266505,8.26384137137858));
#1218=CARTESIAN_POINT('',(-50.9780995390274,56.6364878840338,10.2260432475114));
#1219=CARTESIAN_POINT('',(-67.8508300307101,50.4153628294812,6.26444829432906));
#1220=CARTESIAN_POINT('',(-58.094840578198,50.2512560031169,7.59570735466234));
#1221=CARTESIAN_POINT('',(-50.8881225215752,56.7172831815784,9.39667244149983));
#1222=CARTESIAN_POINT('',(-67.640279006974,50.540951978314,5.15406739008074));
#1223=CARTESIAN_POINT('',(-57.9351325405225,50.4302278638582,6.25258763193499));
#1224=CARTESIAN_POINT('',(-50.7302092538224,56.85857097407,7.73110108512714));
#1225=CARTESIAN_POINT('',(-67.5496990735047,50.594722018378,4.59660008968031));
#1226=CARTESIAN_POINT('',(-57.8663017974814,50.5069402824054,5.57740600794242));
#1227=CARTESIAN_POINT('',(-50.662274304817,56.919062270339,6.8949001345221));
#1228=CARTESIAN_POINT('',(-67.3991470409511,50.6838792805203,3.47835619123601));
#1229=CARTESIAN_POINT('',(-57.7518490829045,50.6341516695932,4.22214475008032));
#1230=CARTESIAN_POINT('',(-50.5493602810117,57.0193641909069,5.21753428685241));
#1231=CARTESIAN_POINT('',(-67.3391749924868,50.7192664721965,2.9175795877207));
#1232=CARTESIAN_POINT('',(-57.7061920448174,50.6846899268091,3.54185958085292));
#1233=CARTESIAN_POINT('',(-50.5043812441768,57.0591747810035,4.3763693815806));
#1234=CARTESIAN_POINT('',(-67.2502744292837,50.7716638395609,1.78891495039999));
#1235=CARTESIAN_POINT('',(-57.6385093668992,50.7595119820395,2.17223435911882));
#1236=CARTESIAN_POINT('',(-50.4377058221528,57.1181218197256,2.68337242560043));
#1237=CARTESIAN_POINT('',(-67.2216349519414,50.7885029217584,1.22100879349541));
#1238=CARTESIAN_POINT('',(-57.6166820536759,50.7835753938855,1.4826481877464));
#1239=CARTESIAN_POINT('',(-50.4162262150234,57.1370657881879,1.83151319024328));
#1240=CARTESIAN_POINT('',(-67.196799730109,50.803107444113,0.0846340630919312));
#1241=CARTESIAN_POINT('',(-57.5977610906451,50.804438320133,0.102833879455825));
#1242=CARTESIAN_POINT('',(-50.3975997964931,57.1534958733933,0.126951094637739));
#1243=CARTESIAN_POINT('',(-67.2006040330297,50.8008728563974,-0.483834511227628));
#1244=CARTESIAN_POINT('',(-57.6006613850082,50.8012445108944,-0.587616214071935));
#1245=CARTESIAN_POINT('',(-50.4004530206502,57.1509819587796,-0.725751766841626));
#1246=CARTESIAN_POINT('',(-67.2406008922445,50.7773453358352,-1.61987385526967));
#1247=CARTESIAN_POINT('',(-57.6311305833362,50.7676365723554,-1.96691322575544));
#1248=CARTESIAN_POINT('',(-50.4304506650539,57.1245134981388,-2.42981078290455));
#1249=CARTESIAN_POINT('',(-67.2767938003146,50.7560521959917,-2.18744461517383));
#1250=CARTESIAN_POINT('',(-57.6587095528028,50.7372113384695,-2.65598161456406));
#1251=CARTESIAN_POINT('',(-50.4575953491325,57.1005587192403,-3.28116692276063));
#1252=CARTESIAN_POINT('',(-67.3810432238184,50.6945530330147,-3.32024988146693));
#1253=CARTESIAN_POINT('',(-57.7380561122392,50.6494053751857,-4.03030520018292));
#1254=CARTESIAN_POINT('',(-50.5357824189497,57.0313721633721,-4.98037482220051));
#1255=CARTESIAN_POINT('',(-67.4490997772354,50.6543469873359,-3.88548438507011));
#1256=CARTESIAN_POINT('',(-57.7898489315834,50.5919966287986,-4.71577744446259));
#1257=CARTESIAN_POINT('',(-50.5868248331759,56.986140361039,-5.82822657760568));
#1258=CARTESIAN_POINT('',(-67.6162506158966,50.5552070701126,-5.01317665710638));
#1259=CARTESIAN_POINT('',(-57.9168599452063,50.4505789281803,-6.08192420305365));
#1260=CARTESIAN_POINT('',(-50.7121879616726,56.87460795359,-7.51976498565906));
#1261=CARTESIAN_POINT('',(-67.7153947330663,50.4962431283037,-5.57562848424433));
#1262=CARTESIAN_POINT('',(-57.9921552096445,50.3664828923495,-6.76279810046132));
#1263=CARTESIAN_POINT('',(-50.7865460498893,56.8082735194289,-8.36344272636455));
#1264=CARTESIAN_POINT('',(-67.9433542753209,50.3599665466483,-6.69567829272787));
#1265=CARTESIAN_POINT('',(-58.1649472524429,50.1723564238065,-8.11679402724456));
#1266=CARTESIAN_POINT('',(-50.957515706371,56.6549623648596,-10.0435174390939));
#1267=CARTESIAN_POINT('',(-68.0721736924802,50.2826514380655,-7.25327561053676));
#1268=CARTESIAN_POINT('',(-58.2624990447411,50.0622629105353,-8.79011366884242));
#1269=CARTESIAN_POINT('',(-51.0541302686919,56.5679828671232,-10.8799134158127));
#1270=CARTESIAN_POINT('',(-68.3578199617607,50.1101257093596,-8.36243111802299));
#1271=CARTESIAN_POINT('',(-58.4783142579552,49.8169419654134,-10.1271549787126));
#1272=CARTESIAN_POINT('',(-51.268364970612,56.3738914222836,-12.5436466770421));
#1273=CARTESIAN_POINT('',(-68.5146447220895,50.0149164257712,-8.91398975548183));
#1274=CARTESIAN_POINT('',(-58.5966384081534,49.6816433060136,-10.7910625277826));
#1275=CARTESIAN_POINT('',(-51.3859835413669,56.2667809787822,-13.3709846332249));
#1276=CARTESIAN_POINT('',(-68.8544337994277,49.8070946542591,-10.0102302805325));
#1277=CARTESIAN_POINT('',(-58.852320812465,49.3867995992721,-12.1078917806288));
#1278=CARTESIAN_POINT('',(-51.6408253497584,56.0329814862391,-15.0153454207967));
#1279=CARTESIAN_POINT('',(-69.0374013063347,49.6944800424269,-10.5549113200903));
#1280=CARTESIAN_POINT('',(-58.9897513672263,49.2271668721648,-12.7609815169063));
#1281=CARTESIAN_POINT('',(-51.778050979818,55.9062900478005,-15.8323669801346));
#1282=CARTESIAN_POINT('',(-69.6176333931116,49.3343356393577,-12.1639136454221));
#1283=CARTESIAN_POINT('',(-59.4246729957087,48.7170833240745,-14.6874787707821));
#1284=CARTESIAN_POINT('',(-52.2132250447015,55.5011275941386,-18.2458704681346));
#1285=CARTESIAN_POINT('',(-70.0499541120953,49.0622881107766,-13.2172870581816));
#1286=CARTESIAN_POINT('',(-59.7472103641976,48.3327313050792,-15.9421992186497));
#1287=CARTESIAN_POINT('',(-52.5374655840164,55.1950741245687,-19.8259305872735));
#1288=CARTESIAN_POINT('',(-70.992423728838,48.4564568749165,-15.2898063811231));
#1289=CARTESIAN_POINT('',(-60.4444696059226,47.4812795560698,-18.3953826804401));
#1290=CARTESIAN_POINT('',(-53.2443177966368,54.5135139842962,-22.9347095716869));
#1291=CARTESIAN_POINT('',(-71.5025698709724,48.1226753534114,-16.3089535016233));
#1292=CARTESIAN_POINT('',(-60.8197993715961,47.0133410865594,-19.5947687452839));
#1293=CARTESIAN_POINT('',(-53.6269274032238,54.1380097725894,-24.4634302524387));
#1294=CARTESIAN_POINT('',(-72.5853559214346,47.3967459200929,-18.3118518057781));
#1295=CARTESIAN_POINT('',(-61.6085535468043,46.0018638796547,-21.9338459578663));
#1296=CARTESIAN_POINT('',(-54.4390169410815,53.3213391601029,-27.4677777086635));
#1297=CARTESIAN_POINT('',(-73.1580411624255,47.0045555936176,-19.2955766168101));
#1298=CARTESIAN_POINT('',(-62.022587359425,45.4573607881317,-23.0741638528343));
#1299=CARTESIAN_POINT('',(-54.8685308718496,52.8801250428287,-28.9433649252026));
#1300=CARTESIAN_POINT('',(-74.3511834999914,46.1649879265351,-21.2259751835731));
#1301=CARTESIAN_POINT('',(-62.8751851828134,44.3000180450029,-25.2912912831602));
#1302=CARTESIAN_POINT('',(-55.7633876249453,51.9356114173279,-31.8389627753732));
#1303=CARTESIAN_POINT('',(-74.9716474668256,45.7176026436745,-22.1726435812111));
#1304=CARTESIAN_POINT('',(-63.3142678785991,43.6862231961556,-26.3685372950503));
#1305=CARTESIAN_POINT('',(-56.2287355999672,51.4323029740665,-33.258965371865));
#1306=CARTESIAN_POINT('',(-76.0855066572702,44.8903060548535,-23.792960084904));
#1307=CARTESIAN_POINT('',(-64.0911082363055,42.561657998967,-28.1904893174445));
#1308=CARTESIAN_POINT('',(-57.0641299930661,50.5015943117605,-35.6894401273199));
#1309=CARTESIAN_POINT('',(-76.5712251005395,44.522053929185,-24.4749658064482));
#1310=CARTESIAN_POINT('',(-64.4271017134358,42.0629423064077,-28.9517108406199));
#1311=CARTESIAN_POINT('',(-57.4284188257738,50.0873106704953,-36.7124487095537));
#1312=CARTESIAN_POINT('',(-77.5572598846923,43.7569233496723,-25.8179976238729));
#1313=CARTESIAN_POINT('',(-65.1015775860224,41.033621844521,-30.4369078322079));
#1314=CARTESIAN_POINT('',(-58.16794491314,49.2265387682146,-38.7269964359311));
#1315=CARTESIAN_POINT('',(-78.0575774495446,43.3600424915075,-26.4790219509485));
#1316=CARTESIAN_POINT('',(-65.4401992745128,40.5026249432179,-31.1609169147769));
#1317=CARTESIAN_POINT('',(-58.5431830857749,48.7800478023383,-39.7185329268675));
#1318=CARTESIAN_POINT('',(-79.0684622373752,42.538211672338,-27.7800780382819));
#1319=CARTESIAN_POINT('',(-66.1157939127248,39.4112437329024,-32.5710774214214));
#1320=CARTESIAN_POINT('',(-59.3013466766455,47.8554881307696,-41.6701170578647));
#1321=CARTESIAN_POINT('',(-79.5790321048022,42.1132544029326,-28.4201042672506));
#1322=CARTESIAN_POINT('',(-66.4528663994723,38.8504746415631,-33.2571960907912));
#1323=CARTESIAN_POINT('',(-59.6842740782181,47.3774112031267,-42.6301564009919));
#1324=CARTESIAN_POINT('',(-80.6062456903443,41.2358555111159,-29.6788275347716));
#1325=CARTESIAN_POINT('',(-67.1214901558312,37.7022795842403,-34.590724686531));
#1326=CARTESIAN_POINT('',(-60.4546842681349,46.3903374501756,-44.5182413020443));
#1327=CARTESIAN_POINT('',(-81.1228900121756,40.7834111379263,-30.2975224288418));
#1328=CARTESIAN_POINT('',(-67.453100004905,37.1144923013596,-35.2380516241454));
#1329=CARTESIAN_POINT('',(-60.842167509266,45.8813375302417,-45.4462836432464));
#1330=CARTESIAN_POINT('',(-82.6776564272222,39.3841324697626,-32.1229499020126));
#1331=CARTESIAN_POINT('',(-68.4388047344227,35.3067644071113,-37.1296038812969));
#1332=CARTESIAN_POINT('',(-62.0082423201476,44.3071490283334,-48.1844248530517));
#1333=CARTESIAN_POINT('',(-83.7193271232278,38.3963833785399,-33.2973953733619));
#1334=CARTESIAN_POINT('',(-69.0756840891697,34.0552285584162,-38.3067610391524));
#1335=CARTESIAN_POINT('',(-62.789495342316,43.1959313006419,-49.946093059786));
#1336=CARTESIAN_POINT('',(-85.7835493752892,36.3149570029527,-35.5558951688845));
#1337=CARTESIAN_POINT('',(-70.2881365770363,31.4809579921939,-40.4974631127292));
#1338=CARTESIAN_POINT('',(-64.3376620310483,40.8543266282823,-53.3338427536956));
#1339=CARTESIAN_POINT('',(-86.8061035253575,35.2212942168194,-36.6399618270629));
#1340=CARTESIAN_POINT('',(-70.8631431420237,30.1561638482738,-41.5091282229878));
#1341=CARTESIAN_POINT('',(-65.1045776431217,39.6239559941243,-54.9599427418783));
#1342=CARTESIAN_POINT('',(-88.8144193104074,32.921275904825,-38.7201753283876));
#1343=CARTESIAN_POINT('',(-71.9371528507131,27.4511854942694,-43.3722632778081));
#1344=CARTESIAN_POINT('',(-66.6108144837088,37.0364353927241,-58.0802629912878));
#1345=CARTESIAN_POINT('',(-89.7998450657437,31.7141322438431,-39.7155969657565));
#1346=CARTESIAN_POINT('',(-72.4342198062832,26.0696665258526,-44.2196610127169));
#1347=CARTESIAN_POINT('',(-67.3498838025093,35.6783987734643,-59.5733954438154));
#1348=CARTESIAN_POINT('',(-91.7007881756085,29.1965861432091,-41.601340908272));
#1349=CARTESIAN_POINT('',(-73.3335541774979,23.2915601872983,-45.7435729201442));
#1350=CARTESIAN_POINT('',(-68.7755911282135,32.8461594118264,-62.4020113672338));
#1351=CARTESIAN_POINT('',(-92.616296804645,27.8861708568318,-42.4916501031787));
#1352=CARTESIAN_POINT('',(-73.733990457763,21.8950890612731,-46.4167998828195));
#1353=CARTESIAN_POINT('',(-69.4622225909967,31.3719422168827,-63.7374751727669));
#1354=CARTESIAN_POINT('',(-93.9170122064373,25.8489536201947,-43.7390472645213));
#1355=CARTESIAN_POINT('',(-74.256576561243,19.8254598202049,-47.2973966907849));
#1356=CARTESIAN_POINT('',(-70.4377591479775,29.0800728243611,-65.6085709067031));
#1357=CARTESIAN_POINT('',(-94.3381124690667,25.1586659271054,-44.1398159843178));
#1358=CARTESIAN_POINT('',(-74.4183806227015,19.136244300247,-47.5704418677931));
#1359=CARTESIAN_POINT('',(-70.753584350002,28.3034991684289,-66.2097239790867));
#1360=CARTESIAN_POINT('',(-95.153614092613,23.7545250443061,-44.9110669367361));
#1361=CARTESIAN_POINT('',(-74.7170564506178,17.766711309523,-48.0762841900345));
#1362=CARTESIAN_POINT('',(-71.3652105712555,26.7238406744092,-67.3666004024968));
#1363=CARTESIAN_POINT('',(-95.5480171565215,23.0406733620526,-45.2815511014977));
#1364=CARTESIAN_POINT('',(-74.8536653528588,17.086702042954,-48.3086529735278));
#1365=CARTESIAN_POINT('',(-71.6610128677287,25.9207575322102,-67.9223266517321));
#1366=CARTESIAN_POINT('',(-96.306880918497,21.5908455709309,-45.9905011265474));
#1367=CARTESIAN_POINT('',(-75.1026424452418,15.739930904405,-48.7349680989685));
#1368=CARTESIAN_POINT('',(-72.2301606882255,24.2897012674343,-68.985751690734));
#1369=CARTESIAN_POINT('',(-96.6713572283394,20.8548812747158,-46.328983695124));
#1370=CARTESIAN_POINT('',(-75.2147681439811,15.0735674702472,-48.9285231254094));
#1371=CARTESIAN_POINT('',(-72.5035179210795,23.4617414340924,-69.4934755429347));
#1372=CARTESIAN_POINT('',(-97.3677224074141,19.3616193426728,-46.9726405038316));
#1373=CARTESIAN_POINT('',(-75.4163766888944,13.7569522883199,-49.280042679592));
#1374=CARTESIAN_POINT('',(-73.0257918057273,21.7818217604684,-70.4589607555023));
#1375=CARTESIAN_POINT('',(-97.6996034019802,18.6043166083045,-47.2778066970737));
#1376=CARTESIAN_POINT('',(-75.5056188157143,13.1072034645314,-49.4376190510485));
#1377=CARTESIAN_POINT('',(-73.2747025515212,20.9298561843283,-70.9167100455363));
#1378=CARTESIAN_POINT('',(-98.4578220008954,16.7525764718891,-47.9722052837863));
#1379=CARTESIAN_POINT('',(-75.6964497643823,11.5593625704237,-49.7793518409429));
#1380=CARTESIAN_POINT('',(-73.8433665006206,18.8466485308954,-71.9583079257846));
#1381=CARTESIAN_POINT('',(-98.8664355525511,15.6482772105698,-48.3439872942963));
#1382=CARTESIAN_POINT('',(-75.7869751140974,10.6744117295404,-49.9460065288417));
#1383=CARTESIAN_POINT('',(-74.1498266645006,17.6043118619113,-72.515980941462));
#1384=CARTESIAN_POINT('',(-99.6049593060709,13.4060429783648,-49.0131207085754));
#1385=CARTESIAN_POINT('',(-75.934584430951,8.94596732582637,-50.2254219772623));
#1386=CARTESIAN_POINT('',(-74.7037194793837,15.081798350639,-73.519681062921));
#1387=CARTESIAN_POINT('',(-99.9348880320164,12.2681159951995,-49.3104896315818));
#1388=CARTESIAN_POINT('',(-75.9912508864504,8.10429698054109,-50.3374747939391));
#1389=CARTESIAN_POINT('',(-74.9511660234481,13.8016304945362,-73.9657344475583));
#1390=CARTESIAN_POINT('',(-100.365749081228,10.5418201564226,-49.6976642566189));
#1391=CARTESIAN_POINT('',(-76.0575481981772,6.87400791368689,-50.4734687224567));
#1392=CARTESIAN_POINT('',(-75.274311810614,11.8595476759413,-74.5464963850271));
#1393=CARTESIAN_POINT('',(-100.498656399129,9.96339300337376,-49.8168728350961));
#1394=CARTESIAN_POINT('',(-76.0765347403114,6.46869685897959,-50.5134716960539));
#1395=CARTESIAN_POINT('',(-75.3739922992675,11.2088171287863,-74.7253092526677));
#1396=CARTESIAN_POINT('',(-100.742553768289,8.80082034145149,-50.0353394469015));
#1397=CARTESIAN_POINT('',(-76.1093582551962,5.66724381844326,-50.5842011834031));
#1398=CARTESIAN_POINT('',(-75.5569153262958,9.90092288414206,-75.0530091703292));
#1399=CARTESIAN_POINT('',(-100.853547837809,8.21667590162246,-50.1346011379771));
#1400=CARTESIAN_POINT('',(-76.1231715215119,5.27134083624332,-50.6148819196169));
#1401=CARTESIAN_POINT('',(-75.6401608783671,9.24376038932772,-75.2019017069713));
#1402=CARTESIAN_POINT('',(-101.053048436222,7.04353206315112,-50.3128281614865));
#1403=CARTESIAN_POINT('',(-76.1466496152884,4.48745195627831,-50.6682511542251));
#1404=CARTESIAN_POINT('',(-75.7897863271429,7.92397357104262,-75.4692422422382));
#1405=CARTESIAN_POINT('',(-101.141552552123,6.45453215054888,-50.3917913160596));
#1406=CARTESIAN_POINT('',(-76.1562967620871,4.09970742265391,-50.6909033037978));
#1407=CARTESIAN_POINT('',(-75.8561644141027,7.26134866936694,-75.5876869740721));
#1408=CARTESIAN_POINT('',(-101.2955878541,5.27281829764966,-50.5291146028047));
#1409=CARTESIAN_POINT('',(-76.1722838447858,3.33064262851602,-50.7292777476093));
#1410=CARTESIAN_POINT('',(-75.9716908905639,5.93192058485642,-75.7936719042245));
#1411=CARTESIAN_POINT('',(-101.361117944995,4.6801041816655,-50.5874737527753));
#1412=CARTESIAN_POINT('',(-76.1786123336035,2.94956074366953,-50.7449746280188));
#1413=CARTESIAN_POINT('',(-76.0208384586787,5.26511720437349,-75.8812106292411));
#1414=CARTESIAN_POINT('',(-101.522884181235,2.89534647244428,-50.7314755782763));
#1415=CARTESIAN_POINT('',(-76.1937665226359,1.81075978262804,-50.783135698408));
#1416=CARTESIAN_POINT('',(-76.1421631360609,3.25726478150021,-76.097213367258));
#1417=CARTESIAN_POINT('',(-101.583886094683,1.69908667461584,-50.7856770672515));
#1418=CARTESIAN_POINT('',(-76.1986600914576,1.06209143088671,-50.7964238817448));
#1419=CARTESIAN_POINT('',(-76.1879145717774,1.91147250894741,-76.1785156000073));
#1420=CARTESIAN_POINT('',(-101.610527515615,-0.694590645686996,-50.8093571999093));
#1421=CARTESIAN_POINT('',(-76.2008743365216,-0.434478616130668,-50.8023351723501));
#1422=CARTESIAN_POINT('',(-76.2078956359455,-0.781414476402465,-76.214035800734));
#1423=CARTESIAN_POINT('',(-101.576165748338,-1.89200818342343,-50.7788347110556));
#1424=CARTESIAN_POINT('',(-76.1981894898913,-1.18050476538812,-50.7949433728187));
#1425=CARTESIAN_POINT('',(-76.1821243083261,-2.12850920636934,-76.1682520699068));
#1426=CARTESIAN_POINT('',(-101.412756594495,-4.28095859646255,-50.6334647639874));
#1427=CARTESIAN_POINT('',(-76.1836291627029,-2.69089908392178,-50.7573941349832));
#1428=CARTESIAN_POINT('',(-76.0595674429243,-4.81607842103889,-75.9501971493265));
#1429=CARTESIAN_POINT('',(-101.283542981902,-5.472477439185,-50.5184692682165));
#1430=CARTESIAN_POINT('',(-76.1717751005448,-3.4534015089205,-50.7272915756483));
#1431=CARTESIAN_POINT('',(-75.9626572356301,-6.15653711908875,-75.7777039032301));
#1432=CARTESIAN_POINT('',(-100.933139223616,-7.83839427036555,-50.2058112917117));
#1433=CARTESIAN_POINT('',(-76.1333464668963,-5.01040488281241,-50.6372748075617));
#1434=CARTESIAN_POINT('',(-75.6998544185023,-8.8181935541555,-75.3087169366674));
#1435=CARTESIAN_POINT('',(-100.711955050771,-9.01279336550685,-50.008154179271));
#1436=CARTESIAN_POINT('',(-76.1068833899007,-5.80296187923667,-50.577600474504));
#1437=CARTESIAN_POINT('',(-75.5339662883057,-10.139392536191,-75.0122312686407));
#1438=CARTESIAN_POINT('',(-100.192541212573,-11.2918628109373,-49.5422500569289));
#1439=CARTESIAN_POINT('',(-76.0324796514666,-7.39893295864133,-50.4209497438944));
#1440=CARTESIAN_POINT('',(-75.1444059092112,-12.7033456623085,-74.313375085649));
#1441=CARTESIAN_POINT('',(-99.8975861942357,-12.3974811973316,-49.2769959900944));
#1442=CARTESIAN_POINT('',(-75.9856177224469,-8.19879919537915,-50.3258997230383));
#1443=CARTESIAN_POINT('',(-74.9231896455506,-13.9471663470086,-73.9154939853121));
#1444=CARTESIAN_POINT('',(-99.2325624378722,-14.5792487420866,-48.676135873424));
#1445=CARTESIAN_POINT('',(-75.8625658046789,-9.84041137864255,-50.0877957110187));
#1446=CARTESIAN_POINT('',(-74.4244218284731,-16.401654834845,-73.0142038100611));
#1447=CARTESIAN_POINT('',(-98.8624821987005,-15.6553933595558,-48.3405190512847));
#1448=CARTESIAN_POINT('',(-75.7867083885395,-10.6804818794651,-49.9453161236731));
#1449=CARTESIAN_POINT('',(-74.1468616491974,-17.6123175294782,-72.5107785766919));
#1450=CARTESIAN_POINT('',(-98.0547641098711,-17.7700668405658,-47.6037284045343));
#1451=CARTESIAN_POINT('',(-75.5983252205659,-12.3981964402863,-49.602373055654));
#1452=CARTESIAN_POINT('',(-73.5410730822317,-19.9913251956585,-71.4055926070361));
#1453=CARTESIAN_POINT('',(-97.6173074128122,-18.8086876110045,-47.2027302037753));
#1454=CARTESIAN_POINT('',(-75.4863709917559,-13.2741897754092,-49.4028447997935));
#1455=CARTESIAN_POINT('',(-73.2129805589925,-21.1597735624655,-70.8040953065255));
#1456=CARTESIAN_POINT('',(-96.9154985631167,-20.3369962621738,-46.5548369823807));
#1457=CARTESIAN_POINT('',(-75.2860501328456,-14.6161424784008,-49.0525676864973));
#1458=CARTESIAN_POINT('',(-72.6866239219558,-22.8791207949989,-69.8322554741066));
#1459=CARTESIAN_POINT('',(-96.6740050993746,-20.8414087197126,-46.3311836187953));
#1460=CARTESIAN_POINT('',(-75.2142664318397,-15.0660312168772,-48.9279746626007));
#1461=CARTESIAN_POINT('',(-72.5055038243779,-23.4465848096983,-69.496775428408));
#1462=CARTESIAN_POINT('',(-96.176700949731,-21.8400740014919,-45.8688762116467));
#1463=CARTESIAN_POINT('',(-75.0596544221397,-15.9727381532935,-48.6613404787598));
#1464=CARTESIAN_POINT('',(-72.1325257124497,-24.5700832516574,-68.8033143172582));
#1465=CARTESIAN_POINT('',(-95.9208913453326,-22.3343275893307,-45.630223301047));
#1466=CARTESIAN_POINT('',(-74.9769046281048,-16.4294148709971,-48.5194259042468));
#1467=CARTESIAN_POINT('',(-71.9406685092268,-25.1261185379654,-68.4453349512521));
#1468=CARTESIAN_POINT('',(-95.6583591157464,-22.8233635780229,-45.3842932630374));
#1469=CARTESIAN_POINT('',(-74.8881430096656,-16.890385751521,-48.3679358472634));
#1470=CARTESIAN_POINT('',(-71.7437693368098,-25.6762840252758,-68.076439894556));
#1471=(BOUNDED_SURFACE() B_SPLINE_SURFACE(3,2,((#1021,#1022,#1023),(#1024,#1025,#1026),(#1027,
#1028,#1029),(#1030,#1031,#1032),(#1033,#1034,#1035),(#1036,#1037,#1038),(#1039,#1040,#1041),
(#1042,#1043,#1044),(#1045,#1046,#1047),(#1048,#1049,#1050),(#1051,#1052,#1053),(#1054,#1055,
#1056),(#1057,#1058,#1059),(#1060,#1061,#1062),(#1063,#1064,#1065),(#1066,#1067,#1068),(#1069,
#1070,#1071),(#1072,#1073,#1074),(#1075,#1076,#1077),(#1078,#1079,#1080),(#1081,#1082,#1083),
(#1084,#1085,#1086),(#1087,#1088,#1089),(#1090,#1091,#1092),(#1093,#1094,#1095),(#1096,#1097,
#1098),(#1099,#1100,#1101),(#1102,#1103,#1104),(#1105,#1106,#1107),(#1108,#1109,#1110),(#1111,
#1112,#1113),(#1114,#1115,#1116),(#1117,#1118,#1119),(#1120,#1121,#1122),(#1123,#1124,#1125),
(#1126,#1127,#1128),(#1129,#1130,#1131),(#1132,#1133,#1134),(#1135,#1136,#1137),(#1138,#1139,
#1140),(#1141,#1142,#1143),(#1144,#1145,#1146),(#1147,#1148,#1149),(#1150,#1151,#1152),(#1153,
#1154,#1155),(#1156,#1157,#1158),(#1159,#1160,#1161),(#1162,#1163,#1164),(#1165,#1166,#1167),
(#1168,#1169,#1170),(#1171,#1172,#1173),(#1174,#1175,#1176),(#1177,#1178,#1179),(#1180,#1181,
#1182),(#1183,#1184,#1185),(#1186,#1187,#1188),(#1189,#1190,#1191),(#1192,#1193,#1194),(#1195,
#1196,#1197),(#1198,#1199,#1200),(#1201,#1202,#1203),(#1204,#1205,#1206),(#1207,#1208,#1209),
(#1210,#1211,#1212),(#1213,#1214,#1215),(#1216,#1217,#1218),(#1219,#1220,#1221),(#1222,#1223,
#1224),(#1225,#1226,#1227),(#1228,#1229,#1230),(#1231,#1232,#1233),(#1234,#1235,#1236),(#1237,
#1238,#1239),(#1240,#1241,#1242),(#1243,#1244,#1245),(#1246,#1247,#1248),(#1249,#1250,#1251),
(#1252,#1253,#1254),(#1255,#1256,#1257),(#1258,#1259,#1260),(#1261,#1262,#1263),(#1264,#1265,
#1266),(#1267,#1268,#1269),(#1270,#1271,#1272),(#1273,#1274,#1275),(#1276,#1277,#1278),(#1279,
#1280,#1281),(#1282,#1283,#1284),(#1285,#1286,#1287),(#1288,#1289,#1290),(#1291,#1292,#1293),
(#1294,#1295,#1296),(#1297,#1298,#1299),(#1300,#1301,#1302),(#1303,#1304,#1305),(#1306,#1307,
#1308),(#1309,#1310,#1311),(#1312,#1313,#1314),(#1315,#1316,#1317),(#1318,#1319,#1320),(#1321,
#1322,#1323),(#1324,#1325,#1326),(#1327,#1328,#1329),(#1330,#1331,#1332),(#1333,#1334,#1335),
(#1336,#1337,#1338),(#1339,#1340,#1341),(#1342,#1343,#1344),(#1345,#1346,#1347),(#1348,#1349,
#1350),(#1351,#1352,#1353),(#1354,#1355,#1356),(#1357,#1358,#1359),(#1360,#1361,#1362),(#1363,
#1364,#1365),(#1366,#1367,#1368),(#1369,#1370,#1371),(#1372,#1373,#1374),(#1375,#1376,#1377),
(#1378,#1379,#1380),(#1381,#1382,#1383),(#1384,#1385,#1386),(#1387,#1388,#1389),(#1390,#1391,
#1392),(#1393,#1394,#1395),(#1396,#1397,#1398),(#1399,#1400,#1401),(#1402,#1403,#1404),(#1405,
#1406,#1407),(#1408,#1409,#1410),(#1411,#1412,#1413),(#1414,#1415,#1416),(#1417,#1418,#1419),
(#1420,#1421,#1422),(#1423,#1424,#1425),(#1426,#1427,#1428),(#1429,#1430,#1431),(#1432,#1433,
#1434),(#1435,#1436,#1437),(#1438,#1439,#1440),(#1441,#1442,#1443),(#1444,#1445,#1446),(#1447,
#1448,#1449),(#1450,#1451,#1452),(#1453,#1454,#1455),(#1456,#1457,#1458),(#1459,#1460,#1461),
(#1462,#1463,#1464),(#1465,#1466,#1467),(#1468,#1469,#1470)),.UNSPECIFIED.,.F.,.F.,
.F.) B_SPLINE_SURFACE_WITH_KNOTS((4,2,2,2,2,2,2,2,2,2,2,2,2,2,2,2,2,2,2,2,2,2,2,2,2,2,2,2,2,2,2,
2,2,2,2,2,2,2,2,2,2,2,2,2,2,2,2,2,2,2,2,2,2,2,2,2,2,2,2,2,2,2,2,2,2,2,2,2,2,2,2,2,2,2,4),(3,3),
(0.,2.92928734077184,5.85888262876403,11.7218095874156,17.6096173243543,23.4957956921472,
29.41558780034,35.3358745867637,41.2393728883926,47.1421495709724,52.3683943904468,
57.5941964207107,62.8246971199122,68.0554450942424,73.4115344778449,78.7676440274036,
84.1223570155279,89.477770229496,92.5895909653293,95.7007977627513,101.923323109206,
108.157334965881,114.39162718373,118.112926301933,121.833968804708,125.556606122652,
129.278829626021,132.996267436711,136.713838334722,144.142116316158,149.223660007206,
154.304298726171,156.838351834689,159.372066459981,161.905930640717,164.439799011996,
166.99684976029,169.553904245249,172.110986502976,174.668071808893,177.229277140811,
179.790827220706,182.352186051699,184.913857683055,189.972260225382,195.030483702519,
200.092398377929,205.155042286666,208.933866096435,212.713007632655,216.493136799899,
220.273644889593,227.844127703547,235.413575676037,243.040145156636,250.667664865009,
254.473912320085,258.279916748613,262.083922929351,265.888845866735,271.267867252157,
276.645621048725,279.332314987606,282.018515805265,284.705004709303,287.391621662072,
292.775807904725,298.160066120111,303.553782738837,308.94714912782,314.133986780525,
319.321619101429,324.495539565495,327.081584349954,329.667434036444),(0.,1.),
.UNSPECIFIED.) GEOMETRIC_REPRESENTATION_ITEM() RATIONAL_B_SPLINE_SURFACE(((1.,0.774907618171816,
1.),(1.,0.772323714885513,1.),(1.,0.769768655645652,1.),(1.,0.764732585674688,1.),(1.,
0.76225158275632,1.),(1.,0.754941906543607,1.),(1.,0.750249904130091,1.),(1.,0.741360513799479,
1.),(1.,0.737165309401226,1.),(1.,0.729444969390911,1.),(1.,0.725919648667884,1.),(1.,
0.719663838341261,1.),(1.,0.716938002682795,1.),(1.,0.712432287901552,1.),(1.,0.710652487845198,
1.),(1.,0.708129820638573,1.),(1.,0.707384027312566,1.),(1.,0.706957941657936,1.),(1.,
0.707277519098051,1.),(1.,0.708868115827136,1.),(1.,0.710025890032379,1.),(1.,0.713117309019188,
1.),(1.,0.715050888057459,1.),(1.,0.719624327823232,1.),(1.,0.722264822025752,1.),(1.,
0.728160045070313,1.),(1.,0.731414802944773,1.),(1.,0.738520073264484,1.),(1.,0.74238299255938,
1.),(1.,0.75053095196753,1.),(1.,0.754815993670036,1.),(1.,0.76369513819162,1.),(1.,
0.768289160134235,1.),(1.,0.777683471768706,1.),(1.,0.782483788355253,1.),(1.,0.790159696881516,
1.),(1.,0.792999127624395,1.),(1.,0.798697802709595,1.),(1.,0.801557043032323,1.),(1.,
0.81014200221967,1.),(1.,0.815874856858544,1.),(1.,0.827253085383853,1.),(1.,0.832898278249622,
1.),(1.,0.843993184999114,1.),(1.,0.849442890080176,1.),(1.,0.857918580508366,1.),(1.,
0.861036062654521,1.),(1.,0.867153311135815,1.),(1.,0.870153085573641,1.),(1.,0.876019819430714,
1.),(1.,0.878886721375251,1.),(1.,0.884470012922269,1.),(1.,0.887186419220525,1.),(1.,
0.892449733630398,1.),(1.,0.894996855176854,1.),(1.,0.899908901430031,1.),(1.,0.902273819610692,
1.),(1.,0.909067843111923,1.),(1.,0.913201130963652,1.),(1.,0.919372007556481,1.),(1.,
0.921659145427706,1.),(1.,0.92574880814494,1.),(1.,0.927551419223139,1.),(1.,0.929855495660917,
1.),(1.,0.930556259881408,1.),(1.,0.931821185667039,1.),(1.,0.932385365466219,1.),(1.,
0.933372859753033,1.),(1.,0.933796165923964,1.),(1.,0.934498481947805,1.),(1.,0.934777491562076,
1.),(1.,0.935190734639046,1.),(1.,0.935323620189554,1.),(1.,0.935438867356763,1.),(1.,
0.9354212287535,1.),(1.,0.935235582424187,1.),(1.,0.935067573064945,1.),(1.,0.934582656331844,
1.),(1.,0.934265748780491,1.),(1.,0.933485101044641,1.),(1.,0.933021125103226,1.),(1.,
0.931950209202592,1.),(1.,0.931343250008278,1.),(1.,0.929991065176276,1.),(1.,0.929245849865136,
1.),(1.,0.927622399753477,1.),(1.,0.926744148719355,1.),(1.,0.923941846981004,1.),(1.,
0.921832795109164,1.),(1.,0.917164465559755,1.),(1.,0.914605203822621,1.),(1.,0.909080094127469,
1.),(1.,0.906113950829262,1.),(1.,0.899819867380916,1.),(1.,0.896491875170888,1.),(1.,
0.890401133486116,1.),(1.,0.887709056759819,1.),(1.,0.882163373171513,1.),(1.,0.879309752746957,
1.),(1.,0.873457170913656,1.),(1.,0.870458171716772,1.),(1.,0.864332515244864,1.),(1.,
0.861205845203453,1.),(1.,0.851651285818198,1.),(1.,0.845056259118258,1.),(1.,0.831578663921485,
1.),(1.,0.824696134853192,1.),(1.,0.810769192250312,1.),(1.,0.803723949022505,1.),(1.,
0.789739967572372,1.),(1.,0.782801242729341,1.),(1.,0.7726823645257,1.),(1.,0.769360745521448,
1.),(1.,0.762847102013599,1.),(1.,0.759655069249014,1.),(1.,0.753440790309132,1.),(1.,
0.750418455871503,1.),(1.,0.744581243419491,1.),(1.,0.741766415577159,1.),(1.,0.735272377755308,
1.),(1.,0.731717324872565,1.),(1.,0.725219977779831,1.),(1.,0.722277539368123,1.),(1.,
0.718402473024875,1.),(1.,0.717200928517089,1.),(1.,0.714987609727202,1.),(1.,0.713975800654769,
1.),(1.,0.712151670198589,1.),(1.,0.711339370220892,1.),(1.,0.70992238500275,1.),(1.,
0.709317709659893,1.),(1.,0.707823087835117,1.),(1.,0.707256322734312,1.),(1.,0.707009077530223,
1.),(1.,0.707328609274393,1.),(1.,0.708841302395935,1.),(1.,0.710035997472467,1.),(1.,
0.713251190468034,1.),(1.,0.715271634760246,1.),(1.,0.719966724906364,1.),(1.,0.722613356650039,
1.),(1.,0.728507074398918,1.),(1.,0.731754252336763,1.),(1.,0.738739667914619,1.),(1.,
0.7424765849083,1.),(1.,0.748375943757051,1.),(1.,0.750391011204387,1.),(1.,0.754506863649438,
1.),(1.,0.756607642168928,1.),(1.,0.75874520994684,1.))) REPRESENTATION_ITEM('') SURFACE());
#1472=CARTESIAN_POINT('',(-70.2230556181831,-29.5831448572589,65.1965921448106));
#1473=CARTESIAN_POINT('',(-70.4714068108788,-28.9936222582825,65.6721356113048));
#1474=CARTESIAN_POINT('',(-70.7144033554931,-28.3960534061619,66.1347646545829));
#1475=CARTESIAN_POINT('',(-71.1887161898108,-27.1851004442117,67.0333018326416));
#1476=CARTESIAN_POINT('',(-71.4200312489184,-26.5717146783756,67.4692071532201));
#1477=CARTESIAN_POINT('',(-72.0952075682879,-24.7076443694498,68.7358913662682));
#1478=CARTESIAN_POINT('',(-72.5199806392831,-23.4337996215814,69.5250295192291));
#1479=CARTESIAN_POINT('',(-73.3119198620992,-20.8247230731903,70.9862477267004));
#1480=CARTESIAN_POINT('',(-73.6788338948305,-19.4892537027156,71.6578168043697));
#1481=CARTESIAN_POINT('',(-74.345063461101,-16.7693426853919,72.8708681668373));
#1482=CARTESIAN_POINT('',(-74.6443976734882,-15.3849146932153,73.412386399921));
#1483=CARTESIAN_POINT('',(-75.1701621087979,-12.5678622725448,74.3600050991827));
#1484=CARTESIAN_POINT('',(-75.396166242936,-11.1350077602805,74.7653145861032));
#1485=CARTESIAN_POINT('',(-75.7672507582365,-8.2397531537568,75.4292770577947));
#1486=CARTESIAN_POINT('',(-75.9123243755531,-6.77735060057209,75.6879177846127));
#1487=CARTESIAN_POINT('',(-76.1173726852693,-3.84014576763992,76.0531411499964));
#1488=CARTESIAN_POINT('',(-76.1775875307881,-2.36539041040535,76.1601529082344));
#1489=CARTESIAN_POINT('',(-76.2120335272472,0.586797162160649,76.2213951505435));
#1490=CARTESIAN_POINT('',(-76.1862751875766,2.06422902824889,76.1756443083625));
#1491=CARTESIAN_POINT('',(-76.0573845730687,4.83912430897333,75.9463070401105));
#1492=CARTESIAN_POINT('',(-75.9634586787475,6.13780677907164,75.7791192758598));
#1493=CARTESIAN_POINT('',(-75.7108210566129,8.7172552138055,75.3283017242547));
#1494=CARTESIAN_POINT('',(-75.5521148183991,9.99802268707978,75.0446818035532));
#1495=CARTESIAN_POINT('',(-75.1729594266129,12.5344426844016,74.3646917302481));
#1496=CARTESIAN_POINT('',(-74.9524548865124,13.7900715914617,73.968220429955));
#1497=CARTESIAN_POINT('',(-74.4539940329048,16.2677563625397,73.0677810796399));
#1498=CARTESIAN_POINT('',(-74.1760350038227,17.4898106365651,72.5638079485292));
#1499=CARTESIAN_POINT('',(-73.5603631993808,19.9229884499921,71.4409660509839));
#1500=CARTESIAN_POINT('',(-73.2213781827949,21.1331483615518,70.8196334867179));
#1501=CARTESIAN_POINT('',(-72.4943006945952,23.5065305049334,69.4771254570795));
#1502=CARTESIAN_POINT('',(-72.1062080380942,24.6697525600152,68.7559496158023));
#1503=CARTESIAN_POINT('',(-71.2872490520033,26.9449397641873,67.2206074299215));
#1504=CARTESIAN_POINT('',(-70.8563939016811,28.0569181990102,66.4064653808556));
#1505=CARTESIAN_POINT('',(-69.958091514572,30.2272194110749,64.6911186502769));
#1506=CARTESIAN_POINT('',(-69.4906395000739,31.2855351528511,63.7899025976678));
#1507=CARTESIAN_POINT('',(-68.7278814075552,32.9143657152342,62.3009741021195));
#1508=CARTESIAN_POINT('',(-68.4424991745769,33.5034944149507,61.7400951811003));
#1509=CARTESIAN_POINT('',(-67.8629081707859,34.6624496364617,60.5920143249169));
#1510=CARTESIAN_POINT('',(-67.5687011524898,35.2322799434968,60.0048176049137));
#1511=CARTESIAN_POINT('',(-66.6745621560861,36.9127701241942,58.2047749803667));
#1512=CARTESIAN_POINT('',(-66.0631223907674,37.9944077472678,56.9534963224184));
#1513=CARTESIAN_POINT('',(-64.8190199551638,40.0800747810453,54.3528092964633));
#1514=CARTESIAN_POINT('',(-64.1863201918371,41.0839572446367,53.003224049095));
#1515=CARTESIAN_POINT('',(-62.911363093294,43.0108636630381,50.2122019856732));
#1516=CARTESIAN_POINT('',(-62.2691053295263,43.9338839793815,48.7707610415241));
#1517=CARTESIAN_POINT('',(-61.2452737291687,45.3418163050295,46.3984921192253));
#1518=CARTESIAN_POINT('',(-60.8629763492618,45.8533510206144,45.4960499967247));
#1519=CARTESIAN_POINT('',(-60.1017871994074,46.8466272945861,43.6600330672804));
#1520=CARTESIAN_POINT('',(-59.722895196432,47.3283709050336,42.7264604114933));
#1521=CARTESIAN_POINT('',(-58.9711784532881,48.2617796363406,40.8280526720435));
#1522=CARTESIAN_POINT('',(-58.5983563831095,48.713431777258,39.8632043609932));
#1523=CARTESIAN_POINT('',(-57.8620586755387,49.5857631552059,37.9029210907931));
#1524=CARTESIAN_POINT('',(-57.4985820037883,50.006445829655,36.9074895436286));
#1525=CARTESIAN_POINT('',(-56.7847225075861,50.8156068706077,34.8873253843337));
#1526=CARTESIAN_POINT('',(-56.4343234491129,51.2041259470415,33.8626320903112));
#1527=CARTESIAN_POINT('',(-55.749830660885,51.9485549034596,31.7830760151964));
#1528=CARTESIAN_POINT('',(-55.4157375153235,52.3044636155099,30.728212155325));
#1529=CARTESIAN_POINT('',(-54.444138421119,53.3212206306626,27.519686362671));
#1530=CARTESIAN_POINT('',(-53.8366404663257,53.9318498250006,25.320227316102));
#1531=CARTESIAN_POINT('',(-52.9119287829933,54.8365312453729,21.5221643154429));
#1532=CARTESIAN_POINT('',(-52.5636399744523,55.1696524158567,19.9532554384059));
#1533=CARTESIAN_POINT('',(-51.9339234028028,55.7628461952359,16.7672081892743));
#1534=CARTESIAN_POINT('',(-51.6524837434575,56.0229318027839,15.1500784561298));
#1535=CARTESIAN_POINT('',(-51.2898182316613,56.3544233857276,12.6974314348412));
#1536=CARTESIAN_POINT('',(-51.1789459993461,56.455059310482,11.8764233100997));
#1537=CARTESIAN_POINT('',(-50.9780995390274,56.6364878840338,10.2260432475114));
#1538=CARTESIAN_POINT('',(-50.8881225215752,56.7172831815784,9.39667244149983));
#1539=CARTESIAN_POINT('',(-50.7302092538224,56.85857097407,7.73110108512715));
#1540=CARTESIAN_POINT('',(-50.662274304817,56.919062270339,6.8949001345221));
#1541=CARTESIAN_POINT('',(-50.5493602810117,57.0193641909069,5.21753428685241));
#1542=CARTESIAN_POINT('',(-50.5043812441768,57.0591747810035,4.3763693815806));
#1543=CARTESIAN_POINT('',(-50.4377058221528,57.1181218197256,2.68337242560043));
#1544=CARTESIAN_POINT('',(-50.4162262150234,57.1370657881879,1.83151319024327));
#1545=CARTESIAN_POINT('',(-50.3975997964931,57.1534958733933,0.126951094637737));
#1546=CARTESIAN_POINT('',(-50.4004530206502,57.1509819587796,-0.725751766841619));
#1547=CARTESIAN_POINT('',(-50.4304506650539,57.1245134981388,-2.42981078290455));
#1548=CARTESIAN_POINT('',(-50.4575953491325,57.1005587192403,-3.28116692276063));
#1549=CARTESIAN_POINT('',(-50.5357824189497,57.0313721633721,-4.98037482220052));
#1550=CARTESIAN_POINT('',(-50.5868248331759,56.986140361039,-5.82822657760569));
#1551=CARTESIAN_POINT('',(-50.7121879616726,56.87460795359,-7.51976498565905));
#1552=CARTESIAN_POINT('',(-50.7865460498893,56.8082735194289,-8.36344272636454));
#1553=CARTESIAN_POINT('',(-50.957515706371,56.6549623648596,-10.0435174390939));
#1554=CARTESIAN_POINT('',(-51.0541302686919,56.5679828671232,-10.8799134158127));
#1555=CARTESIAN_POINT('',(-51.268364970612,56.3738914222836,-12.5436466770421));
#1556=CARTESIAN_POINT('',(-51.3859835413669,56.2667809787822,-13.370984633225));
#1557=CARTESIAN_POINT('',(-51.6408253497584,56.0329814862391,-15.0153454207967));
#1558=CARTESIAN_POINT('',(-51.778050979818,55.9062900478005,-15.8323669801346));
#1559=CARTESIAN_POINT('',(-52.2132250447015,55.5011275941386,-18.2458704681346));
#1560=CARTESIAN_POINT('',(-52.5374655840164,55.1950741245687,-19.8259305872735));
#1561=CARTESIAN_POINT('',(-53.2443177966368,54.5135139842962,-22.9347095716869));
#1562=CARTESIAN_POINT('',(-53.6269274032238,54.1380097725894,-24.4634302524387));
#1563=CARTESIAN_POINT('',(-54.4390169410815,53.3213391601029,-27.4677777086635));
#1564=CARTESIAN_POINT('',(-54.8685308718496,52.8801250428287,-28.9433649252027));
#1565=CARTESIAN_POINT('',(-55.7633876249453,51.9356114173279,-31.8389627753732));
#1566=CARTESIAN_POINT('',(-56.2287355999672,51.4323029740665,-33.258965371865));
#1567=CARTESIAN_POINT('',(-57.0641299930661,50.5015943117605,-35.6894401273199));
#1568=CARTESIAN_POINT('',(-57.4284188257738,50.0873106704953,-36.7124487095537));
#1569=CARTESIAN_POINT('',(-58.16794491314,49.2265387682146,-38.7269964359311));
#1570=CARTESIAN_POINT('',(-58.5431830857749,48.7800478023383,-39.7185329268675));
#1571=CARTESIAN_POINT('',(-59.3013466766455,47.8554881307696,-41.6701170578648));
#1572=CARTESIAN_POINT('',(-59.6842740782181,47.3774112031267,-42.6301564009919));
#1573=CARTESIAN_POINT('',(-60.4546842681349,46.3903374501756,-44.5182413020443));
#1574=CARTESIAN_POINT('',(-60.842167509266,45.8813375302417,-45.4462836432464));
#1575=CARTESIAN_POINT('',(-62.0082423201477,44.3071490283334,-48.1844248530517));
#1576=CARTESIAN_POINT('',(-62.789495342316,43.1959313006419,-49.9460930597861));
#1577=CARTESIAN_POINT('',(-64.3376620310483,40.8543266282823,-53.3338427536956));
#1578=CARTESIAN_POINT('',(-65.1045776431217,39.6239559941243,-54.9599427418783));
#1579=CARTESIAN_POINT('',(-66.6108144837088,37.0364353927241,-58.0802629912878));
#1580=CARTESIAN_POINT('',(-67.3498838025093,35.6783987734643,-59.5733954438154));
#1581=CARTESIAN_POINT('',(-68.7755911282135,32.8461594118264,-62.4020113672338));
#1582=CARTESIAN_POINT('',(-69.4622225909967,31.3719422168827,-63.7374751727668));
#1583=CARTESIAN_POINT('',(-70.4377591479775,29.0800728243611,-65.6085709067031));
#1584=CARTESIAN_POINT('',(-70.753584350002,28.3034991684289,-66.2097239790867));
#1585=CARTESIAN_POINT('',(-71.3652105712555,26.7238406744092,-67.3666004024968));
#1586=CARTESIAN_POINT('',(-71.6610128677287,25.9207575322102,-67.9223266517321));
#1587=CARTESIAN_POINT('',(-72.2301606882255,24.2897012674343,-68.985751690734));
#1588=CARTESIAN_POINT('',(-72.5035179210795,23.4617414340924,-69.4934755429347));
#1589=CARTESIAN_POINT('',(-73.0257918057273,21.7818217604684,-70.4589607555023));
#1590=CARTESIAN_POINT('',(-73.2747025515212,20.9298561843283,-70.9167100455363));
#1591=CARTESIAN_POINT('',(-73.8433665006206,18.8466485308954,-71.9583079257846));
#1592=CARTESIAN_POINT('',(-74.1498266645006,17.6043118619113,-72.515980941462));
#1593=CARTESIAN_POINT('',(-74.7037194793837,15.081798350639,-73.519681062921));
#1594=CARTESIAN_POINT('',(-74.9511660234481,13.8016304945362,-73.9657344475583));
#1595=CARTESIAN_POINT('',(-75.2743118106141,11.8595476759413,-74.5464963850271));
#1596=CARTESIAN_POINT('',(-75.3739922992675,11.2088171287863,-74.7253092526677));
#1597=CARTESIAN_POINT('',(-75.5569153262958,9.90092288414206,-75.0530091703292));
#1598=CARTESIAN_POINT('',(-75.6401608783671,9.24376038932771,-75.2019017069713));
#1599=CARTESIAN_POINT('',(-75.7897863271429,7.92397357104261,-75.4692422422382));
#1600=CARTESIAN_POINT('',(-75.8561644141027,7.26134866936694,-75.5876869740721));
#1601=CARTESIAN_POINT('',(-75.9716908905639,5.93192058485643,-75.7936719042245));
#1602=CARTESIAN_POINT('',(-76.0208384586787,5.26511720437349,-75.8812106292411));
#1603=CARTESIAN_POINT('',(-76.1421631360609,3.2572647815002,-76.097213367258));
#1604=CARTESIAN_POINT('',(-76.1879145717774,1.9114725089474,-76.1785156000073));
#1605=CARTESIAN_POINT('',(-76.2078956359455,-0.781414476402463,-76.214035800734));
#1606=CARTESIAN_POINT('',(-76.1821243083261,-2.12850920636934,-76.1682520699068));
#1607=CARTESIAN_POINT('',(-76.0595674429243,-4.81607842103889,-75.9501971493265));
#1608=CARTESIAN_POINT('',(-75.9626572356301,-6.15653711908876,-75.7777039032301));
#1609=CARTESIAN_POINT('',(-75.6998544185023,-8.81819355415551,-75.3087169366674));
#1610=CARTESIAN_POINT('',(-75.5339662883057,-10.139392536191,-75.0122312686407));
#1611=CARTESIAN_POINT('',(-75.1444059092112,-12.7033456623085,-74.313375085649));
#1612=CARTESIAN_POINT('',(-74.9231896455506,-13.9471663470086,-73.9154939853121));
#1613=CARTESIAN_POINT('',(-74.4244218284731,-16.401654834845,-73.0142038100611));
#1614=CARTESIAN_POINT('',(-74.1468616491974,-17.6123175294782,-72.5107785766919));
#1615=CARTESIAN_POINT('',(-73.5410730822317,-19.9913251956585,-71.4055926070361));
#1616=CARTESIAN_POINT('',(-73.2129805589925,-21.1597735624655,-70.8040953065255));
#1617=CARTESIAN_POINT('',(-72.6866239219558,-22.8791207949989,-69.8322554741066));
#1618=CARTESIAN_POINT('',(-72.5055038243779,-23.4465848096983,-69.496775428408));
#1619=CARTESIAN_POINT('',(-72.1325257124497,-24.5700832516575,-68.8033143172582));
#1620=CARTESIAN_POINT('',(-71.9406685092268,-25.1261185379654,-68.4453349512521));
#1621=CARTESIAN_POINT('',(-71.7437693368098,-25.6762840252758,-68.076439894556));
#1622=B_SPLINE_CURVE_WITH_KNOTS('',3,(#1472,#1473,#1474,#1475,#1476,#1477,#1478,#1479,#1480,
#1481,#1482,#1483,#1484,#1485,#1486,#1487,#1488,#1489,#1490,#1491,#1492,#1493,#1494,#1495,#1496,
#1497,#1498,#1499,#1500,#1501,#1502,#1503,#1504,#1505,#1506,#1507,#1508,#1509,#1510,#1511,#1512,
#1513,#1514,#1515,#1516,#1517,#1518,#1519,#1520,#1521,#1522,#1523,#1524,#1525,#1526,#1527,#1528,
#1529,#1530,#1531,#1532,#1533,#1534,#1535,#1536,#1537,#1538,#1539,#1540,#1541,#1542,#1543,#1544,
#1545,#1546,#1547,#1548,#1549,#1550,#1551,#1552,#1553,#1554,#1555,#1556,#1557,#1558,#1559,#1560,
#1561,#1562,#1563,#1564,#1565,#1566,#1567,#1568,#1569,#1570,#1571,#1572,#1573,#1574,#1575,#1576,
#1577,#1578,#1579,#1580,#1581,#1582,#1583,#1584,#1585,#1586,#1587,#1588,#1589,#1590,#1591,#1592,
#1593,#1594,#1595,#1596,#1597,#1598,#1599,#1600,#1601,#1602,#1603,#1604,#1605,#1606,#1607,#1608,
#1609,#1610,#1611,#1612,#1613,#1614,#1615,#1616,#1617,#1618,#1619,#1620,#1621),.UNSPECIFIED.,
.F.,.F.,(4,2,2,2,2,2,2,2,2,2,2,2,2,2,2,2,2,2,2,2,2,2,2,2,2,2,2,2,2,2,2,2,2,2,2,2,2,2,2,2,2,2,2,
2,2,2,2,2,2,2,2,2,2,2,2,2,2,2,2,2,2,2,2,2,2,2,2,2,2,2,2,2,2,2,4),(0.,2.92928734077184,
5.85888262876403,11.7218095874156,17.6096173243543,23.4957956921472,29.41558780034,
35.3358745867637,41.2393728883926,47.1421495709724,52.3683943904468,57.5941964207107,
62.8246971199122,68.0554450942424,73.4115344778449,78.7676440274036,84.1223570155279,
89.477770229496,92.5895909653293,95.7007977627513,101.923323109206,108.157334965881,
114.39162718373,118.112926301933,121.833968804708,125.556606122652,129.278829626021,
132.996267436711,136.713838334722,144.142116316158,149.223660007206,154.304298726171,
156.838351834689,159.372066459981,161.905930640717,164.439799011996,166.99684976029,
169.553904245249,172.110986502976,174.668071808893,177.229277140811,179.790827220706,
182.352186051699,184.913857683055,189.972260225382,195.030483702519,200.092398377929,
205.155042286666,208.933866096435,212.713007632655,216.493136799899,220.273644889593,
227.844127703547,235.413575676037,243.040145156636,250.667664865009,254.473912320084,
258.279916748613,262.083922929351,265.888845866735,271.267867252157,276.645621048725,
279.332314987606,282.018515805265,284.705004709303,287.391621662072,292.775807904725,
298.160066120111,303.553782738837,308.94714912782,314.133986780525,319.321619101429,
324.495539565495,327.081584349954,329.667434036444),.UNSPECIFIED.);
#1623=EDGE_CURVE('E214',#350,#89,#1622,.T.);
#1624=ORIENTED_EDGE('',*,*,#1623,.T.);
#1625=ORIENTED_EDGE('',*,*,#92,.T.);
#1626=CARTESIAN_POINT('',(0.,0.,-95.2500000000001));
#1627=DIRECTION('',(0.,0.,1.));
#1628=DIRECTION('',(1.,0.,0.));
#1629=AXIS2_PLACEMENT_3D('',#1626,#1627,#1628);
#1630=CIRCLE('',#1629,76.2);
#1631=EDGE_CURVE('E299',#48,#91,#1630,.T.);
#1632=ORIENTED_EDGE('',*,*,#1631,.F.);
#1633=EDGE_LOOP('',(#413,#1017,#1018,#1019,#1020,#1624,#1625,#1632));
#1634=FACE_BOUND('',#1633,.T.);
#1635=ADVANCED_FACE('F228',(#1634),#412,.F.);
#1636=CARTESIAN_POINT('',(76.2,0.,-95.2500000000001));
#1637=DIRECTION('',(0.,0.,-1.));
#1638=DIRECTION('',(-1.,0.,0.));
#1639=AXIS2_PLACEMENT_3D('',#1636,#1637,#1638);
#1640=PLANE('',#1639);
#1641=ORIENTED_EDGE('',*,*,#131,.T.);
#1642=CARTESIAN_POINT('',(0.,0.,-95.2500000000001));
#1643=DIRECTION('',(0.,0.,1.));
#1644=DIRECTION('',(1.,0.,0.));
#1645=AXIS2_PLACEMENT_3D('',#1642,#1643,#1644);
#1646=CIRCLE('',#1645,25.4);
#1647=EDGE_CURVE('E315',#56,#128,#1646,.T.);
#1648=ORIENTED_EDGE('',*,*,#1647,.F.);
#1649=ORIENTED_EDGE('',*,*,#57,.T.);
#1650=ORIENTED_EDGE('',*,*,#1631,.T.);
#1651=EDGE_LOOP('',(#1641,#1648,#1649,#1650));
#1652=FACE_BOUND('',#1651,.T.);
#1653=ADVANCED_FACE('F367',(#1652),#1640,.F.);
#1654=CARTESIAN_POINT('',(0.,0.,212.191735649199));
#1655=DIRECTION('',(0.,0.,1.));
#1656=DIRECTION('',(1.,0.,0.));
#1657=AXIS2_PLACEMENT_3D('',#1654,#1655,#1656);
#1658=CYLINDRICAL_SURFACE('',#1657,25.4);
#1659=ORIENTED_EDGE('',*,*,#65,.T.);
#1660=ORIENTED_EDGE('',*,*,#1647,.T.);
#1661=ORIENTED_EDGE('',*,*,#129,.T.);
#1662=ORIENTED_EDGE('',*,*,#238,.F.);
#1663=EDGE_LOOP('',(#1659,#1660,#1661,#1662));
#1664=FACE_BOUND('',#1663,.T.);
#1665=ADVANCED_FACE('F255',(#1664),#1658,.F.);
#1666=CARTESIAN_POINT('',(-206.375,0.,0.));
#1667=DIRECTION('',(1.,0.,0.));
#1668=DIRECTION('',(0.,0.,-1.));
#1669=AXIS2_PLACEMENT_3D('',#1666,#1667,#1668);
#1670=CYLINDRICAL_SURFACE('',#1669,50.8);
#1671=ORIENTED_EDGE('',*,*,#157,.T.);
#1672=CARTESIAN_POINT('',(95.6583591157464,-22.8233635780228,45.3842932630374));
#1673=CARTESIAN_POINT('',(95.9208913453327,-22.3343275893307,45.630223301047));
#1674=CARTESIAN_POINT('',(96.176700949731,-21.8400740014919,45.8688762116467));
#1675=CARTESIAN_POINT('',(96.6740050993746,-20.8414087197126,46.3311836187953));
#1676=CARTESIAN_POINT('',(96.9154985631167,-20.3369962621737,46.5548369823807));
#1677=CARTESIAN_POINT('',(97.6173074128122,-18.8086876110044,47.2027302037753));
#1678=CARTESIAN_POINT('',(98.0547641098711,-17.7700668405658,47.6037284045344));
#1679=CARTESIAN_POINT('',(98.8624821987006,-15.6553933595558,48.3405190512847));
#1680=CARTESIAN_POINT('',(99.2325624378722,-14.5792487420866,48.676135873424));
#1681=CARTESIAN_POINT('',(99.8975861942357,-12.3974811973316,49.2769959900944));
#1682=CARTESIAN_POINT('',(100.192541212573,-11.2918628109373,49.5422500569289));
#1683=CARTESIAN_POINT('',(100.711955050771,-9.01279336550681,50.008154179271));
#1684=CARTESIAN_POINT('',(100.933139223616,-7.83839427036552,50.2058112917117));
#1685=CARTESIAN_POINT('',(101.283542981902,-5.47247743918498,50.5184692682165));
#1686=CARTESIAN_POINT('',(101.412756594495,-4.28095859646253,50.6334647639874));
#1687=CARTESIAN_POINT('',(101.576165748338,-1.89200818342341,50.7788347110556));
#1688=CARTESIAN_POINT('',(101.610527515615,-0.694590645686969,50.8093571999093));
#1689=CARTESIAN_POINT('',(101.583886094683,1.69908667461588,50.7856770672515));
#1690=CARTESIAN_POINT('',(101.522884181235,2.89534647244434,50.7314755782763));
#1691=CARTESIAN_POINT('',(101.361117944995,4.68010418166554,50.5874737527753));
#1692=CARTESIAN_POINT('',(101.2955878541,5.2728182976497,50.5291146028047));
#1693=CARTESIAN_POINT('',(101.141552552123,6.45453215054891,50.3917913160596));
#1694=CARTESIAN_POINT('',(101.053048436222,7.04353206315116,50.3128281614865));
#1695=CARTESIAN_POINT('',(100.853547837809,8.21667590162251,50.1346011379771));
#1696=CARTESIAN_POINT('',(100.742553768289,8.80082034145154,50.0353394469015));
#1697=CARTESIAN_POINT('',(100.498656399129,9.96339300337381,49.8168728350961));
#1698=CARTESIAN_POINT('',(100.365749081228,10.5418201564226,49.6976642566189));
#1699=CARTESIAN_POINT('',(99.9348880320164,12.2681159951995,49.3104896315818));
#1700=CARTESIAN_POINT('',(99.6049593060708,13.4060429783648,49.0131207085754));
#1701=CARTESIAN_POINT('',(98.8664355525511,15.6482772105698,48.3439872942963));
#1702=CARTESIAN_POINT('',(98.4578220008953,16.7525764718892,47.9722052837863));
#1703=CARTESIAN_POINT('',(97.6996034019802,18.6043166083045,47.2778066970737));
#1704=CARTESIAN_POINT('',(97.3677224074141,19.3616193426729,46.9726405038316));
#1705=CARTESIAN_POINT('',(96.6713572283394,20.8548812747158,46.328983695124));
#1706=CARTESIAN_POINT('',(96.3068809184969,21.5908455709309,45.9905011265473));
#1707=CARTESIAN_POINT('',(95.5480171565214,23.0406733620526,45.2815511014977));
#1708=CARTESIAN_POINT('',(95.153614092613,23.7545250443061,44.9110669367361));
#1709=CARTESIAN_POINT('',(94.3381124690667,25.1586659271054,44.1398159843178));
#1710=CARTESIAN_POINT('',(93.9170122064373,25.8489536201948,43.7390472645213));
#1711=CARTESIAN_POINT('',(92.616296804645,27.8861708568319,42.4916501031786));
#1712=CARTESIAN_POINT('',(91.7007881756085,29.1965861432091,41.6013409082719));
#1713=CARTESIAN_POINT('',(89.7998450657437,31.7141322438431,39.7155969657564));
#1714=CARTESIAN_POINT('',(88.8144193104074,32.921275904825,38.7201753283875));
#1715=CARTESIAN_POINT('',(86.8061035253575,35.2212942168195,36.6399618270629));
#1716=CARTESIAN_POINT('',(85.7835493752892,36.3149570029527,35.5558951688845));
#1717=CARTESIAN_POINT('',(83.7193271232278,38.3963833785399,33.2973953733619));
#1718=CARTESIAN_POINT('',(82.6776564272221,39.3841324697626,32.1229499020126));
#1719=CARTESIAN_POINT('',(81.1228900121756,40.7834111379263,30.2975224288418));
#1720=CARTESIAN_POINT('',(80.6062456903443,41.2358555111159,29.6788275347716));
#1721=CARTESIAN_POINT('',(79.5790321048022,42.1132544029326,28.4201042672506));
#1722=CARTESIAN_POINT('',(79.0684622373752,42.538211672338,27.7800780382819));
#1723=CARTESIAN_POINT('',(78.0575774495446,43.3600424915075,26.4790219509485));
#1724=CARTESIAN_POINT('',(77.5572598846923,43.7569233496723,25.8179976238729));
#1725=CARTESIAN_POINT('',(76.5712251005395,44.522053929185,24.4749658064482));
#1726=CARTESIAN_POINT('',(76.0855066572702,44.8903060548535,23.792960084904));
#1727=CARTESIAN_POINT('',(74.9716474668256,45.7176026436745,22.1726435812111));
#1728=CARTESIAN_POINT('',(74.3511834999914,46.1649879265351,21.2259751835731));
#1729=CARTESIAN_POINT('',(73.1580411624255,47.0045555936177,19.2955766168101));
#1730=CARTESIAN_POINT('',(72.5853559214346,47.3967459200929,18.3118518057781));
#1731=CARTESIAN_POINT('',(71.5025698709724,48.1226753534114,16.3089535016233));
#1732=CARTESIAN_POINT('',(70.992423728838,48.4564568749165,15.2898063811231));
#1733=CARTESIAN_POINT('',(70.0499541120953,49.0622881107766,13.2172870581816));
#1734=CARTESIAN_POINT('',(69.6176333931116,49.3343356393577,12.163913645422));
#1735=CARTESIAN_POINT('',(69.0374013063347,49.6944800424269,10.5549113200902));
#1736=CARTESIAN_POINT('',(68.8544337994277,49.8070946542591,10.0102302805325));
#1737=CARTESIAN_POINT('',(68.5146447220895,50.0149164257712,8.91398975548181));
#1738=CARTESIAN_POINT('',(68.3578199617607,50.1101257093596,8.36243111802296));
#1739=CARTESIAN_POINT('',(68.0721736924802,50.2826514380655,7.25327561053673));
#1740=CARTESIAN_POINT('',(67.9433542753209,50.3599665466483,6.69567829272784));
#1741=CARTESIAN_POINT('',(67.7153947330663,50.4962431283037,5.57562848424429));
#1742=CARTESIAN_POINT('',(67.6162506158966,50.5552070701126,5.01317665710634));
#1743=CARTESIAN_POINT('',(67.4490997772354,50.6543469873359,3.88548438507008));
#1744=CARTESIAN_POINT('',(67.3810432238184,50.6945530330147,3.3202498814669));
#1745=CARTESIAN_POINT('',(67.2767938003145,50.7560521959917,2.18744461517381));
#1746=CARTESIAN_POINT('',(67.2406008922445,50.7773453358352,1.61987385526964));
#1747=CARTESIAN_POINT('',(67.2006040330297,50.8008728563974,0.483834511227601));
#1748=CARTESIAN_POINT('',(67.196799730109,50.803107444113,-0.0846340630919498));
#1749=CARTESIAN_POINT('',(67.2216349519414,50.7885029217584,-1.22100879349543));
#1750=CARTESIAN_POINT('',(67.2502744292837,50.7716638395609,-1.78891495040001));
#1751=CARTESIAN_POINT('',(67.3391749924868,50.7192664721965,-2.91757958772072));
#1752=CARTESIAN_POINT('',(67.3991470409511,50.6838792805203,-3.47835619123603));
#1753=CARTESIAN_POINT('',(67.5496990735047,50.594722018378,-4.59660008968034));
#1754=CARTESIAN_POINT('',(67.640279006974,50.540951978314,-5.15406739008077));
#1755=CARTESIAN_POINT('',(67.85083003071,50.4153628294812,-6.2644482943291));
#1756=CARTESIAN_POINT('',(67.9707993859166,50.3435447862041,-6.81736216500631));
#1757=CARTESIAN_POINT('',(68.2385946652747,50.1822749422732,-7.91761554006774));
#1758=CARTESIAN_POINT('',(68.3864243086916,50.0928207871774,-8.46495428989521));
#1759=CARTESIAN_POINT('',(68.8699783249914,49.7981616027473,-10.1000523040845));
#1760=CARTESIAN_POINT('',(69.2452312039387,49.5669743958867,-11.1781387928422));
#1761=CARTESIAN_POINT('',(70.0848532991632,49.0396910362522,-13.3021702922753));
#1762=CARTESIAN_POINT('',(70.5492383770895,48.7435833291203,-14.3481095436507));
#1763=CARTESIAN_POINT('',(71.7821872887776,47.9394220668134,-16.8801515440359));
#1764=CARTESIAN_POINT('',(72.592184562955,47.3966405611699,-18.3464575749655));
#1765=CARTESIAN_POINT('',(73.8876500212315,46.4928565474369,-20.4854747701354));
#1766=CARTESIAN_POINT('',(74.3331075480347,46.1764932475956,-21.1887173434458));
#1767=CARTESIAN_POINT('',(75.2457645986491,45.5147786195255,-22.5750880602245));
#1768=CARTESIAN_POINT('',(75.712963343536,45.1694283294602,-23.2582169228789));
#1769=CARTESIAN_POINT('',(76.6647760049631,44.4501740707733,-24.6049930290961));
#1770=CARTESIAN_POINT('',(77.1494115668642,44.0762339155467,-25.268614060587));
#1771=CARTESIAN_POINT('',(78.1311418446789,43.300828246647,-26.5754695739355));
#1772=CARTESIAN_POINT('',(78.6282379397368,42.8993596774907,-27.2187017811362));
#1773=CARTESIAN_POINT('',(79.630526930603,42.0696630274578,-28.484306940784));
#1774=CARTESIAN_POINT('',(80.1357162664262,41.641446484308,-29.1066887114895));
#1775=CARTESIAN_POINT('',(81.1506351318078,40.7585342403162,-30.3306999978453));
#1776=CARTESIAN_POINT('',(81.6603649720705,40.3038367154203,-30.9323280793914));
#1777=CARTESIAN_POINT('',(83.0254737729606,39.0523413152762,-32.5138406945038));
#1778=CARTESIAN_POINT('',(83.8818174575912,38.2318788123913,-33.4748013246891));
#1779=CARTESIAN_POINT('',(85.5817602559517,36.5190731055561,-35.3354826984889));
#1780=CARTESIAN_POINT('',(86.4253599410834,35.6267331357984,-36.2352061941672));
#1781=CARTESIAN_POINT('',(88.0841631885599,33.7728068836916,-37.9689975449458));
#1782=CARTESIAN_POINT('',(88.8994162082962,32.81135122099,-38.8031833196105));
#1783=CARTESIAN_POINT('',(90.0916015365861,31.3175821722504,-40.0032117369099));
#1784=CARTESIAN_POINT('',(90.4838775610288,30.8110663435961,-40.3946762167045));
#1785=CARTESIAN_POINT('',(91.2566655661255,29.7808839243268,-41.1600634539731));
#1786=CARTESIAN_POINT('',(91.6371752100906,29.2572139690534,-41.533982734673));
#1787=CARTESIAN_POINT('',(92.6541860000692,27.8093645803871,-42.5266017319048));
#1788=CARTESIAN_POINT('',(93.2774553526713,26.8686394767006,-43.1274124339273));
#1789=CARTESIAN_POINT('',(94.4751918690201,24.9394828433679,-44.2709769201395));
#1790=CARTESIAN_POINT('',(95.0496654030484,23.9510575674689,-44.8137382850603));
#1791=CARTESIAN_POINT('',(96.14161071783,21.9286689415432,-45.8372997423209));
#1792=CARTESIAN_POINT('',(96.6590675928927,20.8946937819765,-46.3180836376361));
#1793=CARTESIAN_POINT('',(97.6285042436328,18.7850207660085,-47.2130889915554));
#1794=CARTESIAN_POINT('',(98.0804842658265,17.7093230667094,-47.6273107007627));
#1795=CARTESIAN_POINT('',(98.9013800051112,15.5464983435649,-48.3758719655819));
#1796=CARTESIAN_POINT('',(99.27199204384,14.4602278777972,-48.7118540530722));
#1797=CARTESIAN_POINT('',(99.9366065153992,12.257841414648,-49.312146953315));
#1798=CARTESIAN_POINT('',(100.230612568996,11.141726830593,-49.57646115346));
#1799=CARTESIAN_POINT('',(100.736153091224,8.88713127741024,-50.0297878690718));
#1800=CARTESIAN_POINT('',(100.94776140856,7.74867130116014,-50.2188678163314));
#1801=CARTESIAN_POINT('',(101.284611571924,5.45582824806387,-50.5194128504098));
#1802=CARTESIAN_POINT('',(101.409846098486,4.30144383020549,-50.6308713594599));
#1803=CARTESIAN_POINT('',(101.581700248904,1.83487024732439,-50.7837628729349));
#1804=CARTESIAN_POINT('',(101.616044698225,0.521597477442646,-50.8142634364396));
#1805=CARTESIAN_POINT('',(101.57011671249,-2.10256925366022,-50.7734352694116));
#1806=CARTESIAN_POINT('',(101.489830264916,-3.41346290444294,-50.7020940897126));
#1807=CARTESIAN_POINT('',(101.216432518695,-6.02431164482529,-50.4586118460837));
#1808=CARTESIAN_POINT('',(101.023001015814,-7.32422502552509,-50.2861847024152));
#1809=CARTESIAN_POINT('',(100.528221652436,-9.89778467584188,-49.8435430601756));
#1810=CARTESIAN_POINT('',(100.226882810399,-11.1714331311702,-49.5733367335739));
#1811=CARTESIAN_POINT('',(99.5258635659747,-13.6754797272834,-48.9415909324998));
#1812=CARTESIAN_POINT('',(99.126751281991,-14.9060823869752,-48.5805787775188));
#1813=CARTESIAN_POINT('',(98.2384451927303,-17.3237810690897,-47.7718778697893));
#1814=CARTESIAN_POINT('',(97.7492264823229,-18.5108649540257,-47.3241651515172));
#1815=CARTESIAN_POINT('',(96.6933075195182,-20.8300441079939,-46.350019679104));
#1816=CARTESIAN_POINT('',(96.1269434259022,-21.9623505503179,-45.8239275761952));
#1817=CARTESIAN_POINT('',(95.2267083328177,-23.6193019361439,-44.9794714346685));
#1818=CARTESIAN_POINT('',(94.9182882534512,-24.1645337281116,-44.6888678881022));
#1819=CARTESIAN_POINT('',(94.2858711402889,-25.2409363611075,-44.0898431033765));
#1820=CARTESIAN_POINT('',(93.9618757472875,-25.7721086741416,-43.7814237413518));
#1821=CARTESIAN_POINT('',(93.6307408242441,-26.2961287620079,-43.464394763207));
#1822=B_SPLINE_CURVE_WITH_KNOTS('',3,(#1672,#1673,#1674,#1675,#1676,#1677,#1678,#1679,#1680,
#1681,#1682,#1683,#1684,#1685,#1686,#1687,#1688,#1689,#1690,#1691,#1692,#1693,#1694,#1695,#1696,
#1697,#1698,#1699,#1700,#1701,#1702,#1703,#1704,#1705,#1706,#1707,#1708,#1709,#1710,#1711,#1712,
#1713,#1714,#1715,#1716,#1717,#1718,#1719,#1720,#1721,#1722,#1723,#1724,#1725,#1726,#1727,#1728,
#1729,#1730,#1731,#1732,#1733,#1734,#1735,#1736,#1737,#1738,#1739,#1740,#1741,#1742,#1743,#1744,
#1745,#1746,#1747,#1748,#1749,#1750,#1751,#1752,#1753,#1754,#1755,#1756,#1757,#1758,#1759,#1760,
#1761,#1762,#1763,#1764,#1765,#1766,#1767,#1768,#1769,#1770,#1771,#1772,#1773,#1774,#1775,#1776,
#1777,#1778,#1779,#1780,#1781,#1782,#1783,#1784,#1785,#1786,#1787,#1788,#1789,#1790,#1791,#1792,
#1793,#1794,#1795,#1796,#1797,#1798,#1799,#1800,#1801,#1802,#1803,#1804,#1805,#1806,#1807,#1808,
#1809,#1810,#1811,#1812,#1813,#1814,#1815,#1816,#1817,#1818,#1819,#1820,#1821),.UNSPECIFIED.,
.F.,.F.,(4,2,2,2,2,2,2,2,2,2,2,2,2,2,2,2,2,2,2,2,2,2,2,2,2,2,2,2,2,2,2,2,2,2,2,2,2,2,2,2,2,2,2,
2,2,2,2,2,2,2,2,2,2,2,2,2,2,2,2,2,2,2,2,2,2,2,2,2,2,2,2,2,2,2,4),(0.,2.58584968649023,
5.17189447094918,10.3458149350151,15.5334472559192,20.7202849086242,26.113651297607,
31.5073679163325,36.8916261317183,42.2758123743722,44.9624293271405,47.6489182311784,
50.3351190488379,53.0218129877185,58.3995667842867,63.7785881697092,67.5835111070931,
71.3875172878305,75.1935217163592,78.999769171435,86.6272888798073,94.2538583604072,
101.823306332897,109.39378914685,113.174297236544,116.954426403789,120.733567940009,
124.512391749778,129.575035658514,134.636950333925,139.695173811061,144.753576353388,
147.315247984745,149.876606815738,152.438156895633,154.999362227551,157.556447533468,
160.113529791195,162.670584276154,165.227635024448,167.761503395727,170.295367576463,
172.829082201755,175.363135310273,180.443774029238,185.525317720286,192.953595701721,
196.671166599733,200.388604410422,204.110827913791,207.833465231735,211.55450773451,
215.275806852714,221.510099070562,227.744110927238,233.966636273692,237.077843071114,
240.189663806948,245.545077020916,250.89979000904,256.255899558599,261.611988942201,
266.842736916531,272.073237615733,277.299039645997,282.525284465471,288.428061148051,
294.33155944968,300.251846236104,306.171638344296,312.057816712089,317.945624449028,
323.80855140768,326.738146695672,329.667434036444),.UNSPECIFIED.);
#1823=EDGE_CURVE('E278',#148,#29,#1822,.T.);
#1824=ORIENTED_EDGE('',*,*,#1823,.T.);
#1825=ORIENTED_EDGE('',*,*,#32,.T.);
#1826=ORIENTED_EDGE('',*,*,#199,.T.);
#1827=EDGE_LOOP('',(#1671,#1824,#1825,#1826));
#1828=FACE_BOUND('',#1827,.T.);
#1829=ADVANCED_FACE('F251',(#1828),#1670,.F.);
#1830=ORIENTED_EDGE('',*,*,#109,.T.);
#1831=CARTESIAN_POINT('',(-95.6583591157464,-22.8233635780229,-45.3842932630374));
#1832=CARTESIAN_POINT('',(-95.9208913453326,-22.3343275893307,-45.630223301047));
#1833=CARTESIAN_POINT('',(-96.176700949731,-21.8400740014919,-45.8688762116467));
#1834=CARTESIAN_POINT('',(-96.6740050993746,-20.8414087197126,-46.3311836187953));
#1835=CARTESIAN_POINT('',(-96.9154985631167,-20.3369962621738,-46.5548369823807));
#1836=CARTESIAN_POINT('',(-97.6173074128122,-18.8086876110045,-47.2027302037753));
#1837=CARTESIAN_POINT('',(-98.0547641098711,-17.7700668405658,-47.6037284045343));
#1838=CARTESIAN_POINT('',(-98.8624821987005,-15.6553933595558,-48.3405190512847));
#1839=CARTESIAN_POINT('',(-99.2325624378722,-14.5792487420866,-48.676135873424));
#1840=CARTESIAN_POINT('',(-99.8975861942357,-12.3974811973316,-49.2769959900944));
#1841=CARTESIAN_POINT('',(-100.192541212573,-11.2918628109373,-49.5422500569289));
#1842=CARTESIAN_POINT('',(-100.711955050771,-9.01279336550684,-50.008154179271));
#1843=CARTESIAN_POINT('',(-100.933139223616,-7.83839427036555,-50.2058112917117));
#1844=CARTESIAN_POINT('',(-101.283542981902,-5.47247743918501,-50.5184692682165));
#1845=CARTESIAN_POINT('',(-101.412756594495,-4.28095859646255,-50.6334647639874));
#1846=CARTESIAN_POINT('',(-101.576165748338,-1.89200818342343,-50.7788347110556));
#1847=CARTESIAN_POINT('',(-101.610527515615,-0.694590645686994,-50.8093571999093));
#1848=CARTESIAN_POINT('',(-101.583886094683,1.69908667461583,-50.7856770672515));
#1849=CARTESIAN_POINT('',(-101.522884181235,2.89534647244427,-50.7314755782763));
#1850=CARTESIAN_POINT('',(-101.361117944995,4.6801041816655,-50.5874737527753));
#1851=CARTESIAN_POINT('',(-101.2955878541,5.27281829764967,-50.5291146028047));
#1852=CARTESIAN_POINT('',(-101.141552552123,6.45453215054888,-50.3917913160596));
#1853=CARTESIAN_POINT('',(-101.053048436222,7.04353206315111,-50.3128281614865));
#1854=CARTESIAN_POINT('',(-100.853547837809,8.21667590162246,-50.1346011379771));
#1855=CARTESIAN_POINT('',(-100.742553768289,8.80082034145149,-50.0353394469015));
#1856=CARTESIAN_POINT('',(-100.498656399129,9.96339300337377,-49.8168728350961));
#1857=CARTESIAN_POINT('',(-100.365749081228,10.5418201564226,-49.6976642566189));
#1858=CARTESIAN_POINT('',(-99.9348880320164,12.2681159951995,-49.3104896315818));
#1859=CARTESIAN_POINT('',(-99.6049593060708,13.4060429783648,-49.0131207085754));
#1860=CARTESIAN_POINT('',(-98.8664355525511,15.6482772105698,-48.3439872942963));
#1861=CARTESIAN_POINT('',(-98.4578220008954,16.7525764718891,-47.9722052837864));
#1862=CARTESIAN_POINT('',(-97.6996034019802,18.6043166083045,-47.2778066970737));
#1863=CARTESIAN_POINT('',(-97.3677224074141,19.3616193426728,-46.9726405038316));
#1864=CARTESIAN_POINT('',(-96.6713572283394,20.8548812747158,-46.328983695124));
#1865=CARTESIAN_POINT('',(-96.306880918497,21.5908455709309,-45.9905011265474));
#1866=CARTESIAN_POINT('',(-95.5480171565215,23.0406733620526,-45.2815511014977));
#1867=CARTESIAN_POINT('',(-95.153614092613,23.754525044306,-44.9110669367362));
#1868=CARTESIAN_POINT('',(-94.3381124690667,25.1586659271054,-44.1398159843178));
#1869=CARTESIAN_POINT('',(-93.9170122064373,25.8489536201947,-43.7390472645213));
#1870=CARTESIAN_POINT('',(-92.616296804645,27.8861708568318,-42.4916501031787));
#1871=CARTESIAN_POINT('',(-91.7007881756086,29.1965861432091,-41.601340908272));
#1872=CARTESIAN_POINT('',(-89.7998450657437,31.7141322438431,-39.7155969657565));
#1873=CARTESIAN_POINT('',(-88.8144193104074,32.921275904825,-38.7201753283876));
#1874=CARTESIAN_POINT('',(-86.8061035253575,35.2212942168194,-36.639961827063));
#1875=CARTESIAN_POINT('',(-85.7835493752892,36.3149570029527,-35.5558951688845));
#1876=CARTESIAN_POINT('',(-83.7193271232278,38.3963833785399,-33.2973953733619));
#1877=CARTESIAN_POINT('',(-82.6776564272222,39.3841324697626,-32.1229499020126));
#1878=CARTESIAN_POINT('',(-81.1228900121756,40.7834111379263,-30.2975224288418));
#1879=CARTESIAN_POINT('',(-80.6062456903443,41.2358555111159,-29.6788275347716));
#1880=CARTESIAN_POINT('',(-79.5790321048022,42.1132544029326,-28.4201042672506));
#1881=CARTESIAN_POINT('',(-79.0684622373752,42.538211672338,-27.7800780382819));
#1882=CARTESIAN_POINT('',(-78.0575774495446,43.3600424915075,-26.4790219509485));
#1883=CARTESIAN_POINT('',(-77.5572598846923,43.7569233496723,-25.8179976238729));
#1884=CARTESIAN_POINT('',(-76.5712251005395,44.522053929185,-24.4749658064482));
#1885=CARTESIAN_POINT('',(-76.0855066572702,44.8903060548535,-23.792960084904));
#1886=CARTESIAN_POINT('',(-74.9716474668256,45.7176026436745,-22.1726435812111));
#1887=CARTESIAN_POINT('',(-74.3511834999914,46.1649879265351,-21.2259751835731));
#1888=CARTESIAN_POINT('',(-73.1580411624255,47.0045555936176,-19.2955766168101));
#1889=CARTESIAN_POINT('',(-72.5853559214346,47.3967459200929,-18.3118518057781));
#1890=CARTESIAN_POINT('',(-71.5025698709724,48.1226753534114,-16.3089535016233));
#1891=CARTESIAN_POINT('',(-70.992423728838,48.4564568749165,-15.2898063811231));
#1892=CARTESIAN_POINT('',(-70.0499541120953,49.0622881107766,-13.2172870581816));
#1893=CARTESIAN_POINT('',(-69.6176333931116,49.3343356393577,-12.163913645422));
#1894=CARTESIAN_POINT('',(-69.0374013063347,49.6944800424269,-10.5549113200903));
#1895=CARTESIAN_POINT('',(-68.8544337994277,49.8070946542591,-10.0102302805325));
#1896=CARTESIAN_POINT('',(-68.5146447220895,50.0149164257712,-8.91398975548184));
#1897=CARTESIAN_POINT('',(-68.3578199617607,50.1101257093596,-8.362431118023));
#1898=CARTESIAN_POINT('',(-68.0721736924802,50.2826514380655,-7.25327561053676));
#1899=CARTESIAN_POINT('',(-67.9433542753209,50.3599665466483,-6.69567829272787));
#1900=CARTESIAN_POINT('',(-67.7153947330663,50.4962431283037,-5.57562848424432));
#1901=CARTESIAN_POINT('',(-67.6162506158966,50.5552070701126,-5.01317665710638));
#1902=CARTESIAN_POINT('',(-67.4490997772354,50.6543469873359,-3.88548438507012));
#1903=CARTESIAN_POINT('',(-67.3810432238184,50.6945530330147,-3.32024988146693));
#1904=CARTESIAN_POINT('',(-67.2767938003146,50.7560521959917,-2.18744461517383));
#1905=CARTESIAN_POINT('',(-67.2406008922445,50.7773453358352,-1.61987385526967));
#1906=CARTESIAN_POINT('',(-67.2006040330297,50.8008728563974,-0.483834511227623));
#1907=CARTESIAN_POINT('',(-67.196799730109,50.803107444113,0.0846340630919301));
#1908=CARTESIAN_POINT('',(-67.2216349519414,50.7885029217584,1.22100879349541));
#1909=CARTESIAN_POINT('',(-67.2502744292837,50.7716638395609,1.78891495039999));
#1910=CARTESIAN_POINT('',(-67.3391749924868,50.7192664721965,2.9175795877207));
#1911=CARTESIAN_POINT('',(-67.3991470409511,50.6838792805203,3.47835619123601));
#1912=CARTESIAN_POINT('',(-67.5496990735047,50.594722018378,4.59660008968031));
#1913=CARTESIAN_POINT('',(-67.640279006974,50.540951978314,5.15406739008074));
#1914=CARTESIAN_POINT('',(-67.8508300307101,50.4153628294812,6.26444829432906));
#1915=CARTESIAN_POINT('',(-67.9707993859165,50.3435447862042,6.81736216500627));
#1916=CARTESIAN_POINT('',(-68.2385946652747,50.1822749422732,7.9176155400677));
#1917=CARTESIAN_POINT('',(-68.3864243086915,50.0928207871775,8.46495428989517));
#1918=CARTESIAN_POINT('',(-68.8699783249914,49.7981616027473,10.1000523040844));
#1919=CARTESIAN_POINT('',(-69.2452312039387,49.5669743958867,11.1781387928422));
#1920=CARTESIAN_POINT('',(-70.0848532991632,49.0396910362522,13.3021702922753));
#1921=CARTESIAN_POINT('',(-70.5492383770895,48.7435833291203,14.3481095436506));
#1922=CARTESIAN_POINT('',(-71.7821872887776,47.9394220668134,16.8801515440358));
#1923=CARTESIAN_POINT('',(-72.5921845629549,47.3966405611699,18.3464575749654));
#1924=CARTESIAN_POINT('',(-73.8876500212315,46.4928565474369,20.4854747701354));
#1925=CARTESIAN_POINT('',(-74.3331075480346,46.1764932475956,21.1887173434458));
#1926=CARTESIAN_POINT('',(-75.245764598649,45.5147786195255,22.5750880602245));
#1927=CARTESIAN_POINT('',(-75.7129633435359,45.1694283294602,23.2582169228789));
#1928=CARTESIAN_POINT('',(-76.6647760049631,44.4501740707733,24.604993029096));
#1929=CARTESIAN_POINT('',(-77.1494115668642,44.0762339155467,25.2686140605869));
#1930=CARTESIAN_POINT('',(-78.1311418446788,43.3008282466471,26.5754695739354));
#1931=CARTESIAN_POINT('',(-78.6282379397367,42.8993596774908,27.2187017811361));
#1932=CARTESIAN_POINT('',(-79.630526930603,42.0696630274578,28.484306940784));
#1933=CARTESIAN_POINT('',(-80.1357162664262,41.641446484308,29.1066887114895));
#1934=CARTESIAN_POINT('',(-81.1506351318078,40.7585342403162,30.3306999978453));
#1935=CARTESIAN_POINT('',(-81.6603649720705,40.3038367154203,30.9323280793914));
#1936=CARTESIAN_POINT('',(-83.0254737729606,39.0523413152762,32.5138406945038));
#1937=CARTESIAN_POINT('',(-83.8818174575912,38.2318788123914,33.4748013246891));
#1938=CARTESIAN_POINT('',(-85.5817602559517,36.5190731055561,35.3354826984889));
#1939=CARTESIAN_POINT('',(-86.4253599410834,35.6267331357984,36.2352061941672));
#1940=CARTESIAN_POINT('',(-88.0841631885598,33.7728068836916,37.9689975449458));
#1941=CARTESIAN_POINT('',(-88.8994162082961,32.8113512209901,38.8031833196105));
#1942=CARTESIAN_POINT('',(-90.091601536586,31.3175821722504,40.0032117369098));
#1943=CARTESIAN_POINT('',(-90.4838775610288,30.8110663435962,40.3946762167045));
#1944=CARTESIAN_POINT('',(-91.2566655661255,29.7808839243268,41.160063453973));
#1945=CARTESIAN_POINT('',(-91.6371752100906,29.2572139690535,41.533982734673));
#1946=CARTESIAN_POINT('',(-92.6541860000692,27.8093645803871,42.5266017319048));
#1947=CARTESIAN_POINT('',(-93.2774553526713,26.8686394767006,43.1274124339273));
#1948=CARTESIAN_POINT('',(-94.47519186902,24.9394828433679,44.2709769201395));
#1949=CARTESIAN_POINT('',(-95.0496654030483,23.9510575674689,44.8137382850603));
#1950=CARTESIAN_POINT('',(-96.1416107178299,21.9286689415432,45.8372997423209));
#1951=CARTESIAN_POINT('',(-96.6590675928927,20.8946937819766,46.3180836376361));
#1952=CARTESIAN_POINT('',(-97.6285042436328,18.7850207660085,47.2130889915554));
#1953=CARTESIAN_POINT('',(-98.0804842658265,17.7093230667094,47.6273107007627));
#1954=CARTESIAN_POINT('',(-98.9013800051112,15.5464983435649,48.3758719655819));
#1955=CARTESIAN_POINT('',(-99.27199204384,14.4602278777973,48.7118540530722));
#1956=CARTESIAN_POINT('',(-99.9366065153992,12.257841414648,49.312146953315));
#1957=CARTESIAN_POINT('',(-100.230612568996,11.1417268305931,49.57646115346));
#1958=CARTESIAN_POINT('',(-100.736153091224,8.88713127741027,50.0297878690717));
#1959=CARTESIAN_POINT('',(-100.94776140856,7.74867130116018,50.2188678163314));
#1960=CARTESIAN_POINT('',(-101.284611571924,5.45582824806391,50.5194128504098));
#1961=CARTESIAN_POINT('',(-101.409846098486,4.30144383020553,50.6308713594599));
#1962=CARTESIAN_POINT('',(-101.581700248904,1.83487024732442,50.7837628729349));
#1963=CARTESIAN_POINT('',(-101.616044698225,0.521597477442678,50.8142634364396));
#1964=CARTESIAN_POINT('',(-101.57011671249,-2.10256925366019,50.7734352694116));
#1965=CARTESIAN_POINT('',(-101.489830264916,-3.41346290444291,50.7020940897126));
#1966=CARTESIAN_POINT('',(-101.216432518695,-6.02431164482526,50.4586118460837));
#1967=CARTESIAN_POINT('',(-101.023001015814,-7.32422502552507,50.2861847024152));
#1968=CARTESIAN_POINT('',(-100.528221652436,-9.89778467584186,49.8435430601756));
#1969=CARTESIAN_POINT('',(-100.226882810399,-11.1714331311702,49.5733367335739));
#1970=CARTESIAN_POINT('',(-99.5258635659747,-13.6754797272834,48.9415909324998));
#1971=CARTESIAN_POINT('',(-99.1267512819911,-14.9060823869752,48.5805787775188));
#1972=CARTESIAN_POINT('',(-98.2384451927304,-17.3237810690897,47.7718778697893));
#1973=CARTESIAN_POINT('',(-97.7492264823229,-18.5108649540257,47.3241651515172));
#1974=CARTESIAN_POINT('',(-96.6933075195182,-20.8300441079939,46.350019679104));
#1975=CARTESIAN_POINT('',(-96.1269434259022,-21.9623505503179,45.8239275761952));
#1976=CARTESIAN_POINT('',(-95.2267083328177,-23.6193019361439,44.9794714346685));
#1977=CARTESIAN_POINT('',(-94.9182882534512,-24.1645337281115,44.6888678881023));
#1978=CARTESIAN_POINT('',(-94.2858711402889,-25.2409363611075,44.0898431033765));
#1979=CARTESIAN_POINT('',(-93.9618757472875,-25.7721086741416,43.7814237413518));
#1980=CARTESIAN_POINT('',(-93.6307408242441,-26.2961287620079,43.464394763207));
#1981=B_SPLINE_CURVE_WITH_KNOTS('',3,(#1831,#1832,#1833,#1834,#1835,#1836,#1837,#1838,#1839,
#1840,#1841,#1842,#1843,#1844,#1845,#1846,#1847,#1848,#1849,#1850,#1851,#1852,#1853,#1854,#1855,
#1856,#1857,#1858,#1859,#1860,#1861,#1862,#1863,#1864,#1865,#1866,#1867,#1868,#1869,#1870,#1871,
#1872,#1873,#1874,#1875,#1876,#1877,#1878,#1879,#1880,#1881,#1882,#1883,#1884,#1885,#1886,#1887,
#1888,#1889,#1890,#1891,#1892,#1893,#1894,#1895,#1896,#1897,#1898,#1899,#1900,#1901,#1902,#1903,
#1904,#1905,#1906,#1907,#1908,#1909,#1910,#1911,#1912,#1913,#1914,#1915,#1916,#1917,#1918,#1919,
#1920,#1921,#1922,#1923,#1924,#1925,#1926,#1927,#1928,#1929,#1930,#1931,#1932,#1933,#1934,#1935,
#1936,#1937,#1938,#1939,#1940,#1941,#1942,#1943,#1944,#1945,#1946,#1947,#1948,#1949,#1950,#1951,
#1952,#1953,#1954,#1955,#1956,#1957,#1958,#1959,#1960,#1961,#1962,#1963,#1964,#1965,#1966,#1967,
#1968,#1969,#1970,#1971,#1972,#1973,#1974,#1975,#1976,#1977,#1978,#1979,#1980),.UNSPECIFIED.,
.F.,.F.,(4,2,2,2,2,2,2,2,2,2,2,2,2,2,2,2,2,2,2,2,2,2,2,2,2,2,2,2,2,2,2,2,2,2,2,2,2,2,2,2,2,2,2,
2,2,2,2,2,2,2,2,2,2,2,2,2,2,2,2,2,2,2,2,2,2,2,2,2,2,2,2,2,2,2,4),(0.,2.58584968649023,
5.17189447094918,10.3458149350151,15.5334472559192,20.7202849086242,26.113651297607,
31.5073679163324,36.8916261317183,42.2758123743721,44.9624293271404,47.6489182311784,
50.3351190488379,53.0218129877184,58.3995667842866,63.7785881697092,67.583511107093,
71.3875172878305,75.1935217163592,78.9997691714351,86.6272888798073,94.2538583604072,
101.823306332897,109.39378914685,113.174297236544,116.954426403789,120.733567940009,
124.512391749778,129.575035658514,134.636950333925,139.695173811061,144.753576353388,
147.315247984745,149.876606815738,152.438156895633,154.999362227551,157.556447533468,
160.113529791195,162.670584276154,165.227635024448,167.761503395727,170.295367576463,
172.829082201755,175.363135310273,180.443774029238,185.525317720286,192.953595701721,
196.671166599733,200.388604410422,204.110827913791,207.833465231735,211.55450773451,
215.275806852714,221.510099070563,227.744110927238,233.966636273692,237.077843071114,
240.189663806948,245.545077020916,250.89979000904,256.255899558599,261.611988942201,
266.842736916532,272.073237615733,277.299039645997,282.525284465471,288.428061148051,
294.33155944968,300.251846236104,306.171638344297,312.057816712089,317.945624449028,
323.80855140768,326.738146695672,329.667434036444),.UNSPECIFIED.);
#1982=EDGE_CURVE('E45',#100,#341,#1981,.T.);
#1983=ORIENTED_EDGE('',*,*,#1982,.T.);
#1984=ORIENTED_EDGE('',*,*,#342,.T.);
#1985=ORIENTED_EDGE('',*,*,#272,.F.);
#1986=EDGE_LOOP('',(#1830,#1983,#1984,#1985));
#1987=FACE_BOUND('',#1986,.T.);
#1988=ADVANCED_FACE('F149',(#1987),#1670,.F.);
#1989=ORIENTED_EDGE('',*,*,#41,.F.);
#1990=ORIENTED_EDGE('',*,*,#1823,.F.);
#1991=ORIENTED_EDGE('',*,*,#149,.F.);
#1992=ORIENTED_EDGE('',*,*,#1016,.F.);
#1993=EDGE_LOOP('',(#1989,#1990,#1991,#1992));
#1994=FACE_BOUND('',#1993,.T.);
#1995=ADVANCED_FACE('F245',(#1994),#864,.T.);
#1996=ORIENTED_EDGE('',*,*,#351,.F.);
#1997=ORIENTED_EDGE('',*,*,#1982,.F.);
#1998=ORIENTED_EDGE('',*,*,#101,.F.);
#1999=ORIENTED_EDGE('',*,*,#1623,.F.);
#2000=EDGE_LOOP('',(#1996,#1997,#1998,#1999));
#2001=FACE_BOUND('',#2000,.T.);
#2002=ADVANCED_FACE('F240',(#2001),#1471,.T.);
#2003=CLOSED_SHELL('',(#83,#135,#187,#226,#258,#295,#323,#335,#371,#389,#407,#1635,#1653,#1665,
#1829,#1988,#1995,#2002));
#2004=MANIFOLD_SOLID_BREP('B2',#2003);
#2005=ADVANCED_BREP_SHAPE_REPRESENTATION('',(#18,#2004),#14);
#2006=SHAPE_DEFINITION_REPRESENTATION(#9,#2005);
ENDSEC;
END-ISO-10303-21;
